VERSION 5.8 ;
BUSBITCHARS "[]" ;
DIVIDERCHAR "/" ;
UNITS
    DATABASE MICRONS 1000 ;
END UNITS

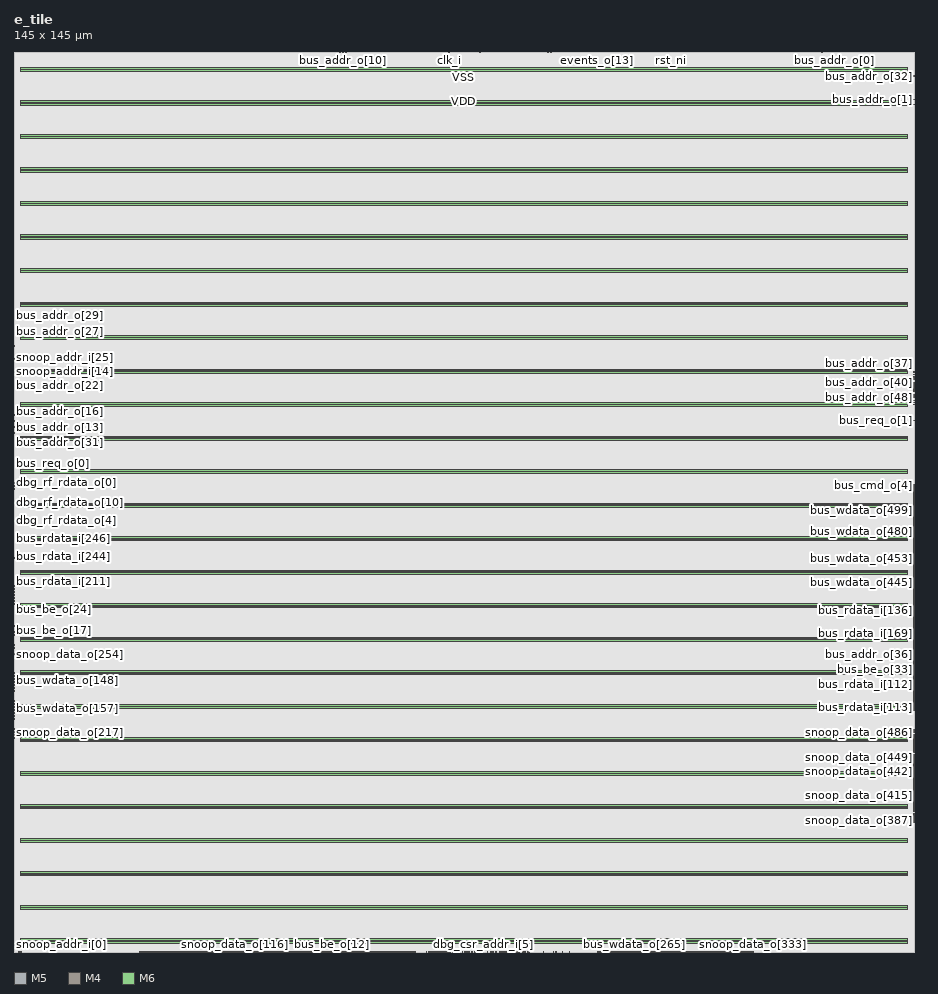
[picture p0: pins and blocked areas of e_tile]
MACRO e_tile
  FOREIGN e_tile 0 0 ;
  CLASS BLOCK ;
  SIZE 145 BY 145 ;
  PIN bus_addr_o[0]
    DIRECTION OUTPUT ;
    USE SIGNAL ;
    PORT
      LAYER M5 ;
        RECT  132.192 144.916 132.216 145 ;
    END
  END bus_addr_o[0]
  PIN bus_addr_o[10]
    DIRECTION OUTPUT ;
    USE SIGNAL ;
    PORT
      LAYER M5 ;
        RECT  52.992 144.916 53.016 145 ;
    END
  END bus_addr_o[10]
  PIN bus_addr_o[11]
    DIRECTION OUTPUT ;
    USE SIGNAL ;
    PORT
      LAYER M5 ;
        RECT  52.608 144.916 52.632 145 ;
    END
  END bus_addr_o[11]
  PIN bus_addr_o[12]
    DIRECTION OUTPUT ;
    USE SIGNAL ;
    PORT
      LAYER M5 ;
        RECT  52.416 144.916 52.44 145 ;
    END
  END bus_addr_o[12]
  PIN bus_addr_o[13]
    DIRECTION OUTPUT ;
    USE SIGNAL ;
    PORT
      LAYER M4 ;
        RECT  0 84.48 0.084 84.504 ;
    END
  END bus_addr_o[13]
  PIN bus_addr_o[14]
    DIRECTION OUTPUT ;
    USE SIGNAL ;
    PORT
      LAYER M4 ;
        RECT  0 84.576 0.084 84.6 ;
    END
  END bus_addr_o[14]
  PIN bus_addr_o[15]
    DIRECTION OUTPUT ;
    USE SIGNAL ;
    PORT
      LAYER M4 ;
        RECT  0 83.616 0.084 83.64 ;
    END
  END bus_addr_o[15]
  PIN bus_addr_o[16]
    DIRECTION OUTPUT ;
    USE SIGNAL ;
    PORT
      LAYER M4 ;
        RECT  0 85.728 0.084 85.752 ;
    END
  END bus_addr_o[16]
  PIN bus_addr_o[17]
    DIRECTION OUTPUT ;
    USE SIGNAL ;
    PORT
      LAYER M4 ;
        RECT  0 86.784 0.084 86.808 ;
    END
  END bus_addr_o[17]
  PIN bus_addr_o[18]
    DIRECTION OUTPUT ;
    USE SIGNAL ;
    PORT
      LAYER M4 ;
        RECT  0 86.976 0.084 87 ;
    END
  END bus_addr_o[18]
  PIN bus_addr_o[19]
    DIRECTION OUTPUT ;
    USE SIGNAL ;
    PORT
      LAYER M4 ;
        RECT  0 86.496 0.084 86.52 ;
    END
  END bus_addr_o[19]
  PIN bus_addr_o[1]
    DIRECTION OUTPUT ;
    USE SIGNAL ;
    PORT
      LAYER M4 ;
        RECT  144.916 137.28 145 137.304 ;
    END
  END bus_addr_o[1]
  PIN bus_addr_o[20]
    DIRECTION OUTPUT ;
    USE SIGNAL ;
    PORT
      LAYER M4 ;
        RECT  0 85.536 0.084 85.56 ;
    END
  END bus_addr_o[20]
  PIN bus_addr_o[21]
    DIRECTION OUTPUT ;
    USE SIGNAL ;
    PORT
      LAYER M4 ;
        RECT  0 86.88 0.084 86.904 ;
    END
  END bus_addr_o[21]
  PIN bus_addr_o[22]
    DIRECTION OUTPUT ;
    USE SIGNAL ;
    PORT
      LAYER M4 ;
        RECT  0 91.2 0.084 91.224 ;
    END
  END bus_addr_o[22]
  PIN bus_addr_o[23]
    DIRECTION OUTPUT ;
    USE SIGNAL ;
    PORT
      LAYER M4 ;
        RECT  0 88.32 0.084 88.344 ;
    END
  END bus_addr_o[23]
  PIN bus_addr_o[24]
    DIRECTION OUTPUT ;
    USE SIGNAL ;
    PORT
      LAYER M4 ;
        RECT  0 92.352 0.084 92.376 ;
    END
  END bus_addr_o[24]
  PIN bus_addr_o[25]
    DIRECTION OUTPUT ;
    USE SIGNAL ;
    PORT
      LAYER M4 ;
        RECT  0 88.896 0.084 88.92 ;
    END
  END bus_addr_o[25]
  PIN bus_addr_o[26]
    DIRECTION OUTPUT ;
    USE SIGNAL ;
    PORT
      LAYER M5 ;
        RECT  38.4 144.916 38.424 145 ;
    END
  END bus_addr_o[26]
  PIN bus_addr_o[27]
    DIRECTION OUTPUT ;
    USE SIGNAL ;
    PORT
      LAYER M4 ;
        RECT  0 99.936 0.084 99.96 ;
    END
  END bus_addr_o[27]
  PIN bus_addr_o[28]
    DIRECTION OUTPUT ;
    USE SIGNAL ;
    PORT
      LAYER M4 ;
        RECT  0 100.896 0.084 100.92 ;
    END
  END bus_addr_o[28]
  PIN bus_addr_o[29]
    DIRECTION OUTPUT ;
    USE SIGNAL ;
    PORT
      LAYER M4 ;
        RECT  0 101.184 0.084 101.208 ;
    END
  END bus_addr_o[29]
  PIN bus_addr_o[2]
    DIRECTION OUTPUT ;
    USE SIGNAL ;
    PORT
      LAYER M4 ;
        RECT  0 62.112 0.084 62.136 ;
    END
  END bus_addr_o[2]
  PIN bus_addr_o[30]
    DIRECTION OUTPUT ;
    USE SIGNAL ;
    PORT
      LAYER M5 ;
        RECT  39.552 144.916 39.576 145 ;
    END
  END bus_addr_o[30]
  PIN bus_addr_o[31]
    DIRECTION OUTPUT ;
    USE SIGNAL ;
    PORT
      LAYER M4 ;
        RECT  0 83.328 0.084 83.352 ;
    END
  END bus_addr_o[31]
  PIN bus_addr_o[32]
    DIRECTION OUTPUT ;
    USE SIGNAL ;
    PORT
      LAYER M4 ;
        RECT  144.916 141.12 145 141.144 ;
    END
  END bus_addr_o[32]
  PIN bus_addr_o[33]
    DIRECTION OUTPUT ;
    USE SIGNAL ;
    PORT
      LAYER M5 ;
        RECT  134.208 144.916 134.232 145 ;
    END
  END bus_addr_o[33]
  PIN bus_addr_o[34]
    DIRECTION OUTPUT ;
    USE SIGNAL ;
    PORT
      LAYER M4 ;
        RECT  144.916 56.64 145 56.664 ;
    END
  END bus_addr_o[34]
  PIN bus_addr_o[35]
    DIRECTION OUTPUT ;
    USE SIGNAL ;
    PORT
      LAYER M4 ;
        RECT  144.916 41.376 145 41.4 ;
    END
  END bus_addr_o[35]
  PIN bus_addr_o[36]
    DIRECTION OUTPUT ;
    USE SIGNAL ;
    PORT
      LAYER M4 ;
        RECT  144.916 47.904 145 47.928 ;
    END
  END bus_addr_o[36]
  PIN bus_addr_o[37]
    DIRECTION OUTPUT ;
    USE SIGNAL ;
    PORT
      LAYER M4 ;
        RECT  144.916 93.504 145 93.528 ;
    END
  END bus_addr_o[37]
  PIN bus_addr_o[38]
    DIRECTION OUTPUT ;
    USE SIGNAL ;
    PORT
      LAYER M4 ;
        RECT  144.916 93.408 145 93.432 ;
    END
  END bus_addr_o[38]
  PIN bus_addr_o[39]
    DIRECTION OUTPUT ;
    USE SIGNAL ;
    PORT
      LAYER M4 ;
        RECT  144.916 93.312 145 93.336 ;
    END
  END bus_addr_o[39]
  PIN bus_addr_o[3]
    DIRECTION OUTPUT ;
    USE SIGNAL ;
    PORT
      LAYER M4 ;
        RECT  0 54.048 0.084 54.072 ;
    END
  END bus_addr_o[3]
  PIN bus_addr_o[40]
    DIRECTION OUTPUT ;
    USE SIGNAL ;
    PORT
      LAYER M4 ;
        RECT  144.916 91.68 145 91.704 ;
    END
  END bus_addr_o[40]
  PIN bus_addr_o[41]
    DIRECTION OUTPUT ;
    USE SIGNAL ;
    PORT
      LAYER M4 ;
        RECT  144.916 92.64 145 92.664 ;
    END
  END bus_addr_o[41]
  PIN bus_addr_o[42]
    DIRECTION OUTPUT ;
    USE SIGNAL ;
    PORT
      LAYER M4 ;
        RECT  144.916 92.544 145 92.568 ;
    END
  END bus_addr_o[42]
  PIN bus_addr_o[43]
    DIRECTION OUTPUT ;
    USE SIGNAL ;
    PORT
      LAYER M4 ;
        RECT  144.916 93.024 145 93.048 ;
    END
  END bus_addr_o[43]
  PIN bus_addr_o[44]
    DIRECTION OUTPUT ;
    USE SIGNAL ;
    PORT
      LAYER M4 ;
        RECT  144.916 91.2 145 91.224 ;
    END
  END bus_addr_o[44]
  PIN bus_addr_o[45]
    DIRECTION OUTPUT ;
    USE SIGNAL ;
    PORT
      LAYER M4 ;
        RECT  144.916 90.72 145 90.744 ;
    END
  END bus_addr_o[45]
  PIN bus_addr_o[46]
    DIRECTION OUTPUT ;
    USE SIGNAL ;
    PORT
      LAYER M4 ;
        RECT  144.916 90.912 145 90.936 ;
    END
  END bus_addr_o[46]
  PIN bus_addr_o[47]
    DIRECTION OUTPUT ;
    USE SIGNAL ;
    PORT
      LAYER M4 ;
        RECT  144.916 90.816 145 90.84 ;
    END
  END bus_addr_o[47]
  PIN bus_addr_o[48]
    DIRECTION OUTPUT ;
    USE SIGNAL ;
    PORT
      LAYER M4 ;
        RECT  144.916 90.624 145 90.648 ;
    END
  END bus_addr_o[48]
  PIN bus_addr_o[49]
    DIRECTION OUTPUT ;
    USE SIGNAL ;
    PORT
      LAYER M4 ;
        RECT  144.916 91.488 145 91.512 ;
    END
  END bus_addr_o[49]
  PIN bus_addr_o[4]
    DIRECTION OUTPUT ;
    USE SIGNAL ;
    PORT
      LAYER M5 ;
        RECT  41.472 0 41.496 0.084 ;
    END
  END bus_addr_o[4]
  PIN bus_addr_o[50]
    DIRECTION OUTPUT ;
    USE SIGNAL ;
    PORT
      LAYER M4 ;
        RECT  144.916 92.736 145 92.76 ;
    END
  END bus_addr_o[50]
  PIN bus_addr_o[51]
    DIRECTION OUTPUT ;
    USE SIGNAL ;
    PORT
      LAYER M4 ;
        RECT  144.916 92.256 145 92.28 ;
    END
  END bus_addr_o[51]
  PIN bus_addr_o[52]
    DIRECTION OUTPUT ;
    USE SIGNAL ;
    PORT
      LAYER M4 ;
        RECT  144.916 92.352 145 92.376 ;
    END
  END bus_addr_o[52]
  PIN bus_addr_o[53]
    DIRECTION OUTPUT ;
    USE SIGNAL ;
    PORT
      LAYER M4 ;
        RECT  144.916 91.104 145 91.128 ;
    END
  END bus_addr_o[53]
  PIN bus_addr_o[54]
    DIRECTION OUTPUT ;
    USE SIGNAL ;
    PORT
      LAYER M4 ;
        RECT  144.916 90.24 145 90.264 ;
    END
  END bus_addr_o[54]
  PIN bus_addr_o[55]
    DIRECTION OUTPUT ;
    USE SIGNAL ;
    PORT
      LAYER M4 ;
        RECT  144.916 91.584 145 91.608 ;
    END
  END bus_addr_o[55]
  PIN bus_addr_o[56]
    DIRECTION OUTPUT ;
    USE SIGNAL ;
    PORT
      LAYER M4 ;
        RECT  144.916 90.528 145 90.552 ;
    END
  END bus_addr_o[56]
  PIN bus_addr_o[57]
    DIRECTION OUTPUT ;
    USE SIGNAL ;
    PORT
      LAYER M4 ;
        RECT  144.916 89.568 145 89.592 ;
    END
  END bus_addr_o[57]
  PIN bus_addr_o[58]
    DIRECTION OUTPUT ;
    USE SIGNAL ;
    PORT
      LAYER M4 ;
        RECT  144.916 91.296 145 91.32 ;
    END
  END bus_addr_o[58]
  PIN bus_addr_o[59]
    DIRECTION OUTPUT ;
    USE SIGNAL ;
    PORT
      LAYER M4 ;
        RECT  144.916 89.472 145 89.496 ;
    END
  END bus_addr_o[59]
  PIN bus_addr_o[5]
    DIRECTION OUTPUT ;
    USE SIGNAL ;
    PORT
      LAYER M5 ;
        RECT  52.224 144.916 52.248 145 ;
    END
  END bus_addr_o[5]
  PIN bus_addr_o[60]
    DIRECTION OUTPUT ;
    USE SIGNAL ;
    PORT
      LAYER M4 ;
        RECT  144.916 89.376 145 89.4 ;
    END
  END bus_addr_o[60]
  PIN bus_addr_o[61]
    DIRECTION OUTPUT ;
    USE SIGNAL ;
    PORT
      LAYER M4 ;
        RECT  144.916 89.28 145 89.304 ;
    END
  END bus_addr_o[61]
  PIN bus_addr_o[62]
    DIRECTION OUTPUT ;
    USE SIGNAL ;
    PORT
      LAYER M4 ;
        RECT  144.916 88.896 145 88.92 ;
    END
  END bus_addr_o[62]
  PIN bus_addr_o[63]
    DIRECTION OUTPUT ;
    USE SIGNAL ;
    PORT
      LAYER M4 ;
        RECT  144.916 89.76 145 89.784 ;
    END
  END bus_addr_o[63]
  PIN bus_addr_o[6]
    DIRECTION OUTPUT ;
    USE SIGNAL ;
    PORT
      LAYER M5 ;
        RECT  52.8 144.916 52.824 145 ;
    END
  END bus_addr_o[6]
  PIN bus_addr_o[7]
    DIRECTION OUTPUT ;
    USE SIGNAL ;
    PORT
      LAYER M5 ;
        RECT  52.32 144.916 52.344 145 ;
    END
  END bus_addr_o[7]
  PIN bus_addr_o[8]
    DIRECTION OUTPUT ;
    USE SIGNAL ;
    PORT
      LAYER M5 ;
        RECT  52.512 144.916 52.536 145 ;
    END
  END bus_addr_o[8]
  PIN bus_addr_o[9]
    DIRECTION OUTPUT ;
    USE SIGNAL ;
    PORT
      LAYER M5 ;
        RECT  52.896 144.916 52.92 145 ;
    END
  END bus_addr_o[9]
  PIN bus_be_o[0]
    DIRECTION OUTPUT ;
    USE SIGNAL ;
    PORT
      LAYER M5 ;
        RECT  51.936 0 51.96 0.084 ;
    END
  END bus_be_o[0]
  PIN bus_be_o[10]
    DIRECTION OUTPUT ;
    USE SIGNAL ;
    PORT
      LAYER M5 ;
        RECT  42.144 0 42.168 0.084 ;
    END
  END bus_be_o[10]
  PIN bus_be_o[11]
    DIRECTION OUTPUT ;
    USE SIGNAL ;
    PORT
      LAYER M5 ;
        RECT  41.568 0 41.592 0.084 ;
    END
  END bus_be_o[11]
  PIN bus_be_o[12]
    DIRECTION OUTPUT ;
    USE SIGNAL ;
    PORT
      LAYER M5 ;
        RECT  51.264 0 51.288 0.084 ;
    END
  END bus_be_o[12]
  PIN bus_be_o[13]
    DIRECTION OUTPUT ;
    USE SIGNAL ;
    PORT
      LAYER M5 ;
        RECT  41.856 0 41.88 0.084 ;
    END
  END bus_be_o[13]
  PIN bus_be_o[14]
    DIRECTION OUTPUT ;
    USE SIGNAL ;
    PORT
      LAYER M4 ;
        RECT  0 50.4 0.084 50.424 ;
    END
  END bus_be_o[14]
  PIN bus_be_o[15]
    DIRECTION OUTPUT ;
    USE SIGNAL ;
    PORT
      LAYER M5 ;
        RECT  45.888 0 45.912 0.084 ;
    END
  END bus_be_o[15]
  PIN bus_be_o[16]
    DIRECTION OUTPUT ;
    USE SIGNAL ;
    PORT
      LAYER M5 ;
        RECT  49.536 0 49.56 0.084 ;
    END
  END bus_be_o[16]
  PIN bus_be_o[17]
    DIRECTION OUTPUT ;
    USE SIGNAL ;
    PORT
      LAYER M4 ;
        RECT  0 51.84 0.084 51.864 ;
    END
  END bus_be_o[17]
  PIN bus_be_o[18]
    DIRECTION OUTPUT ;
    USE SIGNAL ;
    PORT
      LAYER M4 ;
        RECT  0 51.744 0.084 51.768 ;
    END
  END bus_be_o[18]
  PIN bus_be_o[19]
    DIRECTION OUTPUT ;
    USE SIGNAL ;
    PORT
      LAYER M4 ;
        RECT  0 51.648 0.084 51.672 ;
    END
  END bus_be_o[19]
  PIN bus_be_o[1]
    DIRECTION OUTPUT ;
    USE SIGNAL ;
    PORT
      LAYER M5 ;
        RECT  46.944 0 46.968 0.084 ;
    END
  END bus_be_o[1]
  PIN bus_be_o[20]
    DIRECTION OUTPUT ;
    USE SIGNAL ;
    PORT
      LAYER M5 ;
        RECT  49.824 0 49.848 0.084 ;
    END
  END bus_be_o[20]
  PIN bus_be_o[21]
    DIRECTION OUTPUT ;
    USE SIGNAL ;
    PORT
      LAYER M4 ;
        RECT  0 55.104 0.084 55.128 ;
    END
  END bus_be_o[21]
  PIN bus_be_o[22]
    DIRECTION OUTPUT ;
    USE SIGNAL ;
    PORT
      LAYER M4 ;
        RECT  0 55.296 0.084 55.32 ;
    END
  END bus_be_o[22]
  PIN bus_be_o[23]
    DIRECTION OUTPUT ;
    USE SIGNAL ;
    PORT
      LAYER M4 ;
        RECT  0 56.352 0.084 56.376 ;
    END
  END bus_be_o[23]
  PIN bus_be_o[24]
    DIRECTION OUTPUT ;
    USE SIGNAL ;
    PORT
      LAYER M4 ;
        RECT  0 55.2 0.084 55.224 ;
    END
  END bus_be_o[24]
  PIN bus_be_o[25]
    DIRECTION OUTPUT ;
    USE SIGNAL ;
    PORT
      LAYER M4 ;
        RECT  0 56.256 0.084 56.28 ;
    END
  END bus_be_o[25]
  PIN bus_be_o[26]
    DIRECTION OUTPUT ;
    USE SIGNAL ;
    PORT
      LAYER M4 ;
        RECT  0 58.272 0.084 58.296 ;
    END
  END bus_be_o[26]
  PIN bus_be_o[27]
    DIRECTION OUTPUT ;
    USE SIGNAL ;
    PORT
      LAYER M4 ;
        RECT  0 58.464 0.084 58.488 ;
    END
  END bus_be_o[27]
  PIN bus_be_o[28]
    DIRECTION OUTPUT ;
    USE SIGNAL ;
    PORT
      LAYER M4 ;
        RECT  0 57.696 0.084 57.72 ;
    END
  END bus_be_o[28]
  PIN bus_be_o[29]
    DIRECTION OUTPUT ;
    USE SIGNAL ;
    PORT
      LAYER M4 ;
        RECT  0 58.368 0.084 58.392 ;
    END
  END bus_be_o[29]
  PIN bus_be_o[2]
    DIRECTION OUTPUT ;
    USE SIGNAL ;
    PORT
      LAYER M5 ;
        RECT  49.92 0 49.944 0.084 ;
    END
  END bus_be_o[2]
  PIN bus_be_o[30]
    DIRECTION OUTPUT ;
    USE SIGNAL ;
    PORT
      LAYER M4 ;
        RECT  0 58.56 0.084 58.584 ;
    END
  END bus_be_o[30]
  PIN bus_be_o[31]
    DIRECTION OUTPUT ;
    USE SIGNAL ;
    PORT
      LAYER M4 ;
        RECT  0 57.6 0.084 57.624 ;
    END
  END bus_be_o[31]
  PIN bus_be_o[32]
    DIRECTION OUTPUT ;
    USE SIGNAL ;
    PORT
      LAYER M4 ;
        RECT  144.916 46.944 145 46.968 ;
    END
  END bus_be_o[32]
  PIN bus_be_o[33]
    DIRECTION OUTPUT ;
    USE SIGNAL ;
    PORT
      LAYER M4 ;
        RECT  144.916 46.848 145 46.872 ;
    END
  END bus_be_o[33]
  PIN bus_be_o[34]
    DIRECTION OUTPUT ;
    USE SIGNAL ;
    PORT
      LAYER M4 ;
        RECT  144.916 47.136 145 47.16 ;
    END
  END bus_be_o[34]
  PIN bus_be_o[35]
    DIRECTION OUTPUT ;
    USE SIGNAL ;
    PORT
      LAYER M4 ;
        RECT  144.916 42.24 145 42.264 ;
    END
  END bus_be_o[35]
  PIN bus_be_o[36]
    DIRECTION OUTPUT ;
    USE SIGNAL ;
    PORT
      LAYER M4 ;
        RECT  144.916 44.928 145 44.952 ;
    END
  END bus_be_o[36]
  PIN bus_be_o[37]
    DIRECTION OUTPUT ;
    USE SIGNAL ;
    PORT
      LAYER M4 ;
        RECT  144.916 45.888 145 45.912 ;
    END
  END bus_be_o[37]
  PIN bus_be_o[38]
    DIRECTION OUTPUT ;
    USE SIGNAL ;
    PORT
      LAYER M4 ;
        RECT  144.916 46.272 145 46.296 ;
    END
  END bus_be_o[38]
  PIN bus_be_o[39]
    DIRECTION OUTPUT ;
    USE SIGNAL ;
    PORT
      LAYER M4 ;
        RECT  144.916 46.464 145 46.488 ;
    END
  END bus_be_o[39]
  PIN bus_be_o[3]
    DIRECTION OUTPUT ;
    USE SIGNAL ;
    PORT
      LAYER M5 ;
        RECT  48.768 0 48.792 0.084 ;
    END
  END bus_be_o[3]
  PIN bus_be_o[40]
    DIRECTION OUTPUT ;
    USE SIGNAL ;
    PORT
      LAYER M4 ;
        RECT  144.916 47.04 145 47.064 ;
    END
  END bus_be_o[40]
  PIN bus_be_o[41]
    DIRECTION OUTPUT ;
    USE SIGNAL ;
    PORT
      LAYER M4 ;
        RECT  144.916 47.232 145 47.256 ;
    END
  END bus_be_o[41]
  PIN bus_be_o[42]
    DIRECTION OUTPUT ;
    USE SIGNAL ;
    PORT
      LAYER M4 ;
        RECT  144.916 46.752 145 46.776 ;
    END
  END bus_be_o[42]
  PIN bus_be_o[43]
    DIRECTION OUTPUT ;
    USE SIGNAL ;
    PORT
      LAYER M4 ;
        RECT  144.916 45.792 145 45.816 ;
    END
  END bus_be_o[43]
  PIN bus_be_o[44]
    DIRECTION OUTPUT ;
    USE SIGNAL ;
    PORT
      LAYER M4 ;
        RECT  144.916 46.368 145 46.392 ;
    END
  END bus_be_o[44]
  PIN bus_be_o[45]
    DIRECTION OUTPUT ;
    USE SIGNAL ;
    PORT
      LAYER M4 ;
        RECT  144.916 46.08 145 46.104 ;
    END
  END bus_be_o[45]
  PIN bus_be_o[46]
    DIRECTION OUTPUT ;
    USE SIGNAL ;
    PORT
      LAYER M4 ;
        RECT  144.916 45.984 145 46.008 ;
    END
  END bus_be_o[46]
  PIN bus_be_o[47]
    DIRECTION OUTPUT ;
    USE SIGNAL ;
    PORT
      LAYER M4 ;
        RECT  144.916 46.176 145 46.2 ;
    END
  END bus_be_o[47]
  PIN bus_be_o[48]
    DIRECTION OUTPUT ;
    USE SIGNAL ;
    PORT
      LAYER M4 ;
        RECT  144.916 48 145 48.024 ;
    END
  END bus_be_o[48]
  PIN bus_be_o[49]
    DIRECTION OUTPUT ;
    USE SIGNAL ;
    PORT
      LAYER M4 ;
        RECT  144.916 48.192 145 48.216 ;
    END
  END bus_be_o[49]
  PIN bus_be_o[4]
    DIRECTION OUTPUT ;
    USE SIGNAL ;
    PORT
      LAYER M5 ;
        RECT  51.072 0 51.096 0.084 ;
    END
  END bus_be_o[4]
  PIN bus_be_o[50]
    DIRECTION OUTPUT ;
    USE SIGNAL ;
    PORT
      LAYER M4 ;
        RECT  144.916 47.808 145 47.832 ;
    END
  END bus_be_o[50]
  PIN bus_be_o[51]
    DIRECTION OUTPUT ;
    USE SIGNAL ;
    PORT
      LAYER M4 ;
        RECT  144.916 48.288 145 48.312 ;
    END
  END bus_be_o[51]
  PIN bus_be_o[52]
    DIRECTION OUTPUT ;
    USE SIGNAL ;
    PORT
      LAYER M4 ;
        RECT  144.916 49.824 145 49.848 ;
    END
  END bus_be_o[52]
  PIN bus_be_o[53]
    DIRECTION OUTPUT ;
    USE SIGNAL ;
    PORT
      LAYER M4 ;
        RECT  144.916 50.016 145 50.04 ;
    END
  END bus_be_o[53]
  PIN bus_be_o[54]
    DIRECTION OUTPUT ;
    USE SIGNAL ;
    PORT
      LAYER M4 ;
        RECT  144.916 50.496 145 50.52 ;
    END
  END bus_be_o[54]
  PIN bus_be_o[55]
    DIRECTION OUTPUT ;
    USE SIGNAL ;
    PORT
      LAYER M4 ;
        RECT  144.916 50.112 145 50.136 ;
    END
  END bus_be_o[55]
  PIN bus_be_o[56]
    DIRECTION OUTPUT ;
    USE SIGNAL ;
    PORT
      LAYER M4 ;
        RECT  144.916 48.672 145 48.696 ;
    END
  END bus_be_o[56]
  PIN bus_be_o[57]
    DIRECTION OUTPUT ;
    USE SIGNAL ;
    PORT
      LAYER M4 ;
        RECT  144.916 49.152 145 49.176 ;
    END
  END bus_be_o[57]
  PIN bus_be_o[58]
    DIRECTION OUTPUT ;
    USE SIGNAL ;
    PORT
      LAYER M4 ;
        RECT  144.916 48.96 145 48.984 ;
    END
  END bus_be_o[58]
  PIN bus_be_o[59]
    DIRECTION OUTPUT ;
    USE SIGNAL ;
    PORT
      LAYER M4 ;
        RECT  144.916 40.224 145 40.248 ;
    END
  END bus_be_o[59]
  PIN bus_be_o[5]
    DIRECTION OUTPUT ;
    USE SIGNAL ;
    PORT
      LAYER M5 ;
        RECT  49.056 0 49.08 0.084 ;
    END
  END bus_be_o[5]
  PIN bus_be_o[60]
    DIRECTION OUTPUT ;
    USE SIGNAL ;
    PORT
      LAYER M4 ;
        RECT  144.916 50.88 145 50.904 ;
    END
  END bus_be_o[60]
  PIN bus_be_o[61]
    DIRECTION OUTPUT ;
    USE SIGNAL ;
    PORT
      LAYER M4 ;
        RECT  144.916 50.784 145 50.808 ;
    END
  END bus_be_o[61]
  PIN bus_be_o[62]
    DIRECTION OUTPUT ;
    USE SIGNAL ;
    PORT
      LAYER M4 ;
        RECT  144.916 50.592 145 50.616 ;
    END
  END bus_be_o[62]
  PIN bus_be_o[63]
    DIRECTION OUTPUT ;
    USE SIGNAL ;
    PORT
      LAYER M4 ;
        RECT  144.916 50.688 145 50.712 ;
    END
  END bus_be_o[63]
  PIN bus_be_o[6]
    DIRECTION OUTPUT ;
    USE SIGNAL ;
    PORT
      LAYER M5 ;
        RECT  45.792 0 45.816 0.084 ;
    END
  END bus_be_o[6]
  PIN bus_be_o[7]
    DIRECTION OUTPUT ;
    USE SIGNAL ;
    PORT
      LAYER M5 ;
        RECT  42.24 0 42.264 0.084 ;
    END
  END bus_be_o[7]
  PIN bus_be_o[8]
    DIRECTION OUTPUT ;
    USE SIGNAL ;
    PORT
      LAYER M5 ;
        RECT  49.728 0 49.752 0.084 ;
    END
  END bus_be_o[8]
  PIN bus_be_o[9]
    DIRECTION OUTPUT ;
    USE SIGNAL ;
    PORT
      LAYER M5 ;
        RECT  46.464 0 46.488 0.084 ;
    END
  END bus_be_o[9]
  PIN bus_cmd_o[0]
    DIRECTION OUTPUT ;
    USE SIGNAL ;
    PORT
      LAYER M4 ;
        RECT  0 57.312 0.084 57.336 ;
    END
  END bus_cmd_o[0]
  PIN bus_cmd_o[1]
    DIRECTION OUTPUT ;
    USE SIGNAL ;
    PORT
      LAYER M4 ;
        RECT  0 57.504 0.084 57.528 ;
    END
  END bus_cmd_o[1]
  PIN bus_cmd_o[2]
    DIRECTION OUTPUT ;
    USE SIGNAL ;
    PORT
      LAYER M4 ;
        RECT  0 57.408 0.084 57.432 ;
    END
  END bus_cmd_o[2]
  PIN bus_cmd_o[3]
    DIRECTION OUTPUT ;
    USE SIGNAL ;
    PORT
      LAYER M4 ;
        RECT  144.916 57.792 145 57.816 ;
    END
  END bus_cmd_o[3]
  PIN bus_cmd_o[4]
    DIRECTION OUTPUT ;
    USE SIGNAL ;
    PORT
      LAYER M4 ;
        RECT  144.916 75.168 145 75.192 ;
    END
  END bus_cmd_o[4]
  PIN bus_cmd_o[5]
    DIRECTION OUTPUT ;
    USE SIGNAL ;
    PORT
      LAYER M4 ;
        RECT  144.916 70.176 145 70.2 ;
    END
  END bus_cmd_o[5]
  PIN bus_done_i[0]
    DIRECTION INPUT ;
    USE SIGNAL ;
    PORT
      LAYER M5 ;
        RECT  55.68 144.916 55.704 145 ;
    END
  END bus_done_i[0]
  PIN bus_done_i[1]
    DIRECTION INPUT ;
    USE SIGNAL ;
    PORT
      LAYER M4 ;
        RECT  144.916 88.512 145 88.536 ;
    END
  END bus_done_i[1]
  PIN bus_err_i
    DIRECTION INPUT ;
    USE SIGNAL ;
    PORT
      LAYER M4 ;
        RECT  144.916 75.36 145 75.384 ;
    END
  END bus_err_i
  PIN bus_rdata_i[0]
    DIRECTION INPUT ;
    USE SIGNAL ;
    PORT
      LAYER M5 ;
        RECT  58.368 0 58.392 0.084 ;
    END
  END bus_rdata_i[0]
  PIN bus_rdata_i[100]
    DIRECTION INPUT ;
    USE SIGNAL ;
    PORT
      LAYER M5 ;
        RECT  58.464 0 58.488 0.084 ;
    END
  END bus_rdata_i[100]
  PIN bus_rdata_i[101]
    DIRECTION INPUT ;
    USE SIGNAL ;
    PORT
      LAYER M5 ;
        RECT  58.56 0 58.584 0.084 ;
    END
  END bus_rdata_i[101]
  PIN bus_rdata_i[102]
    DIRECTION INPUT ;
    USE SIGNAL ;
    PORT
      LAYER M5 ;
        RECT  58.656 0 58.68 0.084 ;
    END
  END bus_rdata_i[102]
  PIN bus_rdata_i[103]
    DIRECTION INPUT ;
    USE SIGNAL ;
    PORT
      LAYER M5 ;
        RECT  58.752 0 58.776 0.084 ;
    END
  END bus_rdata_i[103]
  PIN bus_rdata_i[104]
    DIRECTION INPUT ;
    USE SIGNAL ;
    PORT
      LAYER M5 ;
        RECT  58.848 0 58.872 0.084 ;
    END
  END bus_rdata_i[104]
  PIN bus_rdata_i[105]
    DIRECTION INPUT ;
    USE SIGNAL ;
    PORT
      LAYER M4 ;
        RECT  144.916 41.088 145 41.112 ;
    END
  END bus_rdata_i[105]
  PIN bus_rdata_i[106]
    DIRECTION INPUT ;
    USE SIGNAL ;
    PORT
      LAYER M4 ;
        RECT  144.916 41.856 145 41.88 ;
    END
  END bus_rdata_i[106]
  PIN bus_rdata_i[107]
    DIRECTION INPUT ;
    USE SIGNAL ;
    PORT
      LAYER M4 ;
        RECT  144.916 42.048 145 42.072 ;
    END
  END bus_rdata_i[107]
  PIN bus_rdata_i[108]
    DIRECTION INPUT ;
    USE SIGNAL ;
    PORT
      LAYER M4 ;
        RECT  144.916 43.872 145 43.896 ;
    END
  END bus_rdata_i[108]
  PIN bus_rdata_i[109]
    DIRECTION INPUT ;
    USE SIGNAL ;
    PORT
      LAYER M4 ;
        RECT  144.916 44.448 145 44.472 ;
    END
  END bus_rdata_i[109]
  PIN bus_rdata_i[10]
    DIRECTION INPUT ;
    USE SIGNAL ;
    PORT
      LAYER M5 ;
        RECT  56.256 0 56.28 0.084 ;
    END
  END bus_rdata_i[10]
  PIN bus_rdata_i[110]
    DIRECTION INPUT ;
    USE SIGNAL ;
    PORT
      LAYER M4 ;
        RECT  144.916 42.432 145 42.456 ;
    END
  END bus_rdata_i[110]
  PIN bus_rdata_i[111]
    DIRECTION INPUT ;
    USE SIGNAL ;
    PORT
      LAYER M4 ;
        RECT  144.916 42.144 145 42.168 ;
    END
  END bus_rdata_i[111]
  PIN bus_rdata_i[112]
    DIRECTION INPUT ;
    USE SIGNAL ;
    PORT
      LAYER M4 ;
        RECT  144.916 43.008 145 43.032 ;
    END
  END bus_rdata_i[112]
  PIN bus_rdata_i[113]
    DIRECTION INPUT ;
    USE SIGNAL ;
    PORT
      LAYER M4 ;
        RECT  144.916 39.456 145 39.48 ;
    END
  END bus_rdata_i[113]
  PIN bus_rdata_i[114]
    DIRECTION INPUT ;
    USE SIGNAL ;
    PORT
      LAYER M4 ;
        RECT  144.916 43.104 145 43.128 ;
    END
  END bus_rdata_i[114]
  PIN bus_rdata_i[115]
    DIRECTION INPUT ;
    USE SIGNAL ;
    PORT
      LAYER M4 ;
        RECT  144.916 41.952 145 41.976 ;
    END
  END bus_rdata_i[115]
  PIN bus_rdata_i[116]
    DIRECTION INPUT ;
    USE SIGNAL ;
    PORT
      LAYER M4 ;
        RECT  144.916 39.552 145 39.576 ;
    END
  END bus_rdata_i[116]
  PIN bus_rdata_i[117]
    DIRECTION INPUT ;
    USE SIGNAL ;
    PORT
      LAYER M4 ;
        RECT  144.916 40.128 145 40.152 ;
    END
  END bus_rdata_i[117]
  PIN bus_rdata_i[118]
    DIRECTION INPUT ;
    USE SIGNAL ;
    PORT
      LAYER M4 ;
        RECT  144.916 39.648 145 39.672 ;
    END
  END bus_rdata_i[118]
  PIN bus_rdata_i[119]
    DIRECTION INPUT ;
    USE SIGNAL ;
    PORT
      LAYER M4 ;
        RECT  144.916 39.264 145 39.288 ;
    END
  END bus_rdata_i[119]
  PIN bus_rdata_i[11]
    DIRECTION INPUT ;
    USE SIGNAL ;
    PORT
      LAYER M5 ;
        RECT  57.984 0 58.008 0.084 ;
    END
  END bus_rdata_i[11]
  PIN bus_rdata_i[120]
    DIRECTION INPUT ;
    USE SIGNAL ;
    PORT
      LAYER M4 ;
        RECT  144.916 42.816 145 42.84 ;
    END
  END bus_rdata_i[120]
  PIN bus_rdata_i[121]
    DIRECTION INPUT ;
    USE SIGNAL ;
    PORT
      LAYER M4 ;
        RECT  144.916 42.336 145 42.36 ;
    END
  END bus_rdata_i[121]
  PIN bus_rdata_i[122]
    DIRECTION INPUT ;
    USE SIGNAL ;
    PORT
      LAYER M4 ;
        RECT  144.916 43.584 145 43.608 ;
    END
  END bus_rdata_i[122]
  PIN bus_rdata_i[123]
    DIRECTION INPUT ;
    USE SIGNAL ;
    PORT
      LAYER M4 ;
        RECT  144.916 42.624 145 42.648 ;
    END
  END bus_rdata_i[123]
  PIN bus_rdata_i[124]
    DIRECTION INPUT ;
    USE SIGNAL ;
    PORT
      LAYER M4 ;
        RECT  144.916 47.712 145 47.736 ;
    END
  END bus_rdata_i[124]
  PIN bus_rdata_i[125]
    DIRECTION INPUT ;
    USE SIGNAL ;
    PORT
      LAYER M4 ;
        RECT  144.916 40.8 145 40.824 ;
    END
  END bus_rdata_i[125]
  PIN bus_rdata_i[126]
    DIRECTION INPUT ;
    USE SIGNAL ;
    PORT
      LAYER M4 ;
        RECT  144.916 44.064 145 44.088 ;
    END
  END bus_rdata_i[126]
  PIN bus_rdata_i[127]
    DIRECTION INPUT ;
    USE SIGNAL ;
    PORT
      LAYER M4 ;
        RECT  144.916 44.352 145 44.376 ;
    END
  END bus_rdata_i[127]
  PIN bus_rdata_i[128]
    DIRECTION INPUT ;
    USE SIGNAL ;
    PORT
      LAYER M4 ;
        RECT  144.916 48.096 145 48.12 ;
    END
  END bus_rdata_i[128]
  PIN bus_rdata_i[129]
    DIRECTION INPUT ;
    USE SIGNAL ;
    PORT
      LAYER M5 ;
        RECT  58.944 0 58.968 0.084 ;
    END
  END bus_rdata_i[129]
  PIN bus_rdata_i[12]
    DIRECTION INPUT ;
    USE SIGNAL ;
    PORT
      LAYER M5 ;
        RECT  57.888 0 57.912 0.084 ;
    END
  END bus_rdata_i[12]
  PIN bus_rdata_i[130]
    DIRECTION INPUT ;
    USE SIGNAL ;
    PORT
      LAYER M5 ;
        RECT  59.04 0 59.064 0.084 ;
    END
  END bus_rdata_i[130]
  PIN bus_rdata_i[131]
    DIRECTION INPUT ;
    USE SIGNAL ;
    PORT
      LAYER M5 ;
        RECT  59.136 0 59.16 0.084 ;
    END
  END bus_rdata_i[131]
  PIN bus_rdata_i[132]
    DIRECTION INPUT ;
    USE SIGNAL ;
    PORT
      LAYER M5 ;
        RECT  59.232 0 59.256 0.084 ;
    END
  END bus_rdata_i[132]
  PIN bus_rdata_i[133]
    DIRECTION INPUT ;
    USE SIGNAL ;
    PORT
      LAYER M4 ;
        RECT  144.916 41.568 145 41.592 ;
    END
  END bus_rdata_i[133]
  PIN bus_rdata_i[134]
    DIRECTION INPUT ;
    USE SIGNAL ;
    PORT
      LAYER M5 ;
        RECT  59.328 0 59.352 0.084 ;
    END
  END bus_rdata_i[134]
  PIN bus_rdata_i[135]
    DIRECTION INPUT ;
    USE SIGNAL ;
    PORT
      LAYER M4 ;
        RECT  144.916 39.36 145 39.384 ;
    END
  END bus_rdata_i[135]
  PIN bus_rdata_i[136]
    DIRECTION INPUT ;
    USE SIGNAL ;
    PORT
      LAYER M4 ;
        RECT  144.916 55.008 145 55.032 ;
    END
  END bus_rdata_i[136]
  PIN bus_rdata_i[137]
    DIRECTION INPUT ;
    USE SIGNAL ;
    PORT
      LAYER M4 ;
        RECT  144.916 54.24 145 54.264 ;
    END
  END bus_rdata_i[137]
  PIN bus_rdata_i[138]
    DIRECTION INPUT ;
    USE SIGNAL ;
    PORT
      LAYER M4 ;
        RECT  144.916 55.776 145 55.8 ;
    END
  END bus_rdata_i[138]
  PIN bus_rdata_i[139]
    DIRECTION INPUT ;
    USE SIGNAL ;
    PORT
      LAYER M4 ;
        RECT  144.916 53.088 145 53.112 ;
    END
  END bus_rdata_i[139]
  PIN bus_rdata_i[13]
    DIRECTION INPUT ;
    USE SIGNAL ;
    PORT
      LAYER M5 ;
        RECT  57.792 0 57.816 0.084 ;
    END
  END bus_rdata_i[13]
  PIN bus_rdata_i[140]
    DIRECTION INPUT ;
    USE SIGNAL ;
    PORT
      LAYER M4 ;
        RECT  144.916 54.144 145 54.168 ;
    END
  END bus_rdata_i[140]
  PIN bus_rdata_i[141]
    DIRECTION INPUT ;
    USE SIGNAL ;
    PORT
      LAYER M4 ;
        RECT  144.916 53.856 145 53.88 ;
    END
  END bus_rdata_i[141]
  PIN bus_rdata_i[142]
    DIRECTION INPUT ;
    USE SIGNAL ;
    PORT
      LAYER M4 ;
        RECT  144.916 54.048 145 54.072 ;
    END
  END bus_rdata_i[142]
  PIN bus_rdata_i[143]
    DIRECTION INPUT ;
    USE SIGNAL ;
    PORT
      LAYER M4 ;
        RECT  144.916 54.816 145 54.84 ;
    END
  END bus_rdata_i[143]
  PIN bus_rdata_i[144]
    DIRECTION INPUT ;
    USE SIGNAL ;
    PORT
      LAYER M4 ;
        RECT  144.916 55.104 145 55.128 ;
    END
  END bus_rdata_i[144]
  PIN bus_rdata_i[145]
    DIRECTION INPUT ;
    USE SIGNAL ;
    PORT
      LAYER M4 ;
        RECT  144.916 53.184 145 53.208 ;
    END
  END bus_rdata_i[145]
  PIN bus_rdata_i[146]
    DIRECTION INPUT ;
    USE SIGNAL ;
    PORT
      LAYER M4 ;
        RECT  144.916 53.472 145 53.496 ;
    END
  END bus_rdata_i[146]
  PIN bus_rdata_i[147]
    DIRECTION INPUT ;
    USE SIGNAL ;
    PORT
      LAYER M4 ;
        RECT  144.916 52.896 145 52.92 ;
    END
  END bus_rdata_i[147]
  PIN bus_rdata_i[148]
    DIRECTION INPUT ;
    USE SIGNAL ;
    PORT
      LAYER M4 ;
        RECT  144.916 53.568 145 53.592 ;
    END
  END bus_rdata_i[148]
  PIN bus_rdata_i[149]
    DIRECTION INPUT ;
    USE SIGNAL ;
    PORT
      LAYER M4 ;
        RECT  0 53.568 0.084 53.592 ;
    END
  END bus_rdata_i[149]
  PIN bus_rdata_i[14]
    DIRECTION INPUT ;
    USE SIGNAL ;
    PORT
      LAYER M5 ;
        RECT  57.696 0 57.72 0.084 ;
    END
  END bus_rdata_i[14]
  PIN bus_rdata_i[150]
    DIRECTION INPUT ;
    USE SIGNAL ;
    PORT
      LAYER M4 ;
        RECT  0 53.376 0.084 53.4 ;
    END
  END bus_rdata_i[150]
  PIN bus_rdata_i[151]
    DIRECTION INPUT ;
    USE SIGNAL ;
    PORT
      LAYER M4 ;
        RECT  0 53.28 0.084 53.304 ;
    END
  END bus_rdata_i[151]
  PIN bus_rdata_i[152]
    DIRECTION INPUT ;
    USE SIGNAL ;
    PORT
      LAYER M4 ;
        RECT  144.916 56.064 145 56.088 ;
    END
  END bus_rdata_i[152]
  PIN bus_rdata_i[153]
    DIRECTION INPUT ;
    USE SIGNAL ;
    PORT
      LAYER M4 ;
        RECT  144.916 53.76 145 53.784 ;
    END
  END bus_rdata_i[153]
  PIN bus_rdata_i[154]
    DIRECTION INPUT ;
    USE SIGNAL ;
    PORT
      LAYER M4 ;
        RECT  144.916 52.608 145 52.632 ;
    END
  END bus_rdata_i[154]
  PIN bus_rdata_i[155]
    DIRECTION INPUT ;
    USE SIGNAL ;
    PORT
      LAYER M4 ;
        RECT  144.916 52.128 145 52.152 ;
    END
  END bus_rdata_i[155]
  PIN bus_rdata_i[156]
    DIRECTION INPUT ;
    USE SIGNAL ;
    PORT
      LAYER M4 ;
        RECT  144.916 53.376 145 53.4 ;
    END
  END bus_rdata_i[156]
  PIN bus_rdata_i[157]
    DIRECTION INPUT ;
    USE SIGNAL ;
    PORT
      LAYER M4 ;
        RECT  144.916 52.224 145 52.248 ;
    END
  END bus_rdata_i[157]
  PIN bus_rdata_i[158]
    DIRECTION INPUT ;
    USE SIGNAL ;
    PORT
      LAYER M4 ;
        RECT  144.916 52.512 145 52.536 ;
    END
  END bus_rdata_i[158]
  PIN bus_rdata_i[159]
    DIRECTION INPUT ;
    USE SIGNAL ;
    PORT
      LAYER M4 ;
        RECT  144.916 52.416 145 52.44 ;
    END
  END bus_rdata_i[159]
  PIN bus_rdata_i[15]
    DIRECTION INPUT ;
    USE SIGNAL ;
    PORT
      LAYER M5 ;
        RECT  57.6 0 57.624 0.084 ;
    END
  END bus_rdata_i[15]
  PIN bus_rdata_i[160]
    DIRECTION INPUT ;
    USE SIGNAL ;
    PORT
      LAYER M4 ;
        RECT  144.916 51.552 145 51.576 ;
    END
  END bus_rdata_i[160]
  PIN bus_rdata_i[161]
    DIRECTION INPUT ;
    USE SIGNAL ;
    PORT
      LAYER M5 ;
        RECT  59.424 0 59.448 0.084 ;
    END
  END bus_rdata_i[161]
  PIN bus_rdata_i[162]
    DIRECTION INPUT ;
    USE SIGNAL ;
    PORT
      LAYER M5 ;
        RECT  59.52 0 59.544 0.084 ;
    END
  END bus_rdata_i[162]
  PIN bus_rdata_i[163]
    DIRECTION INPUT ;
    USE SIGNAL ;
    PORT
      LAYER M5 ;
        RECT  59.616 0 59.64 0.084 ;
    END
  END bus_rdata_i[163]
  PIN bus_rdata_i[164]
    DIRECTION INPUT ;
    USE SIGNAL ;
    PORT
      LAYER M5 ;
        RECT  59.712 0 59.736 0.084 ;
    END
  END bus_rdata_i[164]
  PIN bus_rdata_i[165]
    DIRECTION INPUT ;
    USE SIGNAL ;
    PORT
      LAYER M4 ;
        RECT  144.916 41.28 145 41.304 ;
    END
  END bus_rdata_i[165]
  PIN bus_rdata_i[166]
    DIRECTION INPUT ;
    USE SIGNAL ;
    PORT
      LAYER M5 ;
        RECT  59.808 0 59.832 0.084 ;
    END
  END bus_rdata_i[166]
  PIN bus_rdata_i[167]
    DIRECTION INPUT ;
    USE SIGNAL ;
    PORT
      LAYER M4 ;
        RECT  144.916 48.384 145 48.408 ;
    END
  END bus_rdata_i[167]
  PIN bus_rdata_i[168]
    DIRECTION INPUT ;
    USE SIGNAL ;
    PORT
      LAYER M4 ;
        RECT  144.916 51.744 145 51.768 ;
    END
  END bus_rdata_i[168]
  PIN bus_rdata_i[169]
    DIRECTION INPUT ;
    USE SIGNAL ;
    PORT
      LAYER M4 ;
        RECT  144.916 51.264 145 51.288 ;
    END
  END bus_rdata_i[169]
  PIN bus_rdata_i[16]
    DIRECTION INPUT ;
    USE SIGNAL ;
    PORT
      LAYER M5 ;
        RECT  57.024 0 57.048 0.084 ;
    END
  END bus_rdata_i[16]
  PIN bus_rdata_i[170]
    DIRECTION INPUT ;
    USE SIGNAL ;
    PORT
      LAYER M4 ;
        RECT  144.916 51.168 145 51.192 ;
    END
  END bus_rdata_i[170]
  PIN bus_rdata_i[171]
    DIRECTION INPUT ;
    USE SIGNAL ;
    PORT
      LAYER M4 ;
        RECT  144.916 51.072 145 51.096 ;
    END
  END bus_rdata_i[171]
  PIN bus_rdata_i[172]
    DIRECTION INPUT ;
    USE SIGNAL ;
    PORT
      LAYER M4 ;
        RECT  144.916 51.648 145 51.672 ;
    END
  END bus_rdata_i[172]
  PIN bus_rdata_i[173]
    DIRECTION INPUT ;
    USE SIGNAL ;
    PORT
      LAYER M4 ;
        RECT  144.916 52.8 145 52.824 ;
    END
  END bus_rdata_i[173]
  PIN bus_rdata_i[174]
    DIRECTION INPUT ;
    USE SIGNAL ;
    PORT
      LAYER M4 ;
        RECT  144.916 52.992 145 53.016 ;
    END
  END bus_rdata_i[174]
  PIN bus_rdata_i[175]
    DIRECTION INPUT ;
    USE SIGNAL ;
    PORT
      LAYER M4 ;
        RECT  144.916 54.72 145 54.744 ;
    END
  END bus_rdata_i[175]
  PIN bus_rdata_i[176]
    DIRECTION INPUT ;
    USE SIGNAL ;
    PORT
      LAYER M4 ;
        RECT  144.916 54.528 145 54.552 ;
    END
  END bus_rdata_i[176]
  PIN bus_rdata_i[177]
    DIRECTION INPUT ;
    USE SIGNAL ;
    PORT
      LAYER M4 ;
        RECT  144.916 54.624 145 54.648 ;
    END
  END bus_rdata_i[177]
  PIN bus_rdata_i[178]
    DIRECTION INPUT ;
    USE SIGNAL ;
    PORT
      LAYER M4 ;
        RECT  144.916 56.448 145 56.472 ;
    END
  END bus_rdata_i[178]
  PIN bus_rdata_i[179]
    DIRECTION INPUT ;
    USE SIGNAL ;
    PORT
      LAYER M4 ;
        RECT  144.916 39.168 145 39.192 ;
    END
  END bus_rdata_i[179]
  PIN bus_rdata_i[17]
    DIRECTION INPUT ;
    USE SIGNAL ;
    PORT
      LAYER M5 ;
        RECT  57.504 0 57.528 0.084 ;
    END
  END bus_rdata_i[17]
  PIN bus_rdata_i[180]
    DIRECTION INPUT ;
    USE SIGNAL ;
    PORT
      LAYER M4 ;
        RECT  144.916 54.432 145 54.456 ;
    END
  END bus_rdata_i[180]
  PIN bus_rdata_i[181]
    DIRECTION INPUT ;
    USE SIGNAL ;
    PORT
      LAYER M4 ;
        RECT  0 54.336 0.084 54.36 ;
    END
  END bus_rdata_i[181]
  PIN bus_rdata_i[182]
    DIRECTION INPUT ;
    USE SIGNAL ;
    PORT
      LAYER M4 ;
        RECT  144.916 55.488 145 55.512 ;
    END
  END bus_rdata_i[182]
  PIN bus_rdata_i[183]
    DIRECTION INPUT ;
    USE SIGNAL ;
    PORT
      LAYER M4 ;
        RECT  0 55.008 0.084 55.032 ;
    END
  END bus_rdata_i[183]
  PIN bus_rdata_i[184]
    DIRECTION INPUT ;
    USE SIGNAL ;
    PORT
      LAYER M4 ;
        RECT  144.916 55.584 145 55.608 ;
    END
  END bus_rdata_i[184]
  PIN bus_rdata_i[185]
    DIRECTION INPUT ;
    USE SIGNAL ;
    PORT
      LAYER M4 ;
        RECT  144.916 55.296 145 55.32 ;
    END
  END bus_rdata_i[185]
  PIN bus_rdata_i[186]
    DIRECTION INPUT ;
    USE SIGNAL ;
    PORT
      LAYER M4 ;
        RECT  144.916 55.68 145 55.704 ;
    END
  END bus_rdata_i[186]
  PIN bus_rdata_i[187]
    DIRECTION INPUT ;
    USE SIGNAL ;
    PORT
      LAYER M4 ;
        RECT  144.916 55.872 145 55.896 ;
    END
  END bus_rdata_i[187]
  PIN bus_rdata_i[188]
    DIRECTION INPUT ;
    USE SIGNAL ;
    PORT
      LAYER M4 ;
        RECT  144.916 55.2 145 55.224 ;
    END
  END bus_rdata_i[188]
  PIN bus_rdata_i[189]
    DIRECTION INPUT ;
    USE SIGNAL ;
    PORT
      LAYER M4 ;
        RECT  144.916 55.392 145 55.416 ;
    END
  END bus_rdata_i[189]
  PIN bus_rdata_i[18]
    DIRECTION INPUT ;
    USE SIGNAL ;
    PORT
      LAYER M5 ;
        RECT  57.12 0 57.144 0.084 ;
    END
  END bus_rdata_i[18]
  PIN bus_rdata_i[190]
    DIRECTION INPUT ;
    USE SIGNAL ;
    PORT
      LAYER M4 ;
        RECT  144.916 56.16 145 56.184 ;
    END
  END bus_rdata_i[190]
  PIN bus_rdata_i[191]
    DIRECTION INPUT ;
    USE SIGNAL ;
    PORT
      LAYER M4 ;
        RECT  144.916 57.984 145 58.008 ;
    END
  END bus_rdata_i[191]
  PIN bus_rdata_i[192]
    DIRECTION INPUT ;
    USE SIGNAL ;
    PORT
      LAYER M4 ;
        RECT  144.916 56.736 145 56.76 ;
    END
  END bus_rdata_i[192]
  PIN bus_rdata_i[193]
    DIRECTION INPUT ;
    USE SIGNAL ;
    PORT
      LAYER M4 ;
        RECT  144.916 57.696 145 57.72 ;
    END
  END bus_rdata_i[193]
  PIN bus_rdata_i[194]
    DIRECTION INPUT ;
    USE SIGNAL ;
    PORT
      LAYER M4 ;
        RECT  144.916 57.408 145 57.432 ;
    END
  END bus_rdata_i[194]
  PIN bus_rdata_i[195]
    DIRECTION INPUT ;
    USE SIGNAL ;
    PORT
      LAYER M4 ;
        RECT  144.916 57.312 145 57.336 ;
    END
  END bus_rdata_i[195]
  PIN bus_rdata_i[196]
    DIRECTION INPUT ;
    USE SIGNAL ;
    PORT
      LAYER M4 ;
        RECT  144.916 57.6 145 57.624 ;
    END
  END bus_rdata_i[196]
  PIN bus_rdata_i[197]
    DIRECTION INPUT ;
    USE SIGNAL ;
    PORT
      LAYER M4 ;
        RECT  144.916 56.832 145 56.856 ;
    END
  END bus_rdata_i[197]
  PIN bus_rdata_i[198]
    DIRECTION INPUT ;
    USE SIGNAL ;
    PORT
      LAYER M4 ;
        RECT  144.916 57.216 145 57.24 ;
    END
  END bus_rdata_i[198]
  PIN bus_rdata_i[199]
    DIRECTION INPUT ;
    USE SIGNAL ;
    PORT
      LAYER M4 ;
        RECT  144.916 57.888 145 57.912 ;
    END
  END bus_rdata_i[199]
  PIN bus_rdata_i[19]
    DIRECTION INPUT ;
    USE SIGNAL ;
    PORT
      LAYER M5 ;
        RECT  57.408 0 57.432 0.084 ;
    END
  END bus_rdata_i[19]
  PIN bus_rdata_i[1]
    DIRECTION INPUT ;
    USE SIGNAL ;
    PORT
      LAYER M5 ;
        RECT  59.904 0 59.928 0.084 ;
    END
  END bus_rdata_i[1]
  PIN bus_rdata_i[200]
    DIRECTION INPUT ;
    USE SIGNAL ;
    PORT
      LAYER M4 ;
        RECT  144.916 56.256 145 56.28 ;
    END
  END bus_rdata_i[200]
  PIN bus_rdata_i[201]
    DIRECTION INPUT ;
    USE SIGNAL ;
    PORT
      LAYER M4 ;
        RECT  144.916 57.024 145 57.048 ;
    END
  END bus_rdata_i[201]
  PIN bus_rdata_i[202]
    DIRECTION INPUT ;
    USE SIGNAL ;
    PORT
      LAYER M4 ;
        RECT  144.916 56.544 145 56.568 ;
    END
  END bus_rdata_i[202]
  PIN bus_rdata_i[203]
    DIRECTION INPUT ;
    USE SIGNAL ;
    PORT
      LAYER M4 ;
        RECT  144.916 56.352 145 56.376 ;
    END
  END bus_rdata_i[203]
  PIN bus_rdata_i[204]
    DIRECTION INPUT ;
    USE SIGNAL ;
    PORT
      LAYER M4 ;
        RECT  144.916 57.12 145 57.144 ;
    END
  END bus_rdata_i[204]
  PIN bus_rdata_i[205]
    DIRECTION INPUT ;
    USE SIGNAL ;
    PORT
      LAYER M4 ;
        RECT  144.916 57.504 145 57.528 ;
    END
  END bus_rdata_i[205]
  PIN bus_rdata_i[206]
    DIRECTION INPUT ;
    USE SIGNAL ;
    PORT
      LAYER M4 ;
        RECT  0 57.792 0.084 57.816 ;
    END
  END bus_rdata_i[206]
  PIN bus_rdata_i[207]
    DIRECTION INPUT ;
    USE SIGNAL ;
    PORT
      LAYER M4 ;
        RECT  0 59.232 0.084 59.256 ;
    END
  END bus_rdata_i[207]
  PIN bus_rdata_i[208]
    DIRECTION INPUT ;
    USE SIGNAL ;
    PORT
      LAYER M4 ;
        RECT  0 60.096 0.084 60.12 ;
    END
  END bus_rdata_i[208]
  PIN bus_rdata_i[209]
    DIRECTION INPUT ;
    USE SIGNAL ;
    PORT
      LAYER M4 ;
        RECT  0 60.192 0.084 60.216 ;
    END
  END bus_rdata_i[209]
  PIN bus_rdata_i[20]
    DIRECTION INPUT ;
    USE SIGNAL ;
    PORT
      LAYER M5 ;
        RECT  56.832 0 56.856 0.084 ;
    END
  END bus_rdata_i[20]
  PIN bus_rdata_i[210]
    DIRECTION INPUT ;
    USE SIGNAL ;
    PORT
      LAYER M4 ;
        RECT  0 58.08 0.084 58.104 ;
    END
  END bus_rdata_i[210]
  PIN bus_rdata_i[211]
    DIRECTION INPUT ;
    USE SIGNAL ;
    PORT
      LAYER M4 ;
        RECT  0 59.712 0.084 59.736 ;
    END
  END bus_rdata_i[211]
  PIN bus_rdata_i[212]
    DIRECTION INPUT ;
    USE SIGNAL ;
    PORT
      LAYER M4 ;
        RECT  0 58.176 0.084 58.2 ;
    END
  END bus_rdata_i[212]
  PIN bus_rdata_i[213]
    DIRECTION INPUT ;
    USE SIGNAL ;
    PORT
      LAYER M4 ;
        RECT  0 58.656 0.084 58.68 ;
    END
  END bus_rdata_i[213]
  PIN bus_rdata_i[214]
    DIRECTION INPUT ;
    USE SIGNAL ;
    PORT
      LAYER M4 ;
        RECT  0 59.808 0.084 59.832 ;
    END
  END bus_rdata_i[214]
  PIN bus_rdata_i[215]
    DIRECTION INPUT ;
    USE SIGNAL ;
    PORT
      LAYER M4 ;
        RECT  0 58.944 0.084 58.968 ;
    END
  END bus_rdata_i[215]
  PIN bus_rdata_i[216]
    DIRECTION INPUT ;
    USE SIGNAL ;
    PORT
      LAYER M4 ;
        RECT  144.916 58.176 145 58.2 ;
    END
  END bus_rdata_i[216]
  PIN bus_rdata_i[217]
    DIRECTION INPUT ;
    USE SIGNAL ;
    PORT
      LAYER M4 ;
        RECT  144.916 67.776 145 67.8 ;
    END
  END bus_rdata_i[217]
  PIN bus_rdata_i[218]
    DIRECTION INPUT ;
    USE SIGNAL ;
    PORT
      LAYER M4 ;
        RECT  0 58.848 0.084 58.872 ;
    END
  END bus_rdata_i[218]
  PIN bus_rdata_i[219]
    DIRECTION INPUT ;
    USE SIGNAL ;
    PORT
      LAYER M4 ;
        RECT  0 58.752 0.084 58.776 ;
    END
  END bus_rdata_i[219]
  PIN bus_rdata_i[21]
    DIRECTION INPUT ;
    USE SIGNAL ;
    PORT
      LAYER M5 ;
        RECT  57.216 0 57.24 0.084 ;
    END
  END bus_rdata_i[21]
  PIN bus_rdata_i[220]
    DIRECTION INPUT ;
    USE SIGNAL ;
    PORT
      LAYER M4 ;
        RECT  0 59.904 0.084 59.928 ;
    END
  END bus_rdata_i[220]
  PIN bus_rdata_i[221]
    DIRECTION INPUT ;
    USE SIGNAL ;
    PORT
      LAYER M4 ;
        RECT  0 60 0.084 60.024 ;
    END
  END bus_rdata_i[221]
  PIN bus_rdata_i[222]
    DIRECTION INPUT ;
    USE SIGNAL ;
    PORT
      LAYER M4 ;
        RECT  144.916 60.96 145 60.984 ;
    END
  END bus_rdata_i[222]
  PIN bus_rdata_i[223]
    DIRECTION INPUT ;
    USE SIGNAL ;
    PORT
      LAYER M4 ;
        RECT  0 59.04 0.084 59.064 ;
    END
  END bus_rdata_i[223]
  PIN bus_rdata_i[224]
    DIRECTION INPUT ;
    USE SIGNAL ;
    PORT
      LAYER M4 ;
        RECT  144.916 74.4 145 74.424 ;
    END
  END bus_rdata_i[224]
  PIN bus_rdata_i[225]
    DIRECTION INPUT ;
    USE SIGNAL ;
    PORT
      LAYER M4 ;
        RECT  144.916 64.224 145 64.248 ;
    END
  END bus_rdata_i[225]
  PIN bus_rdata_i[226]
    DIRECTION INPUT ;
    USE SIGNAL ;
    PORT
      LAYER M5 ;
        RECT  60 0 60.024 0.084 ;
    END
  END bus_rdata_i[226]
  PIN bus_rdata_i[227]
    DIRECTION INPUT ;
    USE SIGNAL ;
    PORT
      LAYER M4 ;
        RECT  144.916 61.824 145 61.848 ;
    END
  END bus_rdata_i[227]
  PIN bus_rdata_i[228]
    DIRECTION INPUT ;
    USE SIGNAL ;
    PORT
      LAYER M5 ;
        RECT  60.096 0 60.12 0.084 ;
    END
  END bus_rdata_i[228]
  PIN bus_rdata_i[229]
    DIRECTION INPUT ;
    USE SIGNAL ;
    PORT
      LAYER M4 ;
        RECT  144.916 58.08 145 58.104 ;
    END
  END bus_rdata_i[229]
  PIN bus_rdata_i[22]
    DIRECTION INPUT ;
    USE SIGNAL ;
    PORT
      LAYER M5 ;
        RECT  56.448 0 56.472 0.084 ;
    END
  END bus_rdata_i[22]
  PIN bus_rdata_i[230]
    DIRECTION INPUT ;
    USE SIGNAL ;
    PORT
      LAYER M4 ;
        RECT  144.916 71.616 145 71.64 ;
    END
  END bus_rdata_i[230]
  PIN bus_rdata_i[231]
    DIRECTION INPUT ;
    USE SIGNAL ;
    PORT
      LAYER M4 ;
        RECT  144.916 58.272 145 58.296 ;
    END
  END bus_rdata_i[231]
  PIN bus_rdata_i[232]
    DIRECTION INPUT ;
    USE SIGNAL ;
    PORT
      LAYER M4 ;
        RECT  144.916 63.936 145 63.96 ;
    END
  END bus_rdata_i[232]
  PIN bus_rdata_i[233]
    DIRECTION INPUT ;
    USE SIGNAL ;
    PORT
      LAYER M4 ;
        RECT  144.916 61.536 145 61.56 ;
    END
  END bus_rdata_i[233]
  PIN bus_rdata_i[234]
    DIRECTION INPUT ;
    USE SIGNAL ;
    PORT
      LAYER M4 ;
        RECT  144.916 65.952 145 65.976 ;
    END
  END bus_rdata_i[234]
  PIN bus_rdata_i[235]
    DIRECTION INPUT ;
    USE SIGNAL ;
    PORT
      LAYER M4 ;
        RECT  144.916 63.552 145 63.576 ;
    END
  END bus_rdata_i[235]
  PIN bus_rdata_i[236]
    DIRECTION INPUT ;
    USE SIGNAL ;
    PORT
      LAYER M4 ;
        RECT  144.916 69.696 145 69.72 ;
    END
  END bus_rdata_i[236]
  PIN bus_rdata_i[237]
    DIRECTION INPUT ;
    USE SIGNAL ;
    PORT
      LAYER M4 ;
        RECT  144.916 70.944 145 70.968 ;
    END
  END bus_rdata_i[237]
  PIN bus_rdata_i[238]
    DIRECTION INPUT ;
    USE SIGNAL ;
    PORT
      LAYER M4 ;
        RECT  144.916 68.928 145 68.952 ;
    END
  END bus_rdata_i[238]
  PIN bus_rdata_i[239]
    DIRECTION INPUT ;
    USE SIGNAL ;
    PORT
      LAYER M4 ;
        RECT  144.916 72.96 145 72.984 ;
    END
  END bus_rdata_i[239]
  PIN bus_rdata_i[23]
    DIRECTION INPUT ;
    USE SIGNAL ;
    PORT
      LAYER M5 ;
        RECT  56.544 0 56.568 0.084 ;
    END
  END bus_rdata_i[23]
  PIN bus_rdata_i[240]
    DIRECTION INPUT ;
    USE SIGNAL ;
    PORT
      LAYER M4 ;
        RECT  144.916 68.544 145 68.568 ;
    END
  END bus_rdata_i[240]
  PIN bus_rdata_i[241]
    DIRECTION INPUT ;
    USE SIGNAL ;
    PORT
      LAYER M4 ;
        RECT  0 63.744 0.084 63.768 ;
    END
  END bus_rdata_i[241]
  PIN bus_rdata_i[242]
    DIRECTION INPUT ;
    USE SIGNAL ;
    PORT
      LAYER M4 ;
        RECT  144.916 73.344 145 73.368 ;
    END
  END bus_rdata_i[242]
  PIN bus_rdata_i[243]
    DIRECTION INPUT ;
    USE SIGNAL ;
    PORT
      LAYER M4 ;
        RECT  144.916 68.736 145 68.76 ;
    END
  END bus_rdata_i[243]
  PIN bus_rdata_i[244]
    DIRECTION INPUT ;
    USE SIGNAL ;
    PORT
      LAYER M4 ;
        RECT  0 63.648 0.084 63.672 ;
    END
  END bus_rdata_i[244]
  PIN bus_rdata_i[245]
    DIRECTION INPUT ;
    USE SIGNAL ;
    PORT
      LAYER M4 ;
        RECT  0 63.456 0.084 63.48 ;
    END
  END bus_rdata_i[245]
  PIN bus_rdata_i[246]
    DIRECTION INPUT ;
    USE SIGNAL ;
    PORT
      LAYER M4 ;
        RECT  0 65.376 0.084 65.4 ;
    END
  END bus_rdata_i[246]
  PIN bus_rdata_i[247]
    DIRECTION INPUT ;
    USE SIGNAL ;
    PORT
      LAYER M4 ;
        RECT  0 64.512 0.084 64.536 ;
    END
  END bus_rdata_i[247]
  PIN bus_rdata_i[248]
    DIRECTION INPUT ;
    USE SIGNAL ;
    PORT
      LAYER M4 ;
        RECT  144.916 72.768 145 72.792 ;
    END
  END bus_rdata_i[248]
  PIN bus_rdata_i[249]
    DIRECTION INPUT ;
    USE SIGNAL ;
    PORT
      LAYER M4 ;
        RECT  144.916 74.496 145 74.52 ;
    END
  END bus_rdata_i[249]
  PIN bus_rdata_i[24]
    DIRECTION INPUT ;
    USE SIGNAL ;
    PORT
      LAYER M5 ;
        RECT  60.192 0 60.216 0.084 ;
    END
  END bus_rdata_i[24]
  PIN bus_rdata_i[250]
    DIRECTION INPUT ;
    USE SIGNAL ;
    PORT
      LAYER M4 ;
        RECT  144.916 66.528 145 66.552 ;
    END
  END bus_rdata_i[250]
  PIN bus_rdata_i[251]
    DIRECTION INPUT ;
    USE SIGNAL ;
    PORT
      LAYER M4 ;
        RECT  144.916 70.08 145 70.104 ;
    END
  END bus_rdata_i[251]
  PIN bus_rdata_i[252]
    DIRECTION INPUT ;
    USE SIGNAL ;
    PORT
      LAYER M4 ;
        RECT  144.916 65.76 145 65.784 ;
    END
  END bus_rdata_i[252]
  PIN bus_rdata_i[253]
    DIRECTION INPUT ;
    USE SIGNAL ;
    PORT
      LAYER M4 ;
        RECT  144.916 73.44 145 73.464 ;
    END
  END bus_rdata_i[253]
  PIN bus_rdata_i[254]
    DIRECTION INPUT ;
    USE SIGNAL ;
    PORT
      LAYER M4 ;
        RECT  144.916 68.448 145 68.472 ;
    END
  END bus_rdata_i[254]
  PIN bus_rdata_i[255]
    DIRECTION INPUT ;
    USE SIGNAL ;
    PORT
      LAYER M4 ;
        RECT  0 59.136 0.084 59.16 ;
    END
  END bus_rdata_i[255]
  PIN bus_rdata_i[25]
    DIRECTION INPUT ;
    USE SIGNAL ;
    PORT
      LAYER M5 ;
        RECT  60.288 0 60.312 0.084 ;
    END
  END bus_rdata_i[25]
  PIN bus_rdata_i[26]
    DIRECTION INPUT ;
    USE SIGNAL ;
    PORT
      LAYER M5 ;
        RECT  60.384 0 60.408 0.084 ;
    END
  END bus_rdata_i[26]
  PIN bus_rdata_i[27]
    DIRECTION INPUT ;
    USE SIGNAL ;
    PORT
      LAYER M5 ;
        RECT  60.48 0 60.504 0.084 ;
    END
  END bus_rdata_i[27]
  PIN bus_rdata_i[28]
    DIRECTION INPUT ;
    USE SIGNAL ;
    PORT
      LAYER M5 ;
        RECT  60.576 0 60.6 0.084 ;
    END
  END bus_rdata_i[28]
  PIN bus_rdata_i[29]
    DIRECTION INPUT ;
    USE SIGNAL ;
    PORT
      LAYER M5 ;
        RECT  60.672 0 60.696 0.084 ;
    END
  END bus_rdata_i[29]
  PIN bus_rdata_i[2]
    DIRECTION INPUT ;
    USE SIGNAL ;
    PORT
      LAYER M5 ;
        RECT  60.768 0 60.792 0.084 ;
    END
  END bus_rdata_i[2]
  PIN bus_rdata_i[30]
    DIRECTION INPUT ;
    USE SIGNAL ;
    PORT
      LAYER M5 ;
        RECT  60.864 0 60.888 0.084 ;
    END
  END bus_rdata_i[30]
  PIN bus_rdata_i[31]
    DIRECTION INPUT ;
    USE SIGNAL ;
    PORT
      LAYER M5 ;
        RECT  60.96 0 60.984 0.084 ;
    END
  END bus_rdata_i[31]
  PIN bus_rdata_i[32]
    DIRECTION INPUT ;
    USE SIGNAL ;
    PORT
      LAYER M5 ;
        RECT  61.056 0 61.08 0.084 ;
    END
  END bus_rdata_i[32]
  PIN bus_rdata_i[33]
    DIRECTION INPUT ;
    USE SIGNAL ;
    PORT
      LAYER M5 ;
        RECT  61.152 0 61.176 0.084 ;
    END
  END bus_rdata_i[33]
  PIN bus_rdata_i[34]
    DIRECTION INPUT ;
    USE SIGNAL ;
    PORT
      LAYER M5 ;
        RECT  61.248 0 61.272 0.084 ;
    END
  END bus_rdata_i[34]
  PIN bus_rdata_i[35]
    DIRECTION INPUT ;
    USE SIGNAL ;
    PORT
      LAYER M5 ;
        RECT  61.344 0 61.368 0.084 ;
    END
  END bus_rdata_i[35]
  PIN bus_rdata_i[36]
    DIRECTION INPUT ;
    USE SIGNAL ;
    PORT
      LAYER M5 ;
        RECT  61.44 0 61.464 0.084 ;
    END
  END bus_rdata_i[36]
  PIN bus_rdata_i[37]
    DIRECTION INPUT ;
    USE SIGNAL ;
    PORT
      LAYER M5 ;
        RECT  61.536 0 61.56 0.084 ;
    END
  END bus_rdata_i[37]
  PIN bus_rdata_i[38]
    DIRECTION INPUT ;
    USE SIGNAL ;
    PORT
      LAYER M5 ;
        RECT  61.632 0 61.656 0.084 ;
    END
  END bus_rdata_i[38]
  PIN bus_rdata_i[39]
    DIRECTION INPUT ;
    USE SIGNAL ;
    PORT
      LAYER M5 ;
        RECT  61.728 0 61.752 0.084 ;
    END
  END bus_rdata_i[39]
  PIN bus_rdata_i[3]
    DIRECTION INPUT ;
    USE SIGNAL ;
    PORT
      LAYER M5 ;
        RECT  61.824 0 61.848 0.084 ;
    END
  END bus_rdata_i[3]
  PIN bus_rdata_i[40]
    DIRECTION INPUT ;
    USE SIGNAL ;
    PORT
      LAYER M5 ;
        RECT  61.92 0 61.944 0.084 ;
    END
  END bus_rdata_i[40]
  PIN bus_rdata_i[41]
    DIRECTION INPUT ;
    USE SIGNAL ;
    PORT
      LAYER M5 ;
        RECT  62.016 0 62.04 0.084 ;
    END
  END bus_rdata_i[41]
  PIN bus_rdata_i[42]
    DIRECTION INPUT ;
    USE SIGNAL ;
    PORT
      LAYER M5 ;
        RECT  62.112 0 62.136 0.084 ;
    END
  END bus_rdata_i[42]
  PIN bus_rdata_i[43]
    DIRECTION INPUT ;
    USE SIGNAL ;
    PORT
      LAYER M5 ;
        RECT  62.208 0 62.232 0.084 ;
    END
  END bus_rdata_i[43]
  PIN bus_rdata_i[44]
    DIRECTION INPUT ;
    USE SIGNAL ;
    PORT
      LAYER M5 ;
        RECT  62.304 0 62.328 0.084 ;
    END
  END bus_rdata_i[44]
  PIN bus_rdata_i[45]
    DIRECTION INPUT ;
    USE SIGNAL ;
    PORT
      LAYER M5 ;
        RECT  62.4 0 62.424 0.084 ;
    END
  END bus_rdata_i[45]
  PIN bus_rdata_i[46]
    DIRECTION INPUT ;
    USE SIGNAL ;
    PORT
      LAYER M5 ;
        RECT  56.736 0 56.76 0.084 ;
    END
  END bus_rdata_i[46]
  PIN bus_rdata_i[47]
    DIRECTION INPUT ;
    USE SIGNAL ;
    PORT
      LAYER M5 ;
        RECT  56.64 0 56.664 0.084 ;
    END
  END bus_rdata_i[47]
  PIN bus_rdata_i[48]
    DIRECTION INPUT ;
    USE SIGNAL ;
    PORT
      LAYER M4 ;
        RECT  144.916 40.416 145 40.44 ;
    END
  END bus_rdata_i[48]
  PIN bus_rdata_i[49]
    DIRECTION INPUT ;
    USE SIGNAL ;
    PORT
      LAYER M4 ;
        RECT  144.916 43.68 145 43.704 ;
    END
  END bus_rdata_i[49]
  PIN bus_rdata_i[4]
    DIRECTION INPUT ;
    USE SIGNAL ;
    PORT
      LAYER M5 ;
        RECT  62.496 0 62.52 0.084 ;
    END
  END bus_rdata_i[4]
  PIN bus_rdata_i[50]
    DIRECTION INPUT ;
    USE SIGNAL ;
    PORT
      LAYER M4 ;
        RECT  144.916 42.72 145 42.744 ;
    END
  END bus_rdata_i[50]
  PIN bus_rdata_i[51]
    DIRECTION INPUT ;
    USE SIGNAL ;
    PORT
      LAYER M4 ;
        RECT  144.916 39.84 145 39.864 ;
    END
  END bus_rdata_i[51]
  PIN bus_rdata_i[52]
    DIRECTION INPUT ;
    USE SIGNAL ;
    PORT
      LAYER M4 ;
        RECT  144.916 41.472 145 41.496 ;
    END
  END bus_rdata_i[52]
  PIN bus_rdata_i[53]
    DIRECTION INPUT ;
    USE SIGNAL ;
    PORT
      LAYER M5 ;
        RECT  56.352 0 56.376 0.084 ;
    END
  END bus_rdata_i[53]
  PIN bus_rdata_i[54]
    DIRECTION INPUT ;
    USE SIGNAL ;
    PORT
      LAYER M4 ;
        RECT  144.916 41.664 145 41.688 ;
    END
  END bus_rdata_i[54]
  PIN bus_rdata_i[55]
    DIRECTION INPUT ;
    USE SIGNAL ;
    PORT
      LAYER M4 ;
        RECT  144.916 41.76 145 41.784 ;
    END
  END bus_rdata_i[55]
  PIN bus_rdata_i[56]
    DIRECTION INPUT ;
    USE SIGNAL ;
    PORT
      LAYER M4 ;
        RECT  144.916 45.024 145 45.048 ;
    END
  END bus_rdata_i[56]
  PIN bus_rdata_i[57]
    DIRECTION INPUT ;
    USE SIGNAL ;
    PORT
      LAYER M5 ;
        RECT  62.592 0 62.616 0.084 ;
    END
  END bus_rdata_i[57]
  PIN bus_rdata_i[58]
    DIRECTION INPUT ;
    USE SIGNAL ;
    PORT
      LAYER M5 ;
        RECT  62.688 0 62.712 0.084 ;
    END
  END bus_rdata_i[58]
  PIN bus_rdata_i[59]
    DIRECTION INPUT ;
    USE SIGNAL ;
    PORT
      LAYER M4 ;
        RECT  144.916 44.544 145 44.568 ;
    END
  END bus_rdata_i[59]
  PIN bus_rdata_i[5]
    DIRECTION INPUT ;
    USE SIGNAL ;
    PORT
      LAYER M5 ;
        RECT  62.784 0 62.808 0.084 ;
    END
  END bus_rdata_i[5]
  PIN bus_rdata_i[60]
    DIRECTION INPUT ;
    USE SIGNAL ;
    PORT
      LAYER M4 ;
        RECT  144.916 43.296 145 43.32 ;
    END
  END bus_rdata_i[60]
  PIN bus_rdata_i[61]
    DIRECTION INPUT ;
    USE SIGNAL ;
    PORT
      LAYER M5 ;
        RECT  62.88 0 62.904 0.084 ;
    END
  END bus_rdata_i[61]
  PIN bus_rdata_i[62]
    DIRECTION INPUT ;
    USE SIGNAL ;
    PORT
      LAYER M5 ;
        RECT  62.976 0 63 0.084 ;
    END
  END bus_rdata_i[62]
  PIN bus_rdata_i[63]
    DIRECTION INPUT ;
    USE SIGNAL ;
    PORT
      LAYER M5 ;
        RECT  63.072 0 63.096 0.084 ;
    END
  END bus_rdata_i[63]
  PIN bus_rdata_i[64]
    DIRECTION INPUT ;
    USE SIGNAL ;
    PORT
      LAYER M5 ;
        RECT  63.168 0 63.192 0.084 ;
    END
  END bus_rdata_i[64]
  PIN bus_rdata_i[65]
    DIRECTION INPUT ;
    USE SIGNAL ;
    PORT
      LAYER M5 ;
        RECT  63.264 0 63.288 0.084 ;
    END
  END bus_rdata_i[65]
  PIN bus_rdata_i[66]
    DIRECTION INPUT ;
    USE SIGNAL ;
    PORT
      LAYER M5 ;
        RECT  63.36 0 63.384 0.084 ;
    END
  END bus_rdata_i[66]
  PIN bus_rdata_i[67]
    DIRECTION INPUT ;
    USE SIGNAL ;
    PORT
      LAYER M5 ;
        RECT  63.456 0 63.48 0.084 ;
    END
  END bus_rdata_i[67]
  PIN bus_rdata_i[68]
    DIRECTION INPUT ;
    USE SIGNAL ;
    PORT
      LAYER M5 ;
        RECT  63.552 0 63.576 0.084 ;
    END
  END bus_rdata_i[68]
  PIN bus_rdata_i[69]
    DIRECTION INPUT ;
    USE SIGNAL ;
    PORT
      LAYER M5 ;
        RECT  63.648 0 63.672 0.084 ;
    END
  END bus_rdata_i[69]
  PIN bus_rdata_i[6]
    DIRECTION INPUT ;
    USE SIGNAL ;
    PORT
      LAYER M5 ;
        RECT  63.744 0 63.768 0.084 ;
    END
  END bus_rdata_i[6]
  PIN bus_rdata_i[70]
    DIRECTION INPUT ;
    USE SIGNAL ;
    PORT
      LAYER M5 ;
        RECT  63.84 0 63.864 0.084 ;
    END
  END bus_rdata_i[70]
  PIN bus_rdata_i[71]
    DIRECTION INPUT ;
    USE SIGNAL ;
    PORT
      LAYER M5 ;
        RECT  63.936 0 63.96 0.084 ;
    END
  END bus_rdata_i[71]
  PIN bus_rdata_i[72]
    DIRECTION INPUT ;
    USE SIGNAL ;
    PORT
      LAYER M5 ;
        RECT  57.312 0 57.336 0.084 ;
    END
  END bus_rdata_i[72]
  PIN bus_rdata_i[73]
    DIRECTION INPUT ;
    USE SIGNAL ;
    PORT
      LAYER M5 ;
        RECT  56.928 0 56.952 0.084 ;
    END
  END bus_rdata_i[73]
  PIN bus_rdata_i[74]
    DIRECTION INPUT ;
    USE SIGNAL ;
    PORT
      LAYER M5 ;
        RECT  64.032 0 64.056 0.084 ;
    END
  END bus_rdata_i[74]
  PIN bus_rdata_i[75]
    DIRECTION INPUT ;
    USE SIGNAL ;
    PORT
      LAYER M5 ;
        RECT  64.128 0 64.152 0.084 ;
    END
  END bus_rdata_i[75]
  PIN bus_rdata_i[76]
    DIRECTION INPUT ;
    USE SIGNAL ;
    PORT
      LAYER M4 ;
        RECT  144.916 39.744 145 39.768 ;
    END
  END bus_rdata_i[76]
  PIN bus_rdata_i[77]
    DIRECTION INPUT ;
    USE SIGNAL ;
    PORT
      LAYER M4 ;
        RECT  144.916 43.392 145 43.416 ;
    END
  END bus_rdata_i[77]
  PIN bus_rdata_i[78]
    DIRECTION INPUT ;
    USE SIGNAL ;
    PORT
      LAYER M4 ;
        RECT  144.916 40.992 145 41.016 ;
    END
  END bus_rdata_i[78]
  PIN bus_rdata_i[79]
    DIRECTION INPUT ;
    USE SIGNAL ;
    PORT
      LAYER M4 ;
        RECT  144.916 42.528 145 42.552 ;
    END
  END bus_rdata_i[79]
  PIN bus_rdata_i[7]
    DIRECTION INPUT ;
    USE SIGNAL ;
    PORT
      LAYER M5 ;
        RECT  64.224 0 64.248 0.084 ;
    END
  END bus_rdata_i[7]
  PIN bus_rdata_i[80]
    DIRECTION INPUT ;
    USE SIGNAL ;
    PORT
      LAYER M4 ;
        RECT  144.916 40.032 145 40.056 ;
    END
  END bus_rdata_i[80]
  PIN bus_rdata_i[81]
    DIRECTION INPUT ;
    USE SIGNAL ;
    PORT
      LAYER M4 ;
        RECT  144.916 40.704 145 40.728 ;
    END
  END bus_rdata_i[81]
  PIN bus_rdata_i[82]
    DIRECTION INPUT ;
    USE SIGNAL ;
    PORT
      LAYER M4 ;
        RECT  144.916 42.912 145 42.936 ;
    END
  END bus_rdata_i[82]
  PIN bus_rdata_i[83]
    DIRECTION INPUT ;
    USE SIGNAL ;
    PORT
      LAYER M4 ;
        RECT  144.916 39.936 145 39.96 ;
    END
  END bus_rdata_i[83]
  PIN bus_rdata_i[84]
    DIRECTION INPUT ;
    USE SIGNAL ;
    PORT
      LAYER M4 ;
        RECT  144.916 43.488 145 43.512 ;
    END
  END bus_rdata_i[84]
  PIN bus_rdata_i[85]
    DIRECTION INPUT ;
    USE SIGNAL ;
    PORT
      LAYER M4 ;
        RECT  144.916 40.512 145 40.536 ;
    END
  END bus_rdata_i[85]
  PIN bus_rdata_i[86]
    DIRECTION INPUT ;
    USE SIGNAL ;
    PORT
      LAYER M4 ;
        RECT  144.916 40.32 145 40.344 ;
    END
  END bus_rdata_i[86]
  PIN bus_rdata_i[87]
    DIRECTION INPUT ;
    USE SIGNAL ;
    PORT
      LAYER M4 ;
        RECT  144.916 43.2 145 43.224 ;
    END
  END bus_rdata_i[87]
  PIN bus_rdata_i[88]
    DIRECTION INPUT ;
    USE SIGNAL ;
    PORT
      LAYER M4 ;
        RECT  144.916 40.896 145 40.92 ;
    END
  END bus_rdata_i[88]
  PIN bus_rdata_i[89]
    DIRECTION INPUT ;
    USE SIGNAL ;
    PORT
      LAYER M4 ;
        RECT  144.916 45.408 145 45.432 ;
    END
  END bus_rdata_i[89]
  PIN bus_rdata_i[8]
    DIRECTION INPUT ;
    USE SIGNAL ;
    PORT
      LAYER M5 ;
        RECT  58.176 0 58.2 0.084 ;
    END
  END bus_rdata_i[8]
  PIN bus_rdata_i[90]
    DIRECTION INPUT ;
    USE SIGNAL ;
    PORT
      LAYER M4 ;
        RECT  144.916 45.216 145 45.24 ;
    END
  END bus_rdata_i[90]
  PIN bus_rdata_i[91]
    DIRECTION INPUT ;
    USE SIGNAL ;
    PORT
      LAYER M4 ;
        RECT  144.916 47.328 145 47.352 ;
    END
  END bus_rdata_i[91]
  PIN bus_rdata_i[92]
    DIRECTION INPUT ;
    USE SIGNAL ;
    PORT
      LAYER M4 ;
        RECT  144.916 47.616 145 47.64 ;
    END
  END bus_rdata_i[92]
  PIN bus_rdata_i[93]
    DIRECTION INPUT ;
    USE SIGNAL ;
    PORT
      LAYER M4 ;
        RECT  144.916 44.64 145 44.664 ;
    END
  END bus_rdata_i[93]
  PIN bus_rdata_i[94]
    DIRECTION INPUT ;
    USE SIGNAL ;
    PORT
      LAYER M4 ;
        RECT  144.916 45.6 145 45.624 ;
    END
  END bus_rdata_i[94]
  PIN bus_rdata_i[95]
    DIRECTION INPUT ;
    USE SIGNAL ;
    PORT
      LAYER M4 ;
        RECT  144.916 45.504 145 45.528 ;
    END
  END bus_rdata_i[95]
  PIN bus_rdata_i[96]
    DIRECTION INPUT ;
    USE SIGNAL ;
    PORT
      LAYER M5 ;
        RECT  64.32 0 64.344 0.084 ;
    END
  END bus_rdata_i[96]
  PIN bus_rdata_i[97]
    DIRECTION INPUT ;
    USE SIGNAL ;
    PORT
      LAYER M5 ;
        RECT  64.416 0 64.44 0.084 ;
    END
  END bus_rdata_i[97]
  PIN bus_rdata_i[98]
    DIRECTION INPUT ;
    USE SIGNAL ;
    PORT
      LAYER M5 ;
        RECT  64.512 0 64.536 0.084 ;
    END
  END bus_rdata_i[98]
  PIN bus_rdata_i[99]
    DIRECTION INPUT ;
    USE SIGNAL ;
    PORT
      LAYER M5 ;
        RECT  64.608 0 64.632 0.084 ;
    END
  END bus_rdata_i[99]
  PIN bus_rdata_i[9]
    DIRECTION INPUT ;
    USE SIGNAL ;
    PORT
      LAYER M5 ;
        RECT  58.08 0 58.104 0.084 ;
    END
  END bus_rdata_i[9]
  PIN bus_req_o[0]
    DIRECTION OUTPUT ;
    USE SIGNAL ;
    PORT
      LAYER M4 ;
        RECT  0 78.624 0.084 78.648 ;
    END
  END bus_req_o[0]
  PIN bus_req_o[1]
    DIRECTION OUTPUT ;
    USE SIGNAL ;
    PORT
      LAYER M4 ;
        RECT  144.916 85.632 145 85.656 ;
    END
  END bus_req_o[1]
  PIN bus_wdata_o[0]
    DIRECTION OUTPUT ;
    USE SIGNAL ;
    PORT
      LAYER M5 ;
        RECT  50.208 0 50.232 0.084 ;
    END
  END bus_wdata_o[0]
  PIN bus_wdata_o[100]
    DIRECTION OUTPUT ;
    USE SIGNAL ;
    PORT
      LAYER M5 ;
        RECT  53.184 0 53.208 0.084 ;
    END
  END bus_wdata_o[100]
  PIN bus_wdata_o[101]
    DIRECTION OUTPUT ;
    USE SIGNAL ;
    PORT
      LAYER M5 ;
        RECT  55.776 0 55.8 0.084 ;
    END
  END bus_wdata_o[101]
  PIN bus_wdata_o[102]
    DIRECTION OUTPUT ;
    USE SIGNAL ;
    PORT
      LAYER M5 ;
        RECT  51.36 0 51.384 0.084 ;
    END
  END bus_wdata_o[102]
  PIN bus_wdata_o[103]
    DIRECTION OUTPUT ;
    USE SIGNAL ;
    PORT
      LAYER M5 ;
        RECT  52.032 0 52.056 0.084 ;
    END
  END bus_wdata_o[103]
  PIN bus_wdata_o[104]
    DIRECTION OUTPUT ;
    USE SIGNAL ;
    PORT
      LAYER M5 ;
        RECT  55.68 0 55.704 0.084 ;
    END
  END bus_wdata_o[104]
  PIN bus_wdata_o[105]
    DIRECTION OUTPUT ;
    USE SIGNAL ;
    PORT
      LAYER M5 ;
        RECT  47.616 0 47.64 0.084 ;
    END
  END bus_wdata_o[105]
  PIN bus_wdata_o[106]
    DIRECTION OUTPUT ;
    USE SIGNAL ;
    PORT
      LAYER M5 ;
        RECT  41.76 0 41.784 0.084 ;
    END
  END bus_wdata_o[106]
  PIN bus_wdata_o[107]
    DIRECTION OUTPUT ;
    USE SIGNAL ;
    PORT
      LAYER M5 ;
        RECT  45.984 0 46.008 0.084 ;
    END
  END bus_wdata_o[107]
  PIN bus_wdata_o[108]
    DIRECTION OUTPUT ;
    USE SIGNAL ;
    PORT
      LAYER M5 ;
        RECT  45.6 0 45.624 0.084 ;
    END
  END bus_wdata_o[108]
  PIN bus_wdata_o[109]
    DIRECTION OUTPUT ;
    USE SIGNAL ;
    PORT
      LAYER M5 ;
        RECT  42.72 0 42.744 0.084 ;
    END
  END bus_wdata_o[109]
  PIN bus_wdata_o[10]
    DIRECTION OUTPUT ;
    USE SIGNAL ;
    PORT
      LAYER M5 ;
        RECT  47.424 0 47.448 0.084 ;
    END
  END bus_wdata_o[10]
  PIN bus_wdata_o[110]
    DIRECTION OUTPUT ;
    USE SIGNAL ;
    PORT
      LAYER M5 ;
        RECT  42.816 0 42.84 0.084 ;
    END
  END bus_wdata_o[110]
  PIN bus_wdata_o[111]
    DIRECTION OUTPUT ;
    USE SIGNAL ;
    PORT
      LAYER M5 ;
        RECT  43.104 0 43.128 0.084 ;
    END
  END bus_wdata_o[111]
  PIN bus_wdata_o[112]
    DIRECTION OUTPUT ;
    USE SIGNAL ;
    PORT
      LAYER M4 ;
        RECT  0 37.632 0.084 37.656 ;
    END
  END bus_wdata_o[112]
  PIN bus_wdata_o[113]
    DIRECTION OUTPUT ;
    USE SIGNAL ;
    PORT
      LAYER M4 ;
        RECT  0 38.688 0.084 38.712 ;
    END
  END bus_wdata_o[113]
  PIN bus_wdata_o[114]
    DIRECTION OUTPUT ;
    USE SIGNAL ;
    PORT
      LAYER M4 ;
        RECT  0 40.128 0.084 40.152 ;
    END
  END bus_wdata_o[114]
  PIN bus_wdata_o[115]
    DIRECTION OUTPUT ;
    USE SIGNAL ;
    PORT
      LAYER M4 ;
        RECT  0 40.032 0.084 40.056 ;
    END
  END bus_wdata_o[115]
  PIN bus_wdata_o[116]
    DIRECTION OUTPUT ;
    USE SIGNAL ;
    PORT
      LAYER M4 ;
        RECT  0 40.992 0.084 41.016 ;
    END
  END bus_wdata_o[116]
  PIN bus_wdata_o[117]
    DIRECTION OUTPUT ;
    USE SIGNAL ;
    PORT
      LAYER M4 ;
        RECT  0 46.272 0.084 46.296 ;
    END
  END bus_wdata_o[117]
  PIN bus_wdata_o[118]
    DIRECTION OUTPUT ;
    USE SIGNAL ;
    PORT
      LAYER M4 ;
        RECT  0 44.544 0.084 44.568 ;
    END
  END bus_wdata_o[118]
  PIN bus_wdata_o[119]
    DIRECTION OUTPUT ;
    USE SIGNAL ;
    PORT
      LAYER M4 ;
        RECT  0 48.768 0.084 48.792 ;
    END
  END bus_wdata_o[119]
  PIN bus_wdata_o[11]
    DIRECTION OUTPUT ;
    USE SIGNAL ;
    PORT
      LAYER M5 ;
        RECT  42.336 0 42.36 0.084 ;
    END
  END bus_wdata_o[11]
  PIN bus_wdata_o[120]
    DIRECTION OUTPUT ;
    USE SIGNAL ;
    PORT
      LAYER M4 ;
        RECT  0 49.056 0.084 49.08 ;
    END
  END bus_wdata_o[120]
  PIN bus_wdata_o[121]
    DIRECTION OUTPUT ;
    USE SIGNAL ;
    PORT
      LAYER M4 ;
        RECT  0 49.344 0.084 49.368 ;
    END
  END bus_wdata_o[121]
  PIN bus_wdata_o[122]
    DIRECTION OUTPUT ;
    USE SIGNAL ;
    PORT
      LAYER M4 ;
        RECT  0 48.864 0.084 48.888 ;
    END
  END bus_wdata_o[122]
  PIN bus_wdata_o[123]
    DIRECTION OUTPUT ;
    USE SIGNAL ;
    PORT
      LAYER M4 ;
        RECT  0 49.44 0.084 49.464 ;
    END
  END bus_wdata_o[123]
  PIN bus_wdata_o[124]
    DIRECTION OUTPUT ;
    USE SIGNAL ;
    PORT
      LAYER M4 ;
        RECT  0 49.248 0.084 49.272 ;
    END
  END bus_wdata_o[124]
  PIN bus_wdata_o[125]
    DIRECTION OUTPUT ;
    USE SIGNAL ;
    PORT
      LAYER M4 ;
        RECT  0 48.96 0.084 48.984 ;
    END
  END bus_wdata_o[125]
  PIN bus_wdata_o[126]
    DIRECTION OUTPUT ;
    USE SIGNAL ;
    PORT
      LAYER M4 ;
        RECT  0 49.152 0.084 49.176 ;
    END
  END bus_wdata_o[126]
  PIN bus_wdata_o[127]
    DIRECTION OUTPUT ;
    USE SIGNAL ;
    PORT
      LAYER M5 ;
        RECT  47.04 0 47.064 0.084 ;
    END
  END bus_wdata_o[127]
  PIN bus_wdata_o[128]
    DIRECTION OUTPUT ;
    USE SIGNAL ;
    PORT
      LAYER M5 ;
        RECT  49.632 0 49.656 0.084 ;
    END
  END bus_wdata_o[128]
  PIN bus_wdata_o[129]
    DIRECTION OUTPUT ;
    USE SIGNAL ;
    PORT
      LAYER M5 ;
        RECT  52.224 0 52.248 0.084 ;
    END
  END bus_wdata_o[129]
  PIN bus_wdata_o[12]
    DIRECTION OUTPUT ;
    USE SIGNAL ;
    PORT
      LAYER M5 ;
        RECT  46.272 0 46.296 0.084 ;
    END
  END bus_wdata_o[12]
  PIN bus_wdata_o[130]
    DIRECTION OUTPUT ;
    USE SIGNAL ;
    PORT
      LAYER M5 ;
        RECT  50.976 0 51 0.084 ;
    END
  END bus_wdata_o[130]
  PIN bus_wdata_o[131]
    DIRECTION OUTPUT ;
    USE SIGNAL ;
    PORT
      LAYER M5 ;
        RECT  54.432 0 54.456 0.084 ;
    END
  END bus_wdata_o[131]
  PIN bus_wdata_o[132]
    DIRECTION OUTPUT ;
    USE SIGNAL ;
    PORT
      LAYER M5 ;
        RECT  52.32 0 52.344 0.084 ;
    END
  END bus_wdata_o[132]
  PIN bus_wdata_o[133]
    DIRECTION OUTPUT ;
    USE SIGNAL ;
    PORT
      LAYER M5 ;
        RECT  52.128 0 52.152 0.084 ;
    END
  END bus_wdata_o[133]
  PIN bus_wdata_o[134]
    DIRECTION OUTPUT ;
    USE SIGNAL ;
    PORT
      LAYER M5 ;
        RECT  51.648 0 51.672 0.084 ;
    END
  END bus_wdata_o[134]
  PIN bus_wdata_o[135]
    DIRECTION OUTPUT ;
    USE SIGNAL ;
    PORT
      LAYER M5 ;
        RECT  49.248 0 49.272 0.084 ;
    END
  END bus_wdata_o[135]
  PIN bus_wdata_o[136]
    DIRECTION OUTPUT ;
    USE SIGNAL ;
    PORT
      LAYER M5 ;
        RECT  47.808 0 47.832 0.084 ;
    END
  END bus_wdata_o[136]
  PIN bus_wdata_o[137]
    DIRECTION OUTPUT ;
    USE SIGNAL ;
    PORT
      LAYER M5 ;
        RECT  47.52 0 47.544 0.084 ;
    END
  END bus_wdata_o[137]
  PIN bus_wdata_o[138]
    DIRECTION OUTPUT ;
    USE SIGNAL ;
    PORT
      LAYER M5 ;
        RECT  41.664 0 41.688 0.084 ;
    END
  END bus_wdata_o[138]
  PIN bus_wdata_o[139]
    DIRECTION OUTPUT ;
    USE SIGNAL ;
    PORT
      LAYER M5 ;
        RECT  41.952 0 41.976 0.084 ;
    END
  END bus_wdata_o[139]
  PIN bus_wdata_o[13]
    DIRECTION OUTPUT ;
    USE SIGNAL ;
    PORT
      LAYER M5 ;
        RECT  45.504 0 45.528 0.084 ;
    END
  END bus_wdata_o[13]
  PIN bus_wdata_o[140]
    DIRECTION OUTPUT ;
    USE SIGNAL ;
    PORT
      LAYER M5 ;
        RECT  46.368 0 46.392 0.084 ;
    END
  END bus_wdata_o[140]
  PIN bus_wdata_o[141]
    DIRECTION OUTPUT ;
    USE SIGNAL ;
    PORT
      LAYER M5 ;
        RECT  42.912 0 42.936 0.084 ;
    END
  END bus_wdata_o[141]
  PIN bus_wdata_o[142]
    DIRECTION OUTPUT ;
    USE SIGNAL ;
    PORT
      LAYER M5 ;
        RECT  45.12 0 45.144 0.084 ;
    END
  END bus_wdata_o[142]
  PIN bus_wdata_o[143]
    DIRECTION OUTPUT ;
    USE SIGNAL ;
    PORT
      LAYER M5 ;
        RECT  43.392 0 43.416 0.084 ;
    END
  END bus_wdata_o[143]
  PIN bus_wdata_o[144]
    DIRECTION OUTPUT ;
    USE SIGNAL ;
    PORT
      LAYER M5 ;
        RECT  43.584 0 43.608 0.084 ;
    END
  END bus_wdata_o[144]
  PIN bus_wdata_o[145]
    DIRECTION OUTPUT ;
    USE SIGNAL ;
    PORT
      LAYER M4 ;
        RECT  0 39.552 0.084 39.576 ;
    END
  END bus_wdata_o[145]
  PIN bus_wdata_o[146]
    DIRECTION OUTPUT ;
    USE SIGNAL ;
    PORT
      LAYER M4 ;
        RECT  0 40.512 0.084 40.536 ;
    END
  END bus_wdata_o[146]
  PIN bus_wdata_o[147]
    DIRECTION OUTPUT ;
    USE SIGNAL ;
    PORT
      LAYER M4 ;
        RECT  0 44.352 0.084 44.376 ;
    END
  END bus_wdata_o[147]
  PIN bus_wdata_o[148]
    DIRECTION OUTPUT ;
    USE SIGNAL ;
    PORT
      LAYER M4 ;
        RECT  0 43.776 0.084 43.8 ;
    END
  END bus_wdata_o[148]
  PIN bus_wdata_o[149]
    DIRECTION OUTPUT ;
    USE SIGNAL ;
    PORT
      LAYER M4 ;
        RECT  0 43.968 0.084 43.992 ;
    END
  END bus_wdata_o[149]
  PIN bus_wdata_o[14]
    DIRECTION OUTPUT ;
    USE SIGNAL ;
    PORT
      LAYER M5 ;
        RECT  45.312 0 45.336 0.084 ;
    END
  END bus_wdata_o[14]
  PIN bus_wdata_o[150]
    DIRECTION OUTPUT ;
    USE SIGNAL ;
    PORT
      LAYER M4 ;
        RECT  0 44.064 0.084 44.088 ;
    END
  END bus_wdata_o[150]
  PIN bus_wdata_o[151]
    DIRECTION OUTPUT ;
    USE SIGNAL ;
    PORT
      LAYER M4 ;
        RECT  0 51.168 0.084 51.192 ;
    END
  END bus_wdata_o[151]
  PIN bus_wdata_o[152]
    DIRECTION OUTPUT ;
    USE SIGNAL ;
    PORT
      LAYER M4 ;
        RECT  0 51.072 0.084 51.096 ;
    END
  END bus_wdata_o[152]
  PIN bus_wdata_o[153]
    DIRECTION OUTPUT ;
    USE SIGNAL ;
    PORT
      LAYER M4 ;
        RECT  0 51.264 0.084 51.288 ;
    END
  END bus_wdata_o[153]
  PIN bus_wdata_o[154]
    DIRECTION OUTPUT ;
    USE SIGNAL ;
    PORT
      LAYER M4 ;
        RECT  0 51.36 0.084 51.384 ;
    END
  END bus_wdata_o[154]
  PIN bus_wdata_o[155]
    DIRECTION OUTPUT ;
    USE SIGNAL ;
    PORT
      LAYER M4 ;
        RECT  0 50.88 0.084 50.904 ;
    END
  END bus_wdata_o[155]
  PIN bus_wdata_o[156]
    DIRECTION OUTPUT ;
    USE SIGNAL ;
    PORT
      LAYER M4 ;
        RECT  0 50.976 0.084 51 ;
    END
  END bus_wdata_o[156]
  PIN bus_wdata_o[157]
    DIRECTION OUTPUT ;
    USE SIGNAL ;
    PORT
      LAYER M4 ;
        RECT  0 39.264 0.084 39.288 ;
    END
  END bus_wdata_o[157]
  PIN bus_wdata_o[158]
    DIRECTION OUTPUT ;
    USE SIGNAL ;
    PORT
      LAYER M4 ;
        RECT  0 39.36 0.084 39.384 ;
    END
  END bus_wdata_o[158]
  PIN bus_wdata_o[159]
    DIRECTION OUTPUT ;
    USE SIGNAL ;
    PORT
      LAYER M5 ;
        RECT  43.776 0 43.8 0.084 ;
    END
  END bus_wdata_o[159]
  PIN bus_wdata_o[15]
    DIRECTION OUTPUT ;
    USE SIGNAL ;
    PORT
      LAYER M5 ;
        RECT  44.544 0 44.568 0.084 ;
    END
  END bus_wdata_o[15]
  PIN bus_wdata_o[160]
    DIRECTION OUTPUT ;
    USE SIGNAL ;
    PORT
      LAYER M5 ;
        RECT  53.952 0 53.976 0.084 ;
    END
  END bus_wdata_o[160]
  PIN bus_wdata_o[161]
    DIRECTION OUTPUT ;
    USE SIGNAL ;
    PORT
      LAYER M5 ;
        RECT  53.76 0 53.784 0.084 ;
    END
  END bus_wdata_o[161]
  PIN bus_wdata_o[162]
    DIRECTION OUTPUT ;
    USE SIGNAL ;
    PORT
      LAYER M5 ;
        RECT  53.472 0 53.496 0.084 ;
    END
  END bus_wdata_o[162]
  PIN bus_wdata_o[163]
    DIRECTION OUTPUT ;
    USE SIGNAL ;
    PORT
      LAYER M5 ;
        RECT  53.664 0 53.688 0.084 ;
    END
  END bus_wdata_o[163]
  PIN bus_wdata_o[164]
    DIRECTION OUTPUT ;
    USE SIGNAL ;
    PORT
      LAYER M5 ;
        RECT  54.528 0 54.552 0.084 ;
    END
  END bus_wdata_o[164]
  PIN bus_wdata_o[165]
    DIRECTION OUTPUT ;
    USE SIGNAL ;
    PORT
      LAYER M5 ;
        RECT  55.2 0 55.224 0.084 ;
    END
  END bus_wdata_o[165]
  PIN bus_wdata_o[166]
    DIRECTION OUTPUT ;
    USE SIGNAL ;
    PORT
      LAYER M5 ;
        RECT  56.064 0 56.088 0.084 ;
    END
  END bus_wdata_o[166]
  PIN bus_wdata_o[167]
    DIRECTION OUTPUT ;
    USE SIGNAL ;
    PORT
      LAYER M5 ;
        RECT  49.152 0 49.176 0.084 ;
    END
  END bus_wdata_o[167]
  PIN bus_wdata_o[168]
    DIRECTION OUTPUT ;
    USE SIGNAL ;
    PORT
      LAYER M5 ;
        RECT  48.672 0 48.696 0.084 ;
    END
  END bus_wdata_o[168]
  PIN bus_wdata_o[169]
    DIRECTION OUTPUT ;
    USE SIGNAL ;
    PORT
      LAYER M5 ;
        RECT  48.48 0 48.504 0.084 ;
    END
  END bus_wdata_o[169]
  PIN bus_wdata_o[16]
    DIRECTION OUTPUT ;
    USE SIGNAL ;
    PORT
      LAYER M5 ;
        RECT  43.872 0 43.896 0.084 ;
    END
  END bus_wdata_o[16]
  PIN bus_wdata_o[170]
    DIRECTION OUTPUT ;
    USE SIGNAL ;
    PORT
      LAYER M5 ;
        RECT  46.848 0 46.872 0.084 ;
    END
  END bus_wdata_o[170]
  PIN bus_wdata_o[171]
    DIRECTION OUTPUT ;
    USE SIGNAL ;
    PORT
      LAYER M5 ;
        RECT  46.08 0 46.104 0.084 ;
    END
  END bus_wdata_o[171]
  PIN bus_wdata_o[172]
    DIRECTION OUTPUT ;
    USE SIGNAL ;
    PORT
      LAYER M5 ;
        RECT  42.048 0 42.072 0.084 ;
    END
  END bus_wdata_o[172]
  PIN bus_wdata_o[173]
    DIRECTION OUTPUT ;
    USE SIGNAL ;
    PORT
      LAYER M5 ;
        RECT  43.008 0 43.032 0.084 ;
    END
  END bus_wdata_o[173]
  PIN bus_wdata_o[174]
    DIRECTION OUTPUT ;
    USE SIGNAL ;
    PORT
      LAYER M5 ;
        RECT  45.024 0 45.048 0.084 ;
    END
  END bus_wdata_o[174]
  PIN bus_wdata_o[175]
    DIRECTION OUTPUT ;
    USE SIGNAL ;
    PORT
      LAYER M5 ;
        RECT  44.16 0 44.184 0.084 ;
    END
  END bus_wdata_o[175]
  PIN bus_wdata_o[176]
    DIRECTION OUTPUT ;
    USE SIGNAL ;
    PORT
      LAYER M5 ;
        RECT  43.968 0 43.992 0.084 ;
    END
  END bus_wdata_o[176]
  PIN bus_wdata_o[177]
    DIRECTION OUTPUT ;
    USE SIGNAL ;
    PORT
      LAYER M4 ;
        RECT  0 40.224 0.084 40.248 ;
    END
  END bus_wdata_o[177]
  PIN bus_wdata_o[178]
    DIRECTION OUTPUT ;
    USE SIGNAL ;
    PORT
      LAYER M4 ;
        RECT  0 41.472 0.084 41.496 ;
    END
  END bus_wdata_o[178]
  PIN bus_wdata_o[179]
    DIRECTION OUTPUT ;
    USE SIGNAL ;
    PORT
      LAYER M4 ;
        RECT  0 39.168 0.084 39.192 ;
    END
  END bus_wdata_o[179]
  PIN bus_wdata_o[17]
    DIRECTION OUTPUT ;
    USE SIGNAL ;
    PORT
      LAYER M4 ;
        RECT  0 44.16 0.084 44.184 ;
    END
  END bus_wdata_o[17]
  PIN bus_wdata_o[180]
    DIRECTION OUTPUT ;
    USE SIGNAL ;
    PORT
      LAYER M4 ;
        RECT  0 41.088 0.084 41.112 ;
    END
  END bus_wdata_o[180]
  PIN bus_wdata_o[181]
    DIRECTION OUTPUT ;
    USE SIGNAL ;
    PORT
      LAYER M4 ;
        RECT  0 45.792 0.084 45.816 ;
    END
  END bus_wdata_o[181]
  PIN bus_wdata_o[182]
    DIRECTION OUTPUT ;
    USE SIGNAL ;
    PORT
      LAYER M4 ;
        RECT  0 45.312 0.084 45.336 ;
    END
  END bus_wdata_o[182]
  PIN bus_wdata_o[183]
    DIRECTION OUTPUT ;
    USE SIGNAL ;
    PORT
      LAYER M4 ;
        RECT  0 44.736 0.084 44.76 ;
    END
  END bus_wdata_o[183]
  PIN bus_wdata_o[184]
    DIRECTION OUTPUT ;
    USE SIGNAL ;
    PORT
      LAYER M4 ;
        RECT  0 42.624 0.084 42.648 ;
    END
  END bus_wdata_o[184]
  PIN bus_wdata_o[185]
    DIRECTION OUTPUT ;
    USE SIGNAL ;
    PORT
      LAYER M4 ;
        RECT  0 42.432 0.084 42.456 ;
    END
  END bus_wdata_o[185]
  PIN bus_wdata_o[186]
    DIRECTION OUTPUT ;
    USE SIGNAL ;
    PORT
      LAYER M4 ;
        RECT  0 42.528 0.084 42.552 ;
    END
  END bus_wdata_o[186]
  PIN bus_wdata_o[187]
    DIRECTION OUTPUT ;
    USE SIGNAL ;
    PORT
      LAYER M4 ;
        RECT  0 38.88 0.084 38.904 ;
    END
  END bus_wdata_o[187]
  PIN bus_wdata_o[188]
    DIRECTION OUTPUT ;
    USE SIGNAL ;
    PORT
      LAYER M4 ;
        RECT  0 38.016 0.084 38.04 ;
    END
  END bus_wdata_o[188]
  PIN bus_wdata_o[189]
    DIRECTION OUTPUT ;
    USE SIGNAL ;
    PORT
      LAYER M4 ;
        RECT  0 39.648 0.084 39.672 ;
    END
  END bus_wdata_o[189]
  PIN bus_wdata_o[18]
    DIRECTION OUTPUT ;
    USE SIGNAL ;
    PORT
      LAYER M4 ;
        RECT  0 41.952 0.084 41.976 ;
    END
  END bus_wdata_o[18]
  PIN bus_wdata_o[190]
    DIRECTION OUTPUT ;
    USE SIGNAL ;
    PORT
      LAYER M4 ;
        RECT  0 39.072 0.084 39.096 ;
    END
  END bus_wdata_o[190]
  PIN bus_wdata_o[191]
    DIRECTION OUTPUT ;
    USE SIGNAL ;
    PORT
      LAYER M5 ;
        RECT  44.064 0 44.088 0.084 ;
    END
  END bus_wdata_o[191]
  PIN bus_wdata_o[192]
    DIRECTION OUTPUT ;
    USE SIGNAL ;
    PORT
      LAYER M5 ;
        RECT  49.44 0 49.464 0.084 ;
    END
  END bus_wdata_o[192]
  PIN bus_wdata_o[193]
    DIRECTION OUTPUT ;
    USE SIGNAL ;
    PORT
      LAYER M5 ;
        RECT  50.304 0 50.328 0.084 ;
    END
  END bus_wdata_o[193]
  PIN bus_wdata_o[194]
    DIRECTION OUTPUT ;
    USE SIGNAL ;
    PORT
      LAYER M5 ;
        RECT  52.416 0 52.44 0.084 ;
    END
  END bus_wdata_o[194]
  PIN bus_wdata_o[195]
    DIRECTION OUTPUT ;
    USE SIGNAL ;
    PORT
      LAYER M5 ;
        RECT  51.552 0 51.576 0.084 ;
    END
  END bus_wdata_o[195]
  PIN bus_wdata_o[196]
    DIRECTION OUTPUT ;
    USE SIGNAL ;
    PORT
      LAYER M5 ;
        RECT  51.456 0 51.48 0.084 ;
    END
  END bus_wdata_o[196]
  PIN bus_wdata_o[197]
    DIRECTION OUTPUT ;
    USE SIGNAL ;
    PORT
      LAYER M5 ;
        RECT  50.784 0 50.808 0.084 ;
    END
  END bus_wdata_o[197]
  PIN bus_wdata_o[198]
    DIRECTION OUTPUT ;
    USE SIGNAL ;
    PORT
      LAYER M5 ;
        RECT  50.496 0 50.52 0.084 ;
    END
  END bus_wdata_o[198]
  PIN bus_wdata_o[199]
    DIRECTION OUTPUT ;
    USE SIGNAL ;
    PORT
      LAYER M5 ;
        RECT  50.016 0 50.04 0.084 ;
    END
  END bus_wdata_o[199]
  PIN bus_wdata_o[19]
    DIRECTION OUTPUT ;
    USE SIGNAL ;
    PORT
      LAYER M4 ;
        RECT  0 41.664 0.084 41.688 ;
    END
  END bus_wdata_o[19]
  PIN bus_wdata_o[1]
    DIRECTION OUTPUT ;
    USE SIGNAL ;
    PORT
      LAYER M5 ;
        RECT  55.584 0 55.608 0.084 ;
    END
  END bus_wdata_o[1]
  PIN bus_wdata_o[200]
    DIRECTION OUTPUT ;
    USE SIGNAL ;
    PORT
      LAYER M5 ;
        RECT  47.904 0 47.928 0.084 ;
    END
  END bus_wdata_o[200]
  PIN bus_wdata_o[201]
    DIRECTION OUTPUT ;
    USE SIGNAL ;
    PORT
      LAYER M5 ;
        RECT  47.712 0 47.736 0.084 ;
    END
  END bus_wdata_o[201]
  PIN bus_wdata_o[202]
    DIRECTION OUTPUT ;
    USE SIGNAL ;
    PORT
      LAYER M5 ;
        RECT  47.136 0 47.16 0.084 ;
    END
  END bus_wdata_o[202]
  PIN bus_wdata_o[203]
    DIRECTION OUTPUT ;
    USE SIGNAL ;
    PORT
      LAYER M5 ;
        RECT  45.408 0 45.432 0.084 ;
    END
  END bus_wdata_o[203]
  PIN bus_wdata_o[204]
    DIRECTION OUTPUT ;
    USE SIGNAL ;
    PORT
      LAYER M5 ;
        RECT  46.176 0 46.2 0.084 ;
    END
  END bus_wdata_o[204]
  PIN bus_wdata_o[205]
    DIRECTION OUTPUT ;
    USE SIGNAL ;
    PORT
      LAYER M5 ;
        RECT  43.2 0 43.224 0.084 ;
    END
  END bus_wdata_o[205]
  PIN bus_wdata_o[206]
    DIRECTION OUTPUT ;
    USE SIGNAL ;
    PORT
      LAYER M5 ;
        RECT  44.832 0 44.856 0.084 ;
    END
  END bus_wdata_o[206]
  PIN bus_wdata_o[207]
    DIRECTION OUTPUT ;
    USE SIGNAL ;
    PORT
      LAYER M5 ;
        RECT  43.68 0 43.704 0.084 ;
    END
  END bus_wdata_o[207]
  PIN bus_wdata_o[208]
    DIRECTION OUTPUT ;
    USE SIGNAL ;
    PORT
      LAYER M4 ;
        RECT  0 46.176 0.084 46.2 ;
    END
  END bus_wdata_o[208]
  PIN bus_wdata_o[209]
    DIRECTION OUTPUT ;
    USE SIGNAL ;
    PORT
      LAYER M4 ;
        RECT  0 43.68 0.084 43.704 ;
    END
  END bus_wdata_o[209]
  PIN bus_wdata_o[20]
    DIRECTION OUTPUT ;
    USE SIGNAL ;
    PORT
      LAYER M4 ;
        RECT  0 38.112 0.084 38.136 ;
    END
  END bus_wdata_o[20]
  PIN bus_wdata_o[210]
    DIRECTION OUTPUT ;
    USE SIGNAL ;
    PORT
      LAYER M4 ;
        RECT  0 43.392 0.084 43.416 ;
    END
  END bus_wdata_o[210]
  PIN bus_wdata_o[211]
    DIRECTION OUTPUT ;
    USE SIGNAL ;
    PORT
      LAYER M4 ;
        RECT  0 40.8 0.084 40.824 ;
    END
  END bus_wdata_o[211]
  PIN bus_wdata_o[212]
    DIRECTION OUTPUT ;
    USE SIGNAL ;
    PORT
      LAYER M4 ;
        RECT  0 41.568 0.084 41.592 ;
    END
  END bus_wdata_o[212]
  PIN bus_wdata_o[213]
    DIRECTION OUTPUT ;
    USE SIGNAL ;
    PORT
      LAYER M4 ;
        RECT  0 42.048 0.084 42.072 ;
    END
  END bus_wdata_o[213]
  PIN bus_wdata_o[214]
    DIRECTION OUTPUT ;
    USE SIGNAL ;
    PORT
      LAYER M4 ;
        RECT  0 45.984 0.084 46.008 ;
    END
  END bus_wdata_o[214]
  PIN bus_wdata_o[215]
    DIRECTION OUTPUT ;
    USE SIGNAL ;
    PORT
      LAYER M4 ;
        RECT  0 51.456 0.084 51.48 ;
    END
  END bus_wdata_o[215]
  PIN bus_wdata_o[216]
    DIRECTION OUTPUT ;
    USE SIGNAL ;
    PORT
      LAYER M4 ;
        RECT  0 51.552 0.084 51.576 ;
    END
  END bus_wdata_o[216]
  PIN bus_wdata_o[217]
    DIRECTION OUTPUT ;
    USE SIGNAL ;
    PORT
      LAYER M4 ;
        RECT  0 55.392 0.084 55.416 ;
    END
  END bus_wdata_o[217]
  PIN bus_wdata_o[218]
    DIRECTION OUTPUT ;
    USE SIGNAL ;
    PORT
      LAYER M4 ;
        RECT  0 55.872 0.084 55.896 ;
    END
  END bus_wdata_o[218]
  PIN bus_wdata_o[219]
    DIRECTION OUTPUT ;
    USE SIGNAL ;
    PORT
      LAYER M4 ;
        RECT  0 55.584 0.084 55.608 ;
    END
  END bus_wdata_o[219]
  PIN bus_wdata_o[21]
    DIRECTION OUTPUT ;
    USE SIGNAL ;
    PORT
      LAYER M4 ;
        RECT  0 42.336 0.084 42.36 ;
    END
  END bus_wdata_o[21]
  PIN bus_wdata_o[220]
    DIRECTION OUTPUT ;
    USE SIGNAL ;
    PORT
      LAYER M4 ;
        RECT  0 55.776 0.084 55.8 ;
    END
  END bus_wdata_o[220]
  PIN bus_wdata_o[221]
    DIRECTION OUTPUT ;
    USE SIGNAL ;
    PORT
      LAYER M4 ;
        RECT  0 55.68 0.084 55.704 ;
    END
  END bus_wdata_o[221]
  PIN bus_wdata_o[222]
    DIRECTION OUTPUT ;
    USE SIGNAL ;
    PORT
      LAYER M4 ;
        RECT  0 55.968 0.084 55.992 ;
    END
  END bus_wdata_o[222]
  PIN bus_wdata_o[223]
    DIRECTION OUTPUT ;
    USE SIGNAL ;
    PORT
      LAYER M4 ;
        RECT  0 52.512 0.084 52.536 ;
    END
  END bus_wdata_o[223]
  PIN bus_wdata_o[224]
    DIRECTION OUTPUT ;
    USE SIGNAL ;
    PORT
      LAYER M5 ;
        RECT  48.96 0 48.984 0.084 ;
    END
  END bus_wdata_o[224]
  PIN bus_wdata_o[225]
    DIRECTION OUTPUT ;
    USE SIGNAL ;
    PORT
      LAYER M5 ;
        RECT  53.088 0 53.112 0.084 ;
    END
  END bus_wdata_o[225]
  PIN bus_wdata_o[226]
    DIRECTION OUTPUT ;
    USE SIGNAL ;
    PORT
      LAYER M5 ;
        RECT  50.88 0 50.904 0.084 ;
    END
  END bus_wdata_o[226]
  PIN bus_wdata_o[227]
    DIRECTION OUTPUT ;
    USE SIGNAL ;
    PORT
      LAYER M5 ;
        RECT  55.488 0 55.512 0.084 ;
    END
  END bus_wdata_o[227]
  PIN bus_wdata_o[228]
    DIRECTION OUTPUT ;
    USE SIGNAL ;
    PORT
      LAYER M5 ;
        RECT  52.608 0 52.632 0.084 ;
    END
  END bus_wdata_o[228]
  PIN bus_wdata_o[229]
    DIRECTION OUTPUT ;
    USE SIGNAL ;
    PORT
      LAYER M5 ;
        RECT  53.28 0 53.304 0.084 ;
    END
  END bus_wdata_o[229]
  PIN bus_wdata_o[22]
    DIRECTION OUTPUT ;
    USE SIGNAL ;
    PORT
      LAYER M4 ;
        RECT  0 44.448 0.084 44.472 ;
    END
  END bus_wdata_o[22]
  PIN bus_wdata_o[230]
    DIRECTION OUTPUT ;
    USE SIGNAL ;
    PORT
      LAYER M5 ;
        RECT  50.688 0 50.712 0.084 ;
    END
  END bus_wdata_o[230]
  PIN bus_wdata_o[231]
    DIRECTION OUTPUT ;
    USE SIGNAL ;
    PORT
      LAYER M5 ;
        RECT  51.84 0 51.864 0.084 ;
    END
  END bus_wdata_o[231]
  PIN bus_wdata_o[232]
    DIRECTION OUTPUT ;
    USE SIGNAL ;
    PORT
      LAYER M5 ;
        RECT  48.288 0 48.312 0.084 ;
    END
  END bus_wdata_o[232]
  PIN bus_wdata_o[233]
    DIRECTION OUTPUT ;
    USE SIGNAL ;
    PORT
      LAYER M5 ;
        RECT  48 0 48.024 0.084 ;
    END
  END bus_wdata_o[233]
  PIN bus_wdata_o[234]
    DIRECTION OUTPUT ;
    USE SIGNAL ;
    PORT
      LAYER M5 ;
        RECT  47.328 0 47.352 0.084 ;
    END
  END bus_wdata_o[234]
  PIN bus_wdata_o[235]
    DIRECTION OUTPUT ;
    USE SIGNAL ;
    PORT
      LAYER M5 ;
        RECT  42.624 0 42.648 0.084 ;
    END
  END bus_wdata_o[235]
  PIN bus_wdata_o[236]
    DIRECTION OUTPUT ;
    USE SIGNAL ;
    PORT
      LAYER M5 ;
        RECT  42.432 0 42.456 0.084 ;
    END
  END bus_wdata_o[236]
  PIN bus_wdata_o[237]
    DIRECTION OUTPUT ;
    USE SIGNAL ;
    PORT
      LAYER M5 ;
        RECT  44.64 0 44.664 0.084 ;
    END
  END bus_wdata_o[237]
  PIN bus_wdata_o[238]
    DIRECTION OUTPUT ;
    USE SIGNAL ;
    PORT
      LAYER M5 ;
        RECT  43.296 0 43.32 0.084 ;
    END
  END bus_wdata_o[238]
  PIN bus_wdata_o[239]
    DIRECTION OUTPUT ;
    USE SIGNAL ;
    PORT
      LAYER M5 ;
        RECT  44.256 0 44.28 0.084 ;
    END
  END bus_wdata_o[239]
  PIN bus_wdata_o[23]
    DIRECTION OUTPUT ;
    USE SIGNAL ;
    PORT
      LAYER M4 ;
        RECT  0 42.72 0.084 42.744 ;
    END
  END bus_wdata_o[23]
  PIN bus_wdata_o[240]
    DIRECTION OUTPUT ;
    USE SIGNAL ;
    PORT
      LAYER M4 ;
        RECT  0 41.28 0.084 41.304 ;
    END
  END bus_wdata_o[240]
  PIN bus_wdata_o[241]
    DIRECTION OUTPUT ;
    USE SIGNAL ;
    PORT
      LAYER M4 ;
        RECT  0 38.208 0.084 38.232 ;
    END
  END bus_wdata_o[241]
  PIN bus_wdata_o[242]
    DIRECTION OUTPUT ;
    USE SIGNAL ;
    PORT
      LAYER M4 ;
        RECT  0 38.496 0.084 38.52 ;
    END
  END bus_wdata_o[242]
  PIN bus_wdata_o[243]
    DIRECTION OUTPUT ;
    USE SIGNAL ;
    PORT
      LAYER M4 ;
        RECT  0 38.592 0.084 38.616 ;
    END
  END bus_wdata_o[243]
  PIN bus_wdata_o[244]
    DIRECTION OUTPUT ;
    USE SIGNAL ;
    PORT
      LAYER M4 ;
        RECT  0 39.936 0.084 39.96 ;
    END
  END bus_wdata_o[244]
  PIN bus_wdata_o[245]
    DIRECTION OUTPUT ;
    USE SIGNAL ;
    PORT
      LAYER M4 ;
        RECT  0 43.488 0.084 43.512 ;
    END
  END bus_wdata_o[245]
  PIN bus_wdata_o[246]
    DIRECTION OUTPUT ;
    USE SIGNAL ;
    PORT
      LAYER M4 ;
        RECT  0 43.2 0.084 43.224 ;
    END
  END bus_wdata_o[246]
  PIN bus_wdata_o[247]
    DIRECTION OUTPUT ;
    USE SIGNAL ;
    PORT
      LAYER M4 ;
        RECT  0 52.416 0.084 52.44 ;
    END
  END bus_wdata_o[247]
  PIN bus_wdata_o[248]
    DIRECTION OUTPUT ;
    USE SIGNAL ;
    PORT
      LAYER M4 ;
        RECT  0 55.488 0.084 55.512 ;
    END
  END bus_wdata_o[248]
  PIN bus_wdata_o[249]
    DIRECTION OUTPUT ;
    USE SIGNAL ;
    PORT
      LAYER M4 ;
        RECT  0 56.064 0.084 56.088 ;
    END
  END bus_wdata_o[249]
  PIN bus_wdata_o[24]
    DIRECTION OUTPUT ;
    USE SIGNAL ;
    PORT
      LAYER M4 ;
        RECT  0 44.64 0.084 44.664 ;
    END
  END bus_wdata_o[24]
  PIN bus_wdata_o[250]
    DIRECTION OUTPUT ;
    USE SIGNAL ;
    PORT
      LAYER M4 ;
        RECT  0 56.16 0.084 56.184 ;
    END
  END bus_wdata_o[250]
  PIN bus_wdata_o[251]
    DIRECTION OUTPUT ;
    USE SIGNAL ;
    PORT
      LAYER M4 ;
        RECT  0 57.024 0.084 57.048 ;
    END
  END bus_wdata_o[251]
  PIN bus_wdata_o[252]
    DIRECTION OUTPUT ;
    USE SIGNAL ;
    PORT
      LAYER M4 ;
        RECT  0 57.12 0.084 57.144 ;
    END
  END bus_wdata_o[252]
  PIN bus_wdata_o[253]
    DIRECTION OUTPUT ;
    USE SIGNAL ;
    PORT
      LAYER M4 ;
        RECT  0 57.216 0.084 57.24 ;
    END
  END bus_wdata_o[253]
  PIN bus_wdata_o[254]
    DIRECTION OUTPUT ;
    USE SIGNAL ;
    PORT
      LAYER M4 ;
        RECT  0 56.544 0.084 56.568 ;
    END
  END bus_wdata_o[254]
  PIN bus_wdata_o[255]
    DIRECTION OUTPUT ;
    USE SIGNAL ;
    PORT
      LAYER M4 ;
        RECT  0 56.64 0.084 56.664 ;
    END
  END bus_wdata_o[255]
  PIN bus_wdata_o[256]
    DIRECTION OUTPUT ;
    USE SIGNAL ;
    PORT
      LAYER M5 ;
        RECT  103.872 0 103.896 0.084 ;
    END
  END bus_wdata_o[256]
  PIN bus_wdata_o[257]
    DIRECTION OUTPUT ;
    USE SIGNAL ;
    PORT
      LAYER M5 ;
        RECT  98.88 0 98.904 0.084 ;
    END
  END bus_wdata_o[257]
  PIN bus_wdata_o[258]
    DIRECTION OUTPUT ;
    USE SIGNAL ;
    PORT
      LAYER M5 ;
        RECT  99.072 0 99.096 0.084 ;
    END
  END bus_wdata_o[258]
  PIN bus_wdata_o[259]
    DIRECTION OUTPUT ;
    USE SIGNAL ;
    PORT
      LAYER M5 ;
        RECT  98.208 0 98.232 0.084 ;
    END
  END bus_wdata_o[259]
  PIN bus_wdata_o[25]
    DIRECTION OUTPUT ;
    USE SIGNAL ;
    PORT
      LAYER M4 ;
        RECT  0 46.08 0.084 46.104 ;
    END
  END bus_wdata_o[25]
  PIN bus_wdata_o[260]
    DIRECTION OUTPUT ;
    USE SIGNAL ;
    PORT
      LAYER M5 ;
        RECT  97.92 0 97.944 0.084 ;
    END
  END bus_wdata_o[260]
  PIN bus_wdata_o[261]
    DIRECTION OUTPUT ;
    USE SIGNAL ;
    PORT
      LAYER M5 ;
        RECT  98.112 0 98.136 0.084 ;
    END
  END bus_wdata_o[261]
  PIN bus_wdata_o[262]
    DIRECTION OUTPUT ;
    USE SIGNAL ;
    PORT
      LAYER M5 ;
        RECT  103.776 0 103.8 0.084 ;
    END
  END bus_wdata_o[262]
  PIN bus_wdata_o[263]
    DIRECTION OUTPUT ;
    USE SIGNAL ;
    PORT
      LAYER M5 ;
        RECT  100.128 0 100.152 0.084 ;
    END
  END bus_wdata_o[263]
  PIN bus_wdata_o[264]
    DIRECTION OUTPUT ;
    USE SIGNAL ;
    PORT
      LAYER M5 ;
        RECT  99.36 0 99.384 0.084 ;
    END
  END bus_wdata_o[264]
  PIN bus_wdata_o[265]
    DIRECTION OUTPUT ;
    USE SIGNAL ;
    PORT
      LAYER M5 ;
        RECT  99.936 0 99.96 0.084 ;
    END
  END bus_wdata_o[265]
  PIN bus_wdata_o[266]
    DIRECTION OUTPUT ;
    USE SIGNAL ;
    PORT
      LAYER M5 ;
        RECT  99.552 0 99.576 0.084 ;
    END
  END bus_wdata_o[266]
  PIN bus_wdata_o[267]
    DIRECTION OUTPUT ;
    USE SIGNAL ;
    PORT
      LAYER M5 ;
        RECT  99.648 0 99.672 0.084 ;
    END
  END bus_wdata_o[267]
  PIN bus_wdata_o[268]
    DIRECTION OUTPUT ;
    USE SIGNAL ;
    PORT
      LAYER M5 ;
        RECT  98.592 0 98.616 0.084 ;
    END
  END bus_wdata_o[268]
  PIN bus_wdata_o[269]
    DIRECTION OUTPUT ;
    USE SIGNAL ;
    PORT
      LAYER M5 ;
        RECT  98.016 0 98.04 0.084 ;
    END
  END bus_wdata_o[269]
  PIN bus_wdata_o[26]
    DIRECTION OUTPUT ;
    USE SIGNAL ;
    PORT
      LAYER M4 ;
        RECT  0 45.888 0.084 45.912 ;
    END
  END bus_wdata_o[26]
  PIN bus_wdata_o[270]
    DIRECTION OUTPUT ;
    USE SIGNAL ;
    PORT
      LAYER M5 ;
        RECT  97.536 0 97.56 0.084 ;
    END
  END bus_wdata_o[270]
  PIN bus_wdata_o[271]
    DIRECTION OUTPUT ;
    USE SIGNAL ;
    PORT
      LAYER M5 ;
        RECT  97.728 0 97.752 0.084 ;
    END
  END bus_wdata_o[271]
  PIN bus_wdata_o[272]
    DIRECTION OUTPUT ;
    USE SIGNAL ;
    PORT
      LAYER M5 ;
        RECT  98.976 0 99 0.084 ;
    END
  END bus_wdata_o[272]
  PIN bus_wdata_o[273]
    DIRECTION OUTPUT ;
    USE SIGNAL ;
    PORT
      LAYER M5 ;
        RECT  97.248 0 97.272 0.084 ;
    END
  END bus_wdata_o[273]
  PIN bus_wdata_o[274]
    DIRECTION OUTPUT ;
    USE SIGNAL ;
    PORT
      LAYER M5 ;
        RECT  98.688 0 98.712 0.084 ;
    END
  END bus_wdata_o[274]
  PIN bus_wdata_o[275]
    DIRECTION OUTPUT ;
    USE SIGNAL ;
    PORT
      LAYER M5 ;
        RECT  96.96 0 96.984 0.084 ;
    END
  END bus_wdata_o[275]
  PIN bus_wdata_o[276]
    DIRECTION OUTPUT ;
    USE SIGNAL ;
    PORT
      LAYER M5 ;
        RECT  96.768 0 96.792 0.084 ;
    END
  END bus_wdata_o[276]
  PIN bus_wdata_o[277]
    DIRECTION OUTPUT ;
    USE SIGNAL ;
    PORT
      LAYER M5 ;
        RECT  96.864 0 96.888 0.084 ;
    END
  END bus_wdata_o[277]
  PIN bus_wdata_o[278]
    DIRECTION OUTPUT ;
    USE SIGNAL ;
    PORT
      LAYER M5 ;
        RECT  97.152 0 97.176 0.084 ;
    END
  END bus_wdata_o[278]
  PIN bus_wdata_o[279]
    DIRECTION OUTPUT ;
    USE SIGNAL ;
    PORT
      LAYER M5 ;
        RECT  97.056 0 97.08 0.084 ;
    END
  END bus_wdata_o[279]
  PIN bus_wdata_o[27]
    DIRECTION OUTPUT ;
    USE SIGNAL ;
    PORT
      LAYER M4 ;
        RECT  0 39.84 0.084 39.864 ;
    END
  END bus_wdata_o[27]
  PIN bus_wdata_o[280]
    DIRECTION OUTPUT ;
    USE SIGNAL ;
    PORT
      LAYER M5 ;
        RECT  98.496 0 98.52 0.084 ;
    END
  END bus_wdata_o[280]
  PIN bus_wdata_o[281]
    DIRECTION OUTPUT ;
    USE SIGNAL ;
    PORT
      LAYER M5 ;
        RECT  98.4 0 98.424 0.084 ;
    END
  END bus_wdata_o[281]
  PIN bus_wdata_o[282]
    DIRECTION OUTPUT ;
    USE SIGNAL ;
    PORT
      LAYER M5 ;
        RECT  97.824 0 97.848 0.084 ;
    END
  END bus_wdata_o[282]
  PIN bus_wdata_o[283]
    DIRECTION OUTPUT ;
    USE SIGNAL ;
    PORT
      LAYER M5 ;
        RECT  97.44 0 97.464 0.084 ;
    END
  END bus_wdata_o[283]
  PIN bus_wdata_o[284]
    DIRECTION OUTPUT ;
    USE SIGNAL ;
    PORT
      LAYER M5 ;
        RECT  97.632 0 97.656 0.084 ;
    END
  END bus_wdata_o[284]
  PIN bus_wdata_o[285]
    DIRECTION OUTPUT ;
    USE SIGNAL ;
    PORT
      LAYER M5 ;
        RECT  101.184 0 101.208 0.084 ;
    END
  END bus_wdata_o[285]
  PIN bus_wdata_o[286]
    DIRECTION OUTPUT ;
    USE SIGNAL ;
    PORT
      LAYER M5 ;
        RECT  98.304 0 98.328 0.084 ;
    END
  END bus_wdata_o[286]
  PIN bus_wdata_o[287]
    DIRECTION OUTPUT ;
    USE SIGNAL ;
    PORT
      LAYER M5 ;
        RECT  97.344 0 97.368 0.084 ;
    END
  END bus_wdata_o[287]
  PIN bus_wdata_o[288]
    DIRECTION OUTPUT ;
    USE SIGNAL ;
    PORT
      LAYER M5 ;
        RECT  98.784 0 98.808 0.084 ;
    END
  END bus_wdata_o[288]
  PIN bus_wdata_o[289]
    DIRECTION OUTPUT ;
    USE SIGNAL ;
    PORT
      LAYER M5 ;
        RECT  99.168 0 99.192 0.084 ;
    END
  END bus_wdata_o[289]
  PIN bus_wdata_o[28]
    DIRECTION OUTPUT ;
    USE SIGNAL ;
    PORT
      LAYER M4 ;
        RECT  0 40.32 0.084 40.344 ;
    END
  END bus_wdata_o[28]
  PIN bus_wdata_o[290]
    DIRECTION OUTPUT ;
    USE SIGNAL ;
    PORT
      LAYER M5 ;
        RECT  99.264 0 99.288 0.084 ;
    END
  END bus_wdata_o[290]
  PIN bus_wdata_o[291]
    DIRECTION OUTPUT ;
    USE SIGNAL ;
    PORT
      LAYER M5 ;
        RECT  104.064 0 104.088 0.084 ;
    END
  END bus_wdata_o[291]
  PIN bus_wdata_o[292]
    DIRECTION OUTPUT ;
    USE SIGNAL ;
    PORT
      LAYER M5 ;
        RECT  100.608 0 100.632 0.084 ;
    END
  END bus_wdata_o[292]
  PIN bus_wdata_o[293]
    DIRECTION OUTPUT ;
    USE SIGNAL ;
    PORT
      LAYER M5 ;
        RECT  102.72 0 102.744 0.084 ;
    END
  END bus_wdata_o[293]
  PIN bus_wdata_o[294]
    DIRECTION OUTPUT ;
    USE SIGNAL ;
    PORT
      LAYER M5 ;
        RECT  100.896 0 100.92 0.084 ;
    END
  END bus_wdata_o[294]
  PIN bus_wdata_o[295]
    DIRECTION OUTPUT ;
    USE SIGNAL ;
    PORT
      LAYER M5 ;
        RECT  102.624 0 102.648 0.084 ;
    END
  END bus_wdata_o[295]
  PIN bus_wdata_o[296]
    DIRECTION OUTPUT ;
    USE SIGNAL ;
    PORT
      LAYER M5 ;
        RECT  103.008 0 103.032 0.084 ;
    END
  END bus_wdata_o[296]
  PIN bus_wdata_o[297]
    DIRECTION OUTPUT ;
    USE SIGNAL ;
    PORT
      LAYER M5 ;
        RECT  100.8 0 100.824 0.084 ;
    END
  END bus_wdata_o[297]
  PIN bus_wdata_o[298]
    DIRECTION OUTPUT ;
    USE SIGNAL ;
    PORT
      LAYER M5 ;
        RECT  102.336 0 102.36 0.084 ;
    END
  END bus_wdata_o[298]
  PIN bus_wdata_o[299]
    DIRECTION OUTPUT ;
    USE SIGNAL ;
    PORT
      LAYER M5 ;
        RECT  101.76 0 101.784 0.084 ;
    END
  END bus_wdata_o[299]
  PIN bus_wdata_o[29]
    DIRECTION OUTPUT ;
    USE SIGNAL ;
    PORT
      LAYER M4 ;
        RECT  0 39.744 0.084 39.768 ;
    END
  END bus_wdata_o[29]
  PIN bus_wdata_o[2]
    DIRECTION OUTPUT ;
    USE SIGNAL ;
    PORT
      LAYER M5 ;
        RECT  54.336 0 54.36 0.084 ;
    END
  END bus_wdata_o[2]
  PIN bus_wdata_o[300]
    DIRECTION OUTPUT ;
    USE SIGNAL ;
    PORT
      LAYER M5 ;
        RECT  103.104 0 103.128 0.084 ;
    END
  END bus_wdata_o[300]
  PIN bus_wdata_o[301]
    DIRECTION OUTPUT ;
    USE SIGNAL ;
    PORT
      LAYER M5 ;
        RECT  102.912 0 102.936 0.084 ;
    END
  END bus_wdata_o[301]
  PIN bus_wdata_o[302]
    DIRECTION OUTPUT ;
    USE SIGNAL ;
    PORT
      LAYER M5 ;
        RECT  104.544 0 104.568 0.084 ;
    END
  END bus_wdata_o[302]
  PIN bus_wdata_o[303]
    DIRECTION OUTPUT ;
    USE SIGNAL ;
    PORT
      LAYER M5 ;
        RECT  104.16 0 104.184 0.084 ;
    END
  END bus_wdata_o[303]
  PIN bus_wdata_o[304]
    DIRECTION OUTPUT ;
    USE SIGNAL ;
    PORT
      LAYER M5 ;
        RECT  104.832 0 104.856 0.084 ;
    END
  END bus_wdata_o[304]
  PIN bus_wdata_o[305]
    DIRECTION OUTPUT ;
    USE SIGNAL ;
    PORT
      LAYER M5 ;
        RECT  108.864 0 108.888 0.084 ;
    END
  END bus_wdata_o[305]
  PIN bus_wdata_o[306]
    DIRECTION OUTPUT ;
    USE SIGNAL ;
    PORT
      LAYER M5 ;
        RECT  104.448 0 104.472 0.084 ;
    END
  END bus_wdata_o[306]
  PIN bus_wdata_o[307]
    DIRECTION OUTPUT ;
    USE SIGNAL ;
    PORT
      LAYER M5 ;
        RECT  104.64 0 104.664 0.084 ;
    END
  END bus_wdata_o[307]
  PIN bus_wdata_o[308]
    DIRECTION OUTPUT ;
    USE SIGNAL ;
    PORT
      LAYER M5 ;
        RECT  102.528 0 102.552 0.084 ;
    END
  END bus_wdata_o[308]
  PIN bus_wdata_o[309]
    DIRECTION OUTPUT ;
    USE SIGNAL ;
    PORT
      LAYER M5 ;
        RECT  101.952 0 101.976 0.084 ;
    END
  END bus_wdata_o[309]
  PIN bus_wdata_o[30]
    DIRECTION OUTPUT ;
    USE SIGNAL ;
    PORT
      LAYER M4 ;
        RECT  0 38.784 0.084 38.808 ;
    END
  END bus_wdata_o[30]
  PIN bus_wdata_o[310]
    DIRECTION OUTPUT ;
    USE SIGNAL ;
    PORT
      LAYER M5 ;
        RECT  101.088 0 101.112 0.084 ;
    END
  END bus_wdata_o[310]
  PIN bus_wdata_o[311]
    DIRECTION OUTPUT ;
    USE SIGNAL ;
    PORT
      LAYER M5 ;
        RECT  101.568 0 101.592 0.084 ;
    END
  END bus_wdata_o[311]
  PIN bus_wdata_o[312]
    DIRECTION OUTPUT ;
    USE SIGNAL ;
    PORT
      LAYER M5 ;
        RECT  102.144 0 102.168 0.084 ;
    END
  END bus_wdata_o[312]
  PIN bus_wdata_o[313]
    DIRECTION OUTPUT ;
    USE SIGNAL ;
    PORT
      LAYER M5 ;
        RECT  100.704 0 100.728 0.084 ;
    END
  END bus_wdata_o[313]
  PIN bus_wdata_o[314]
    DIRECTION OUTPUT ;
    USE SIGNAL ;
    PORT
      LAYER M5 ;
        RECT  101.28 0 101.304 0.084 ;
    END
  END bus_wdata_o[314]
  PIN bus_wdata_o[315]
    DIRECTION OUTPUT ;
    USE SIGNAL ;
    PORT
      LAYER M5 ;
        RECT  102.432 0 102.456 0.084 ;
    END
  END bus_wdata_o[315]
  PIN bus_wdata_o[316]
    DIRECTION OUTPUT ;
    USE SIGNAL ;
    PORT
      LAYER M5 ;
        RECT  100.512 0 100.536 0.084 ;
    END
  END bus_wdata_o[316]
  PIN bus_wdata_o[317]
    DIRECTION OUTPUT ;
    USE SIGNAL ;
    PORT
      LAYER M5 ;
        RECT  103.968 0 103.992 0.084 ;
    END
  END bus_wdata_o[317]
  PIN bus_wdata_o[318]
    DIRECTION OUTPUT ;
    USE SIGNAL ;
    PORT
      LAYER M5 ;
        RECT  103.2 0 103.224 0.084 ;
    END
  END bus_wdata_o[318]
  PIN bus_wdata_o[319]
    DIRECTION OUTPUT ;
    USE SIGNAL ;
    PORT
      LAYER M5 ;
        RECT  100.416 0 100.44 0.084 ;
    END
  END bus_wdata_o[319]
  PIN bus_wdata_o[31]
    DIRECTION OUTPUT ;
    USE SIGNAL ;
    PORT
      LAYER M5 ;
        RECT  54.72 0 54.744 0.084 ;
    END
  END bus_wdata_o[31]
  PIN bus_wdata_o[320]
    DIRECTION OUTPUT ;
    USE SIGNAL ;
    PORT
      LAYER M5 ;
        RECT  100.224 0 100.248 0.084 ;
    END
  END bus_wdata_o[320]
  PIN bus_wdata_o[321]
    DIRECTION OUTPUT ;
    USE SIGNAL ;
    PORT
      LAYER M5 ;
        RECT  100.32 0 100.344 0.084 ;
    END
  END bus_wdata_o[321]
  PIN bus_wdata_o[322]
    DIRECTION OUTPUT ;
    USE SIGNAL ;
    PORT
      LAYER M5 ;
        RECT  103.68 0 103.704 0.084 ;
    END
  END bus_wdata_o[322]
  PIN bus_wdata_o[323]
    DIRECTION OUTPUT ;
    USE SIGNAL ;
    PORT
      LAYER M5 ;
        RECT  101.664 0 101.688 0.084 ;
    END
  END bus_wdata_o[323]
  PIN bus_wdata_o[324]
    DIRECTION OUTPUT ;
    USE SIGNAL ;
    PORT
      LAYER M5 ;
        RECT  102.048 0 102.072 0.084 ;
    END
  END bus_wdata_o[324]
  PIN bus_wdata_o[325]
    DIRECTION OUTPUT ;
    USE SIGNAL ;
    PORT
      LAYER M5 ;
        RECT  103.392 0 103.416 0.084 ;
    END
  END bus_wdata_o[325]
  PIN bus_wdata_o[326]
    DIRECTION OUTPUT ;
    USE SIGNAL ;
    PORT
      LAYER M5 ;
        RECT  108.096 0 108.12 0.084 ;
    END
  END bus_wdata_o[326]
  PIN bus_wdata_o[327]
    DIRECTION OUTPUT ;
    USE SIGNAL ;
    PORT
      LAYER M5 ;
        RECT  99.456 0 99.48 0.084 ;
    END
  END bus_wdata_o[327]
  PIN bus_wdata_o[328]
    DIRECTION OUTPUT ;
    USE SIGNAL ;
    PORT
      LAYER M5 ;
        RECT  99.744 0 99.768 0.084 ;
    END
  END bus_wdata_o[328]
  PIN bus_wdata_o[329]
    DIRECTION OUTPUT ;
    USE SIGNAL ;
    PORT
      LAYER M5 ;
        RECT  103.296 0 103.32 0.084 ;
    END
  END bus_wdata_o[329]
  PIN bus_wdata_o[32]
    DIRECTION OUTPUT ;
    USE SIGNAL ;
    PORT
      LAYER M5 ;
        RECT  50.112 0 50.136 0.084 ;
    END
  END bus_wdata_o[32]
  PIN bus_wdata_o[330]
    DIRECTION OUTPUT ;
    USE SIGNAL ;
    PORT
      LAYER M5 ;
        RECT  103.584 0 103.608 0.084 ;
    END
  END bus_wdata_o[330]
  PIN bus_wdata_o[331]
    DIRECTION OUTPUT ;
    USE SIGNAL ;
    PORT
      LAYER M5 ;
        RECT  101.856 0 101.88 0.084 ;
    END
  END bus_wdata_o[331]
  PIN bus_wdata_o[332]
    DIRECTION OUTPUT ;
    USE SIGNAL ;
    PORT
      LAYER M5 ;
        RECT  108.576 0 108.6 0.084 ;
    END
  END bus_wdata_o[332]
  PIN bus_wdata_o[333]
    DIRECTION OUTPUT ;
    USE SIGNAL ;
    PORT
      LAYER M5 ;
        RECT  107.904 0 107.928 0.084 ;
    END
  END bus_wdata_o[333]
  PIN bus_wdata_o[334]
    DIRECTION OUTPUT ;
    USE SIGNAL ;
    PORT
      LAYER M5 ;
        RECT  108.672 0 108.696 0.084 ;
    END
  END bus_wdata_o[334]
  PIN bus_wdata_o[335]
    DIRECTION OUTPUT ;
    USE SIGNAL ;
    PORT
      LAYER M5 ;
        RECT  109.248 0 109.272 0.084 ;
    END
  END bus_wdata_o[335]
  PIN bus_wdata_o[336]
    DIRECTION OUTPUT ;
    USE SIGNAL ;
    PORT
      LAYER M5 ;
        RECT  109.056 0 109.08 0.084 ;
    END
  END bus_wdata_o[336]
  PIN bus_wdata_o[337]
    DIRECTION OUTPUT ;
    USE SIGNAL ;
    PORT
      LAYER M5 ;
        RECT  107.136 0 107.16 0.084 ;
    END
  END bus_wdata_o[337]
  PIN bus_wdata_o[338]
    DIRECTION OUTPUT ;
    USE SIGNAL ;
    PORT
      LAYER M5 ;
        RECT  107.808 0 107.832 0.084 ;
    END
  END bus_wdata_o[338]
  PIN bus_wdata_o[339]
    DIRECTION OUTPUT ;
    USE SIGNAL ;
    PORT
      LAYER M5 ;
        RECT  107.232 0 107.256 0.084 ;
    END
  END bus_wdata_o[339]
  PIN bus_wdata_o[33]
    DIRECTION OUTPUT ;
    USE SIGNAL ;
    PORT
      LAYER M5 ;
        RECT  56.16 0 56.184 0.084 ;
    END
  END bus_wdata_o[33]
  PIN bus_wdata_o[340]
    DIRECTION OUTPUT ;
    USE SIGNAL ;
    PORT
      LAYER M5 ;
        RECT  106.56 0 106.584 0.084 ;
    END
  END bus_wdata_o[340]
  PIN bus_wdata_o[341]
    DIRECTION OUTPUT ;
    USE SIGNAL ;
    PORT
      LAYER M5 ;
        RECT  108.48 0 108.504 0.084 ;
    END
  END bus_wdata_o[341]
  PIN bus_wdata_o[342]
    DIRECTION OUTPUT ;
    USE SIGNAL ;
    PORT
      LAYER M5 ;
        RECT  106.368 0 106.392 0.084 ;
    END
  END bus_wdata_o[342]
  PIN bus_wdata_o[343]
    DIRECTION OUTPUT ;
    USE SIGNAL ;
    PORT
      LAYER M5 ;
        RECT  108.288 0 108.312 0.084 ;
    END
  END bus_wdata_o[343]
  PIN bus_wdata_o[344]
    DIRECTION OUTPUT ;
    USE SIGNAL ;
    PORT
      LAYER M5 ;
        RECT  106.848 0 106.872 0.084 ;
    END
  END bus_wdata_o[344]
  PIN bus_wdata_o[345]
    DIRECTION OUTPUT ;
    USE SIGNAL ;
    PORT
      LAYER M5 ;
        RECT  106.944 0 106.968 0.084 ;
    END
  END bus_wdata_o[345]
  PIN bus_wdata_o[346]
    DIRECTION OUTPUT ;
    USE SIGNAL ;
    PORT
      LAYER M5 ;
        RECT  107.04 0 107.064 0.084 ;
    END
  END bus_wdata_o[346]
  PIN bus_wdata_o[347]
    DIRECTION OUTPUT ;
    USE SIGNAL ;
    PORT
      LAYER M5 ;
        RECT  108.192 0 108.216 0.084 ;
    END
  END bus_wdata_o[347]
  PIN bus_wdata_o[348]
    DIRECTION OUTPUT ;
    USE SIGNAL ;
    PORT
      LAYER M5 ;
        RECT  107.712 0 107.736 0.084 ;
    END
  END bus_wdata_o[348]
  PIN bus_wdata_o[349]
    DIRECTION OUTPUT ;
    USE SIGNAL ;
    PORT
      LAYER M5 ;
        RECT  106.176 0 106.2 0.084 ;
    END
  END bus_wdata_o[349]
  PIN bus_wdata_o[34]
    DIRECTION OUTPUT ;
    USE SIGNAL ;
    PORT
      LAYER M5 ;
        RECT  51.744 0 51.768 0.084 ;
    END
  END bus_wdata_o[34]
  PIN bus_wdata_o[350]
    DIRECTION OUTPUT ;
    USE SIGNAL ;
    PORT
      LAYER M5 ;
        RECT  106.464 0 106.488 0.084 ;
    END
  END bus_wdata_o[350]
  PIN bus_wdata_o[351]
    DIRECTION OUTPUT ;
    USE SIGNAL ;
    PORT
      LAYER M5 ;
        RECT  108 0 108.024 0.084 ;
    END
  END bus_wdata_o[351]
  PIN bus_wdata_o[352]
    DIRECTION OUTPUT ;
    USE SIGNAL ;
    PORT
      LAYER M5 ;
        RECT  105.504 0 105.528 0.084 ;
    END
  END bus_wdata_o[352]
  PIN bus_wdata_o[353]
    DIRECTION OUTPUT ;
    USE SIGNAL ;
    PORT
      LAYER M5 ;
        RECT  105.792 0 105.816 0.084 ;
    END
  END bus_wdata_o[353]
  PIN bus_wdata_o[354]
    DIRECTION OUTPUT ;
    USE SIGNAL ;
    PORT
      LAYER M5 ;
        RECT  108.768 0 108.792 0.084 ;
    END
  END bus_wdata_o[354]
  PIN bus_wdata_o[355]
    DIRECTION OUTPUT ;
    USE SIGNAL ;
    PORT
      LAYER M5 ;
        RECT  109.344 0 109.368 0.084 ;
    END
  END bus_wdata_o[355]
  PIN bus_wdata_o[356]
    DIRECTION OUTPUT ;
    USE SIGNAL ;
    PORT
      LAYER M5 ;
        RECT  106.08 0 106.104 0.084 ;
    END
  END bus_wdata_o[356]
  PIN bus_wdata_o[357]
    DIRECTION OUTPUT ;
    USE SIGNAL ;
    PORT
      LAYER M5 ;
        RECT  109.44 0 109.464 0.084 ;
    END
  END bus_wdata_o[357]
  PIN bus_wdata_o[358]
    DIRECTION OUTPUT ;
    USE SIGNAL ;
    PORT
      LAYER M5 ;
        RECT  105.984 0 106.008 0.084 ;
    END
  END bus_wdata_o[358]
  PIN bus_wdata_o[359]
    DIRECTION OUTPUT ;
    USE SIGNAL ;
    PORT
      LAYER M5 ;
        RECT  107.616 0 107.64 0.084 ;
    END
  END bus_wdata_o[359]
  PIN bus_wdata_o[35]
    DIRECTION OUTPUT ;
    USE SIGNAL ;
    PORT
      LAYER M5 ;
        RECT  55.104 0 55.128 0.084 ;
    END
  END bus_wdata_o[35]
  PIN bus_wdata_o[360]
    DIRECTION OUTPUT ;
    USE SIGNAL ;
    PORT
      LAYER M5 ;
        RECT  106.272 0 106.296 0.084 ;
    END
  END bus_wdata_o[360]
  PIN bus_wdata_o[361]
    DIRECTION OUTPUT ;
    USE SIGNAL ;
    PORT
      LAYER M5 ;
        RECT  105.6 0 105.624 0.084 ;
    END
  END bus_wdata_o[361]
  PIN bus_wdata_o[362]
    DIRECTION OUTPUT ;
    USE SIGNAL ;
    PORT
      LAYER M5 ;
        RECT  108.384 0 108.408 0.084 ;
    END
  END bus_wdata_o[362]
  PIN bus_wdata_o[363]
    DIRECTION OUTPUT ;
    USE SIGNAL ;
    PORT
      LAYER M5 ;
        RECT  108.96 0 108.984 0.084 ;
    END
  END bus_wdata_o[363]
  PIN bus_wdata_o[364]
    DIRECTION OUTPUT ;
    USE SIGNAL ;
    PORT
      LAYER M5 ;
        RECT  107.424 0 107.448 0.084 ;
    END
  END bus_wdata_o[364]
  PIN bus_wdata_o[365]
    DIRECTION OUTPUT ;
    USE SIGNAL ;
    PORT
      LAYER M5 ;
        RECT  106.752 0 106.776 0.084 ;
    END
  END bus_wdata_o[365]
  PIN bus_wdata_o[366]
    DIRECTION OUTPUT ;
    USE SIGNAL ;
    PORT
      LAYER M5 ;
        RECT  107.328 0 107.352 0.084 ;
    END
  END bus_wdata_o[366]
  PIN bus_wdata_o[367]
    DIRECTION OUTPUT ;
    USE SIGNAL ;
    PORT
      LAYER M5 ;
        RECT  107.52 0 107.544 0.084 ;
    END
  END bus_wdata_o[367]
  PIN bus_wdata_o[368]
    DIRECTION OUTPUT ;
    USE SIGNAL ;
    PORT
      LAYER M5 ;
        RECT  106.656 0 106.68 0.084 ;
    END
  END bus_wdata_o[368]
  PIN bus_wdata_o[369]
    DIRECTION OUTPUT ;
    USE SIGNAL ;
    PORT
      LAYER M5 ;
        RECT  105.216 0 105.24 0.084 ;
    END
  END bus_wdata_o[369]
  PIN bus_wdata_o[36]
    DIRECTION OUTPUT ;
    USE SIGNAL ;
    PORT
      LAYER M5 ;
        RECT  55.872 0 55.896 0.084 ;
    END
  END bus_wdata_o[36]
  PIN bus_wdata_o[370]
    DIRECTION OUTPUT ;
    USE SIGNAL ;
    PORT
      LAYER M5 ;
        RECT  105.024 0 105.048 0.084 ;
    END
  END bus_wdata_o[370]
  PIN bus_wdata_o[371]
    DIRECTION OUTPUT ;
    USE SIGNAL ;
    PORT
      LAYER M5 ;
        RECT  105.408 0 105.432 0.084 ;
    END
  END bus_wdata_o[371]
  PIN bus_wdata_o[372]
    DIRECTION OUTPUT ;
    USE SIGNAL ;
    PORT
      LAYER M5 ;
        RECT  104.736 0 104.76 0.084 ;
    END
  END bus_wdata_o[372]
  PIN bus_wdata_o[373]
    DIRECTION OUTPUT ;
    USE SIGNAL ;
    PORT
      LAYER M5 ;
        RECT  102.24 0 102.264 0.084 ;
    END
  END bus_wdata_o[373]
  PIN bus_wdata_o[374]
    DIRECTION OUTPUT ;
    USE SIGNAL ;
    PORT
      LAYER M4 ;
        RECT  144.916 40.608 145 40.632 ;
    END
  END bus_wdata_o[374]
  PIN bus_wdata_o[375]
    DIRECTION OUTPUT ;
    USE SIGNAL ;
    PORT
      LAYER M4 ;
        RECT  144.916 44.16 145 44.184 ;
    END
  END bus_wdata_o[375]
  PIN bus_wdata_o[376]
    DIRECTION OUTPUT ;
    USE SIGNAL ;
    PORT
      LAYER M5 ;
        RECT  101.472 0 101.496 0.084 ;
    END
  END bus_wdata_o[376]
  PIN bus_wdata_o[377]
    DIRECTION OUTPUT ;
    USE SIGNAL ;
    PORT
      LAYER M5 ;
        RECT  99.84 0 99.864 0.084 ;
    END
  END bus_wdata_o[377]
  PIN bus_wdata_o[378]
    DIRECTION OUTPUT ;
    USE SIGNAL ;
    PORT
      LAYER M5 ;
        RECT  100.032 0 100.056 0.084 ;
    END
  END bus_wdata_o[378]
  PIN bus_wdata_o[379]
    DIRECTION OUTPUT ;
    USE SIGNAL ;
    PORT
      LAYER M5 ;
        RECT  104.256 0 104.28 0.084 ;
    END
  END bus_wdata_o[379]
  PIN bus_wdata_o[37]
    DIRECTION OUTPUT ;
    USE SIGNAL ;
    PORT
      LAYER M5 ;
        RECT  55.968 0 55.992 0.084 ;
    END
  END bus_wdata_o[37]
  PIN bus_wdata_o[380]
    DIRECTION OUTPUT ;
    USE SIGNAL ;
    PORT
      LAYER M5 ;
        RECT  101.376 0 101.4 0.084 ;
    END
  END bus_wdata_o[380]
  PIN bus_wdata_o[381]
    DIRECTION OUTPUT ;
    USE SIGNAL ;
    PORT
      LAYER M5 ;
        RECT  100.992 0 101.016 0.084 ;
    END
  END bus_wdata_o[381]
  PIN bus_wdata_o[382]
    DIRECTION OUTPUT ;
    USE SIGNAL ;
    PORT
      LAYER M5 ;
        RECT  102.816 0 102.84 0.084 ;
    END
  END bus_wdata_o[382]
  PIN bus_wdata_o[383]
    DIRECTION OUTPUT ;
    USE SIGNAL ;
    PORT
      LAYER M4 ;
        RECT  144.916 44.736 145 44.76 ;
    END
  END bus_wdata_o[383]
  PIN bus_wdata_o[384]
    DIRECTION OUTPUT ;
    USE SIGNAL ;
    PORT
      LAYER M4 ;
        RECT  144.916 43.968 145 43.992 ;
    END
  END bus_wdata_o[384]
  PIN bus_wdata_o[385]
    DIRECTION OUTPUT ;
    USE SIGNAL ;
    PORT
      LAYER M4 ;
        RECT  144.916 45.312 145 45.336 ;
    END
  END bus_wdata_o[385]
  PIN bus_wdata_o[386]
    DIRECTION OUTPUT ;
    USE SIGNAL ;
    PORT
      LAYER M5 ;
        RECT  103.488 0 103.512 0.084 ;
    END
  END bus_wdata_o[386]
  PIN bus_wdata_o[387]
    DIRECTION OUTPUT ;
    USE SIGNAL ;
    PORT
      LAYER M4 ;
        RECT  144.916 45.12 145 45.144 ;
    END
  END bus_wdata_o[387]
  PIN bus_wdata_o[388]
    DIRECTION OUTPUT ;
    USE SIGNAL ;
    PORT
      LAYER M4 ;
        RECT  144.916 44.256 145 44.28 ;
    END
  END bus_wdata_o[388]
  PIN bus_wdata_o[389]
    DIRECTION OUTPUT ;
    USE SIGNAL ;
    PORT
      LAYER M4 ;
        RECT  144.916 41.184 145 41.208 ;
    END
  END bus_wdata_o[389]
  PIN bus_wdata_o[38]
    DIRECTION OUTPUT ;
    USE SIGNAL ;
    PORT
      LAYER M5 ;
        RECT  55.008 0 55.032 0.084 ;
    END
  END bus_wdata_o[38]
  PIN bus_wdata_o[390]
    DIRECTION OUTPUT ;
    USE SIGNAL ;
    PORT
      LAYER M5 ;
        RECT  104.928 0 104.952 0.084 ;
    END
  END bus_wdata_o[390]
  PIN bus_wdata_o[391]
    DIRECTION OUTPUT ;
    USE SIGNAL ;
    PORT
      LAYER M4 ;
        RECT  144.916 44.832 145 44.856 ;
    END
  END bus_wdata_o[391]
  PIN bus_wdata_o[392]
    DIRECTION OUTPUT ;
    USE SIGNAL ;
    PORT
      LAYER M4 ;
        RECT  144.916 50.976 145 51 ;
    END
  END bus_wdata_o[392]
  PIN bus_wdata_o[393]
    DIRECTION OUTPUT ;
    USE SIGNAL ;
    PORT
      LAYER M4 ;
        RECT  144.916 50.4 145 50.424 ;
    END
  END bus_wdata_o[393]
  PIN bus_wdata_o[394]
    DIRECTION OUTPUT ;
    USE SIGNAL ;
    PORT
      LAYER M4 ;
        RECT  144.916 49.44 145 49.464 ;
    END
  END bus_wdata_o[394]
  PIN bus_wdata_o[395]
    DIRECTION OUTPUT ;
    USE SIGNAL ;
    PORT
      LAYER M4 ;
        RECT  144.916 49.056 145 49.08 ;
    END
  END bus_wdata_o[395]
  PIN bus_wdata_o[396]
    DIRECTION OUTPUT ;
    USE SIGNAL ;
    PORT
      LAYER M4 ;
        RECT  144.916 52.32 145 52.344 ;
    END
  END bus_wdata_o[396]
  PIN bus_wdata_o[397]
    DIRECTION OUTPUT ;
    USE SIGNAL ;
    PORT
      LAYER M4 ;
        RECT  144.916 51.456 145 51.48 ;
    END
  END bus_wdata_o[397]
  PIN bus_wdata_o[398]
    DIRECTION OUTPUT ;
    USE SIGNAL ;
    PORT
      LAYER M4 ;
        RECT  144.916 49.632 145 49.656 ;
    END
  END bus_wdata_o[398]
  PIN bus_wdata_o[399]
    DIRECTION OUTPUT ;
    USE SIGNAL ;
    PORT
      LAYER M4 ;
        RECT  144.916 52.032 145 52.056 ;
    END
  END bus_wdata_o[399]
  PIN bus_wdata_o[39]
    DIRECTION OUTPUT ;
    USE SIGNAL ;
    PORT
      LAYER M5 ;
        RECT  54.048 0 54.072 0.084 ;
    END
  END bus_wdata_o[39]
  PIN bus_wdata_o[3]
    DIRECTION OUTPUT ;
    USE SIGNAL ;
    PORT
      LAYER M5 ;
        RECT  54.624 0 54.648 0.084 ;
    END
  END bus_wdata_o[3]
  PIN bus_wdata_o[400]
    DIRECTION OUTPUT ;
    USE SIGNAL ;
    PORT
      LAYER M4 ;
        RECT  144.916 49.536 145 49.56 ;
    END
  END bus_wdata_o[400]
  PIN bus_wdata_o[401]
    DIRECTION OUTPUT ;
    USE SIGNAL ;
    PORT
      LAYER M4 ;
        RECT  144.916 51.936 145 51.96 ;
    END
  END bus_wdata_o[401]
  PIN bus_wdata_o[402]
    DIRECTION OUTPUT ;
    USE SIGNAL ;
    PORT
      LAYER M4 ;
        RECT  144.916 54.912 145 54.936 ;
    END
  END bus_wdata_o[402]
  PIN bus_wdata_o[403]
    DIRECTION OUTPUT ;
    USE SIGNAL ;
    PORT
      LAYER M4 ;
        RECT  144.916 56.928 145 56.952 ;
    END
  END bus_wdata_o[403]
  PIN bus_wdata_o[404]
    DIRECTION OUTPUT ;
    USE SIGNAL ;
    PORT
      LAYER M4 ;
        RECT  144.916 55.968 145 55.992 ;
    END
  END bus_wdata_o[404]
  PIN bus_wdata_o[405]
    DIRECTION OUTPUT ;
    USE SIGNAL ;
    PORT
      LAYER M4 ;
        RECT  144.916 52.704 145 52.728 ;
    END
  END bus_wdata_o[405]
  PIN bus_wdata_o[406]
    DIRECTION OUTPUT ;
    USE SIGNAL ;
    PORT
      LAYER M4 ;
        RECT  144.916 53.664 145 53.688 ;
    END
  END bus_wdata_o[406]
  PIN bus_wdata_o[407]
    DIRECTION OUTPUT ;
    USE SIGNAL ;
    PORT
      LAYER M4 ;
        RECT  144.916 53.28 145 53.304 ;
    END
  END bus_wdata_o[407]
  PIN bus_wdata_o[408]
    DIRECTION OUTPUT ;
    USE SIGNAL ;
    PORT
      LAYER M4 ;
        RECT  144.916 53.952 145 53.976 ;
    END
  END bus_wdata_o[408]
  PIN bus_wdata_o[409]
    DIRECTION OUTPUT ;
    USE SIGNAL ;
    PORT
      LAYER M4 ;
        RECT  144.916 54.336 145 54.36 ;
    END
  END bus_wdata_o[409]
  PIN bus_wdata_o[40]
    DIRECTION OUTPUT ;
    USE SIGNAL ;
    PORT
      LAYER M5 ;
        RECT  50.4 0 50.424 0.084 ;
    END
  END bus_wdata_o[40]
  PIN bus_wdata_o[410]
    DIRECTION OUTPUT ;
    USE SIGNAL ;
    PORT
      LAYER M4 ;
        RECT  144.916 51.84 145 51.864 ;
    END
  END bus_wdata_o[410]
  PIN bus_wdata_o[411]
    DIRECTION OUTPUT ;
    USE SIGNAL ;
    PORT
      LAYER M4 ;
        RECT  144.916 51.36 145 51.384 ;
    END
  END bus_wdata_o[411]
  PIN bus_wdata_o[412]
    DIRECTION OUTPUT ;
    USE SIGNAL ;
    PORT
      LAYER M4 ;
        RECT  144.916 49.344 145 49.368 ;
    END
  END bus_wdata_o[412]
  PIN bus_wdata_o[413]
    DIRECTION OUTPUT ;
    USE SIGNAL ;
    PORT
      LAYER M4 ;
        RECT  144.916 48.768 145 48.792 ;
    END
  END bus_wdata_o[413]
  PIN bus_wdata_o[414]
    DIRECTION OUTPUT ;
    USE SIGNAL ;
    PORT
      LAYER M4 ;
        RECT  144.916 50.208 145 50.232 ;
    END
  END bus_wdata_o[414]
  PIN bus_wdata_o[415]
    DIRECTION OUTPUT ;
    USE SIGNAL ;
    PORT
      LAYER M4 ;
        RECT  144.916 48.48 145 48.504 ;
    END
  END bus_wdata_o[415]
  PIN bus_wdata_o[416]
    DIRECTION OUTPUT ;
    USE SIGNAL ;
    PORT
      LAYER M4 ;
        RECT  144.916 49.92 145 49.944 ;
    END
  END bus_wdata_o[416]
  PIN bus_wdata_o[417]
    DIRECTION OUTPUT ;
    USE SIGNAL ;
    PORT
      LAYER M4 ;
        RECT  144.916 48.864 145 48.888 ;
    END
  END bus_wdata_o[417]
  PIN bus_wdata_o[418]
    DIRECTION OUTPUT ;
    USE SIGNAL ;
    PORT
      LAYER M4 ;
        RECT  144.916 50.304 145 50.328 ;
    END
  END bus_wdata_o[418]
  PIN bus_wdata_o[419]
    DIRECTION OUTPUT ;
    USE SIGNAL ;
    PORT
      LAYER M4 ;
        RECT  144.916 49.248 145 49.272 ;
    END
  END bus_wdata_o[419]
  PIN bus_wdata_o[41]
    DIRECTION OUTPUT ;
    USE SIGNAL ;
    PORT
      LAYER M5 ;
        RECT  48.864 0 48.888 0.084 ;
    END
  END bus_wdata_o[41]
  PIN bus_wdata_o[420]
    DIRECTION OUTPUT ;
    USE SIGNAL ;
    PORT
      LAYER M4 ;
        RECT  144.916 49.728 145 49.752 ;
    END
  END bus_wdata_o[420]
  PIN bus_wdata_o[421]
    DIRECTION OUTPUT ;
    USE SIGNAL ;
    PORT
      LAYER M4 ;
        RECT  144.916 48.576 145 48.6 ;
    END
  END bus_wdata_o[421]
  PIN bus_wdata_o[422]
    DIRECTION OUTPUT ;
    USE SIGNAL ;
    PORT
      LAYER M4 ;
        RECT  144.916 46.56 145 46.584 ;
    END
  END bus_wdata_o[422]
  PIN bus_wdata_o[423]
    DIRECTION OUTPUT ;
    USE SIGNAL ;
    PORT
      LAYER M4 ;
        RECT  144.916 45.696 145 45.72 ;
    END
  END bus_wdata_o[423]
  PIN bus_wdata_o[424]
    DIRECTION OUTPUT ;
    USE SIGNAL ;
    PORT
      LAYER M4 ;
        RECT  144.916 47.424 145 47.448 ;
    END
  END bus_wdata_o[424]
  PIN bus_wdata_o[425]
    DIRECTION OUTPUT ;
    USE SIGNAL ;
    PORT
      LAYER M4 ;
        RECT  144.916 43.776 145 43.8 ;
    END
  END bus_wdata_o[425]
  PIN bus_wdata_o[426]
    DIRECTION OUTPUT ;
    USE SIGNAL ;
    PORT
      LAYER M4 ;
        RECT  144.916 47.52 145 47.544 ;
    END
  END bus_wdata_o[426]
  PIN bus_wdata_o[427]
    DIRECTION OUTPUT ;
    USE SIGNAL ;
    PORT
      LAYER M4 ;
        RECT  144.916 46.656 145 46.68 ;
    END
  END bus_wdata_o[427]
  PIN bus_wdata_o[428]
    DIRECTION OUTPUT ;
    USE SIGNAL ;
    PORT
      LAYER M5 ;
        RECT  105.12 0 105.144 0.084 ;
    END
  END bus_wdata_o[428]
  PIN bus_wdata_o[429]
    DIRECTION OUTPUT ;
    USE SIGNAL ;
    PORT
      LAYER M5 ;
        RECT  109.152 0 109.176 0.084 ;
    END
  END bus_wdata_o[429]
  PIN bus_wdata_o[42]
    DIRECTION OUTPUT ;
    USE SIGNAL ;
    PORT
      LAYER M5 ;
        RECT  46.752 0 46.776 0.084 ;
    END
  END bus_wdata_o[42]
  PIN bus_wdata_o[430]
    DIRECTION OUTPUT ;
    USE SIGNAL ;
    PORT
      LAYER M5 ;
        RECT  105.696 0 105.72 0.084 ;
    END
  END bus_wdata_o[430]
  PIN bus_wdata_o[431]
    DIRECTION OUTPUT ;
    USE SIGNAL ;
    PORT
      LAYER M5 ;
        RECT  105.888 0 105.912 0.084 ;
    END
  END bus_wdata_o[431]
  PIN bus_wdata_o[432]
    DIRECTION OUTPUT ;
    USE SIGNAL ;
    PORT
      LAYER M4 ;
        RECT  144.916 59.808 145 59.832 ;
    END
  END bus_wdata_o[432]
  PIN bus_wdata_o[433]
    DIRECTION OUTPUT ;
    USE SIGNAL ;
    PORT
      LAYER M4 ;
        RECT  144.916 60.48 145 60.504 ;
    END
  END bus_wdata_o[433]
  PIN bus_wdata_o[434]
    DIRECTION OUTPUT ;
    USE SIGNAL ;
    PORT
      LAYER M4 ;
        RECT  144.916 58.656 145 58.68 ;
    END
  END bus_wdata_o[434]
  PIN bus_wdata_o[435]
    DIRECTION OUTPUT ;
    USE SIGNAL ;
    PORT
      LAYER M4 ;
        RECT  144.916 60.672 145 60.696 ;
    END
  END bus_wdata_o[435]
  PIN bus_wdata_o[436]
    DIRECTION OUTPUT ;
    USE SIGNAL ;
    PORT
      LAYER M5 ;
        RECT  105.312 0 105.336 0.084 ;
    END
  END bus_wdata_o[436]
  PIN bus_wdata_o[437]
    DIRECTION OUTPUT ;
    USE SIGNAL ;
    PORT
      LAYER M5 ;
        RECT  104.352 0 104.376 0.084 ;
    END
  END bus_wdata_o[437]
  PIN bus_wdata_o[438]
    DIRECTION OUTPUT ;
    USE SIGNAL ;
    PORT
      LAYER M4 ;
        RECT  144.916 59.04 145 59.064 ;
    END
  END bus_wdata_o[438]
  PIN bus_wdata_o[439]
    DIRECTION OUTPUT ;
    USE SIGNAL ;
    PORT
      LAYER M4 ;
        RECT  144.916 58.56 145 58.584 ;
    END
  END bus_wdata_o[439]
  PIN bus_wdata_o[43]
    DIRECTION OUTPUT ;
    USE SIGNAL ;
    PORT
      LAYER M5 ;
        RECT  46.656 0 46.68 0.084 ;
    END
  END bus_wdata_o[43]
  PIN bus_wdata_o[440]
    DIRECTION OUTPUT ;
    USE SIGNAL ;
    PORT
      LAYER M4 ;
        RECT  144.916 73.536 145 73.56 ;
    END
  END bus_wdata_o[440]
  PIN bus_wdata_o[441]
    DIRECTION OUTPUT ;
    USE SIGNAL ;
    PORT
      LAYER M4 ;
        RECT  144.916 58.848 145 58.872 ;
    END
  END bus_wdata_o[441]
  PIN bus_wdata_o[442]
    DIRECTION OUTPUT ;
    USE SIGNAL ;
    PORT
      LAYER M4 ;
        RECT  144.916 61.632 145 61.656 ;
    END
  END bus_wdata_o[442]
  PIN bus_wdata_o[443]
    DIRECTION OUTPUT ;
    USE SIGNAL ;
    PORT
      LAYER M4 ;
        RECT  144.916 61.248 145 61.272 ;
    END
  END bus_wdata_o[443]
  PIN bus_wdata_o[444]
    DIRECTION OUTPUT ;
    USE SIGNAL ;
    PORT
      LAYER M4 ;
        RECT  144.916 60.288 145 60.312 ;
    END
  END bus_wdata_o[444]
  PIN bus_wdata_o[445]
    DIRECTION OUTPUT ;
    USE SIGNAL ;
    PORT
      LAYER M4 ;
        RECT  144.916 59.52 145 59.544 ;
    END
  END bus_wdata_o[445]
  PIN bus_wdata_o[446]
    DIRECTION OUTPUT ;
    USE SIGNAL ;
    PORT
      LAYER M4 ;
        RECT  144.916 60 145 60.024 ;
    END
  END bus_wdata_o[446]
  PIN bus_wdata_o[447]
    DIRECTION OUTPUT ;
    USE SIGNAL ;
    PORT
      LAYER M4 ;
        RECT  144.916 59.232 145 59.256 ;
    END
  END bus_wdata_o[447]
  PIN bus_wdata_o[448]
    DIRECTION OUTPUT ;
    USE SIGNAL ;
    PORT
      LAYER M4 ;
        RECT  144.916 73.632 145 73.656 ;
    END
  END bus_wdata_o[448]
  PIN bus_wdata_o[449]
    DIRECTION OUTPUT ;
    USE SIGNAL ;
    PORT
      LAYER M4 ;
        RECT  144.916 65.184 145 65.208 ;
    END
  END bus_wdata_o[449]
  PIN bus_wdata_o[44]
    DIRECTION OUTPUT ;
    USE SIGNAL ;
    PORT
      LAYER M5 ;
        RECT  46.56 0 46.584 0.084 ;
    END
  END bus_wdata_o[44]
  PIN bus_wdata_o[450]
    DIRECTION OUTPUT ;
    USE SIGNAL ;
    PORT
      LAYER M4 ;
        RECT  144.916 61.44 145 61.464 ;
    END
  END bus_wdata_o[450]
  PIN bus_wdata_o[451]
    DIRECTION OUTPUT ;
    USE SIGNAL ;
    PORT
      LAYER M4 ;
        RECT  144.916 58.944 145 58.968 ;
    END
  END bus_wdata_o[451]
  PIN bus_wdata_o[452]
    DIRECTION OUTPUT ;
    USE SIGNAL ;
    PORT
      LAYER M4 ;
        RECT  144.916 59.904 145 59.928 ;
    END
  END bus_wdata_o[452]
  PIN bus_wdata_o[453]
    DIRECTION OUTPUT ;
    USE SIGNAL ;
    PORT
      LAYER M4 ;
        RECT  144.916 63.456 145 63.48 ;
    END
  END bus_wdata_o[453]
  PIN bus_wdata_o[454]
    DIRECTION OUTPUT ;
    USE SIGNAL ;
    PORT
      LAYER M4 ;
        RECT  144.916 61.728 145 61.752 ;
    END
  END bus_wdata_o[454]
  PIN bus_wdata_o[455]
    DIRECTION OUTPUT ;
    USE SIGNAL ;
    PORT
      LAYER M4 ;
        RECT  144.916 59.424 145 59.448 ;
    END
  END bus_wdata_o[455]
  PIN bus_wdata_o[456]
    DIRECTION OUTPUT ;
    USE SIGNAL ;
    PORT
      LAYER M4 ;
        RECT  144.916 58.464 145 58.488 ;
    END
  END bus_wdata_o[456]
  PIN bus_wdata_o[457]
    DIRECTION OUTPUT ;
    USE SIGNAL ;
    PORT
      LAYER M4 ;
        RECT  144.916 74.592 145 74.616 ;
    END
  END bus_wdata_o[457]
  PIN bus_wdata_o[458]
    DIRECTION OUTPUT ;
    USE SIGNAL ;
    PORT
      LAYER M4 ;
        RECT  144.916 59.136 145 59.16 ;
    END
  END bus_wdata_o[458]
  PIN bus_wdata_o[459]
    DIRECTION OUTPUT ;
    USE SIGNAL ;
    PORT
      LAYER M4 ;
        RECT  144.916 58.368 145 58.392 ;
    END
  END bus_wdata_o[459]
  PIN bus_wdata_o[45]
    DIRECTION OUTPUT ;
    USE SIGNAL ;
    PORT
      LAYER M5 ;
        RECT  45.216 0 45.24 0.084 ;
    END
  END bus_wdata_o[45]
  PIN bus_wdata_o[460]
    DIRECTION OUTPUT ;
    USE SIGNAL ;
    PORT
      LAYER M4 ;
        RECT  144.916 61.056 145 61.08 ;
    END
  END bus_wdata_o[460]
  PIN bus_wdata_o[461]
    DIRECTION OUTPUT ;
    USE SIGNAL ;
    PORT
      LAYER M4 ;
        RECT  144.916 60.864 145 60.888 ;
    END
  END bus_wdata_o[461]
  PIN bus_wdata_o[462]
    DIRECTION OUTPUT ;
    USE SIGNAL ;
    PORT
      LAYER M4 ;
        RECT  144.916 60.768 145 60.792 ;
    END
  END bus_wdata_o[462]
  PIN bus_wdata_o[463]
    DIRECTION OUTPUT ;
    USE SIGNAL ;
    PORT
      LAYER M4 ;
        RECT  144.916 59.328 145 59.352 ;
    END
  END bus_wdata_o[463]
  PIN bus_wdata_o[464]
    DIRECTION OUTPUT ;
    USE SIGNAL ;
    PORT
      LAYER M4 ;
        RECT  144.916 60.384 145 60.408 ;
    END
  END bus_wdata_o[464]
  PIN bus_wdata_o[465]
    DIRECTION OUTPUT ;
    USE SIGNAL ;
    PORT
      LAYER M4 ;
        RECT  144.916 62.976 145 63 ;
    END
  END bus_wdata_o[465]
  PIN bus_wdata_o[466]
    DIRECTION OUTPUT ;
    USE SIGNAL ;
    PORT
      LAYER M4 ;
        RECT  144.916 65.376 145 65.4 ;
    END
  END bus_wdata_o[466]
  PIN bus_wdata_o[467]
    DIRECTION OUTPUT ;
    USE SIGNAL ;
    PORT
      LAYER M4 ;
        RECT  144.916 62.016 145 62.04 ;
    END
  END bus_wdata_o[467]
  PIN bus_wdata_o[468]
    DIRECTION OUTPUT ;
    USE SIGNAL ;
    PORT
      LAYER M4 ;
        RECT  144.916 73.728 145 73.752 ;
    END
  END bus_wdata_o[468]
  PIN bus_wdata_o[469]
    DIRECTION OUTPUT ;
    USE SIGNAL ;
    PORT
      LAYER M4 ;
        RECT  144.916 63.648 145 63.672 ;
    END
  END bus_wdata_o[469]
  PIN bus_wdata_o[46]
    DIRECTION OUTPUT ;
    USE SIGNAL ;
    PORT
      LAYER M5 ;
        RECT  44.928 0 44.952 0.084 ;
    END
  END bus_wdata_o[46]
  PIN bus_wdata_o[470]
    DIRECTION OUTPUT ;
    USE SIGNAL ;
    PORT
      LAYER M4 ;
        RECT  144.916 65.568 145 65.592 ;
    END
  END bus_wdata_o[470]
  PIN bus_wdata_o[471]
    DIRECTION OUTPUT ;
    USE SIGNAL ;
    PORT
      LAYER M4 ;
        RECT  144.916 59.712 145 59.736 ;
    END
  END bus_wdata_o[471]
  PIN bus_wdata_o[472]
    DIRECTION OUTPUT ;
    USE SIGNAL ;
    PORT
      LAYER M4 ;
        RECT  144.916 59.616 145 59.64 ;
    END
  END bus_wdata_o[472]
  PIN bus_wdata_o[473]
    DIRECTION OUTPUT ;
    USE SIGNAL ;
    PORT
      LAYER M4 ;
        RECT  144.916 60.192 145 60.216 ;
    END
  END bus_wdata_o[473]
  PIN bus_wdata_o[474]
    DIRECTION OUTPUT ;
    USE SIGNAL ;
    PORT
      LAYER M4 ;
        RECT  144.916 64.608 145 64.632 ;
    END
  END bus_wdata_o[474]
  PIN bus_wdata_o[475]
    DIRECTION OUTPUT ;
    USE SIGNAL ;
    PORT
      LAYER M4 ;
        RECT  144.916 65.28 145 65.304 ;
    END
  END bus_wdata_o[475]
  PIN bus_wdata_o[476]
    DIRECTION OUTPUT ;
    USE SIGNAL ;
    PORT
      LAYER M4 ;
        RECT  144.916 60.576 145 60.6 ;
    END
  END bus_wdata_o[476]
  PIN bus_wdata_o[477]
    DIRECTION OUTPUT ;
    USE SIGNAL ;
    PORT
      LAYER M4 ;
        RECT  144.916 74.688 145 74.712 ;
    END
  END bus_wdata_o[477]
  PIN bus_wdata_o[478]
    DIRECTION OUTPUT ;
    USE SIGNAL ;
    PORT
      LAYER M4 ;
        RECT  144.916 73.824 145 73.848 ;
    END
  END bus_wdata_o[478]
  PIN bus_wdata_o[479]
    DIRECTION OUTPUT ;
    USE SIGNAL ;
    PORT
      LAYER M4 ;
        RECT  144.916 58.752 145 58.776 ;
    END
  END bus_wdata_o[479]
  PIN bus_wdata_o[47]
    DIRECTION OUTPUT ;
    USE SIGNAL ;
    PORT
      LAYER M5 ;
        RECT  43.488 0 43.512 0.084 ;
    END
  END bus_wdata_o[47]
  PIN bus_wdata_o[480]
    DIRECTION OUTPUT ;
    USE SIGNAL ;
    PORT
      LAYER M4 ;
        RECT  144.916 67.68 145 67.704 ;
    END
  END bus_wdata_o[480]
  PIN bus_wdata_o[481]
    DIRECTION OUTPUT ;
    USE SIGNAL ;
    PORT
      LAYER M4 ;
        RECT  144.916 72 145 72.024 ;
    END
  END bus_wdata_o[481]
  PIN bus_wdata_o[482]
    DIRECTION OUTPUT ;
    USE SIGNAL ;
    PORT
      LAYER M4 ;
        RECT  144.916 62.592 145 62.616 ;
    END
  END bus_wdata_o[482]
  PIN bus_wdata_o[483]
    DIRECTION OUTPUT ;
    USE SIGNAL ;
    PORT
      LAYER M4 ;
        RECT  144.916 61.344 145 61.368 ;
    END
  END bus_wdata_o[483]
  PIN bus_wdata_o[484]
    DIRECTION OUTPUT ;
    USE SIGNAL ;
    PORT
      LAYER M4 ;
        RECT  144.916 62.304 145 62.328 ;
    END
  END bus_wdata_o[484]
  PIN bus_wdata_o[485]
    DIRECTION OUTPUT ;
    USE SIGNAL ;
    PORT
      LAYER M4 ;
        RECT  144.916 73.92 145 73.944 ;
    END
  END bus_wdata_o[485]
  PIN bus_wdata_o[486]
    DIRECTION OUTPUT ;
    USE SIGNAL ;
    PORT
      LAYER M4 ;
        RECT  144.916 61.152 145 61.176 ;
    END
  END bus_wdata_o[486]
  PIN bus_wdata_o[487]
    DIRECTION OUTPUT ;
    USE SIGNAL ;
    PORT
      LAYER M4 ;
        RECT  144.916 62.4 145 62.424 ;
    END
  END bus_wdata_o[487]
  PIN bus_wdata_o[488]
    DIRECTION OUTPUT ;
    USE SIGNAL ;
    PORT
      LAYER M4 ;
        RECT  144.916 61.92 145 61.944 ;
    END
  END bus_wdata_o[488]
  PIN bus_wdata_o[489]
    DIRECTION OUTPUT ;
    USE SIGNAL ;
    PORT
      LAYER M4 ;
        RECT  144.916 63.84 145 63.864 ;
    END
  END bus_wdata_o[489]
  PIN bus_wdata_o[48]
    DIRECTION OUTPUT ;
    USE SIGNAL ;
    PORT
      LAYER M4 ;
        RECT  0 45.504 0.084 45.528 ;
    END
  END bus_wdata_o[48]
  PIN bus_wdata_o[490]
    DIRECTION OUTPUT ;
    USE SIGNAL ;
    PORT
      LAYER M4 ;
        RECT  144.916 62.688 145 62.712 ;
    END
  END bus_wdata_o[490]
  PIN bus_wdata_o[491]
    DIRECTION OUTPUT ;
    USE SIGNAL ;
    PORT
      LAYER M4 ;
        RECT  144.916 64.032 145 64.056 ;
    END
  END bus_wdata_o[491]
  PIN bus_wdata_o[492]
    DIRECTION OUTPUT ;
    USE SIGNAL ;
    PORT
      LAYER M4 ;
        RECT  144.916 69.312 145 69.336 ;
    END
  END bus_wdata_o[492]
  PIN bus_wdata_o[493]
    DIRECTION OUTPUT ;
    USE SIGNAL ;
    PORT
      LAYER M4 ;
        RECT  144.916 70.368 145 70.392 ;
    END
  END bus_wdata_o[493]
  PIN bus_wdata_o[494]
    DIRECTION OUTPUT ;
    USE SIGNAL ;
    PORT
      LAYER M4 ;
        RECT  144.916 68.16 145 68.184 ;
    END
  END bus_wdata_o[494]
  PIN bus_wdata_o[495]
    DIRECTION OUTPUT ;
    USE SIGNAL ;
    PORT
      LAYER M4 ;
        RECT  144.916 72.384 145 72.408 ;
    END
  END bus_wdata_o[495]
  PIN bus_wdata_o[496]
    DIRECTION OUTPUT ;
    USE SIGNAL ;
    PORT
      LAYER M4 ;
        RECT  144.916 64.512 145 64.536 ;
    END
  END bus_wdata_o[496]
  PIN bus_wdata_o[497]
    DIRECTION OUTPUT ;
    USE SIGNAL ;
    PORT
      LAYER M4 ;
        RECT  144.916 65.664 145 65.688 ;
    END
  END bus_wdata_o[497]
  PIN bus_wdata_o[498]
    DIRECTION OUTPUT ;
    USE SIGNAL ;
    PORT
      LAYER M4 ;
        RECT  144.916 71.328 145 71.352 ;
    END
  END bus_wdata_o[498]
  PIN bus_wdata_o[499]
    DIRECTION OUTPUT ;
    USE SIGNAL ;
    PORT
      LAYER M4 ;
        RECT  144.916 71.04 145 71.064 ;
    END
  END bus_wdata_o[499]
  PIN bus_wdata_o[49]
    DIRECTION OUTPUT ;
    USE SIGNAL ;
    PORT
      LAYER M4 ;
        RECT  0 43.872 0.084 43.896 ;
    END
  END bus_wdata_o[49]
  PIN bus_wdata_o[4]
    DIRECTION OUTPUT ;
    USE SIGNAL ;
    PORT
      LAYER M5 ;
        RECT  53.856 0 53.88 0.084 ;
    END
  END bus_wdata_o[4]
  PIN bus_wdata_o[500]
    DIRECTION OUTPUT ;
    USE SIGNAL ;
    PORT
      LAYER M4 ;
        RECT  144.916 72.192 145 72.216 ;
    END
  END bus_wdata_o[500]
  PIN bus_wdata_o[501]
    DIRECTION OUTPUT ;
    USE SIGNAL ;
    PORT
      LAYER M4 ;
        RECT  144.916 64.416 145 64.44 ;
    END
  END bus_wdata_o[501]
  PIN bus_wdata_o[502]
    DIRECTION OUTPUT ;
    USE SIGNAL ;
    PORT
      LAYER M4 ;
        RECT  144.916 71.232 145 71.256 ;
    END
  END bus_wdata_o[502]
  PIN bus_wdata_o[503]
    DIRECTION OUTPUT ;
    USE SIGNAL ;
    PORT
      LAYER M4 ;
        RECT  144.916 74.016 145 74.04 ;
    END
  END bus_wdata_o[503]
  PIN bus_wdata_o[504]
    DIRECTION OUTPUT ;
    USE SIGNAL ;
    PORT
      LAYER M4 ;
        RECT  144.916 69.216 145 69.24 ;
    END
  END bus_wdata_o[504]
  PIN bus_wdata_o[505]
    DIRECTION OUTPUT ;
    USE SIGNAL ;
    PORT
      LAYER M4 ;
        RECT  144.916 74.976 145 75 ;
    END
  END bus_wdata_o[505]
  PIN bus_wdata_o[506]
    DIRECTION OUTPUT ;
    USE SIGNAL ;
    PORT
      LAYER M4 ;
        RECT  144.916 67.2 145 67.224 ;
    END
  END bus_wdata_o[506]
  PIN bus_wdata_o[507]
    DIRECTION OUTPUT ;
    USE SIGNAL ;
    PORT
      LAYER M4 ;
        RECT  144.916 70.56 145 70.584 ;
    END
  END bus_wdata_o[507]
  PIN bus_wdata_o[508]
    DIRECTION OUTPUT ;
    USE SIGNAL ;
    PORT
      LAYER M4 ;
        RECT  144.916 75.072 145 75.096 ;
    END
  END bus_wdata_o[508]
  PIN bus_wdata_o[509]
    DIRECTION OUTPUT ;
    USE SIGNAL ;
    PORT
      LAYER M4 ;
        RECT  144.916 68.256 145 68.28 ;
    END
  END bus_wdata_o[509]
  PIN bus_wdata_o[50]
    DIRECTION OUTPUT ;
    USE SIGNAL ;
    PORT
      LAYER M4 ;
        RECT  0 43.584 0.084 43.608 ;
    END
  END bus_wdata_o[50]
  PIN bus_wdata_o[510]
    DIRECTION OUTPUT ;
    USE SIGNAL ;
    PORT
      LAYER M4 ;
        RECT  144.916 67.584 145 67.608 ;
    END
  END bus_wdata_o[510]
  PIN bus_wdata_o[511]
    DIRECTION OUTPUT ;
    USE SIGNAL ;
    PORT
      LAYER M4 ;
        RECT  144.916 68.64 145 68.664 ;
    END
  END bus_wdata_o[511]
  PIN bus_wdata_o[51]
    DIRECTION OUTPUT ;
    USE SIGNAL ;
    PORT
      LAYER M4 ;
        RECT  0 43.296 0.084 43.32 ;
    END
  END bus_wdata_o[51]
  PIN bus_wdata_o[52]
    DIRECTION OUTPUT ;
    USE SIGNAL ;
    PORT
      LAYER M4 ;
        RECT  0 43.104 0.084 43.128 ;
    END
  END bus_wdata_o[52]
  PIN bus_wdata_o[53]
    DIRECTION OUTPUT ;
    USE SIGNAL ;
    PORT
      LAYER M4 ;
        RECT  0 42.816 0.084 42.84 ;
    END
  END bus_wdata_o[53]
  PIN bus_wdata_o[54]
    DIRECTION OUTPUT ;
    USE SIGNAL ;
    PORT
      LAYER M4 ;
        RECT  0 44.256 0.084 44.28 ;
    END
  END bus_wdata_o[54]
  PIN bus_wdata_o[55]
    DIRECTION OUTPUT ;
    USE SIGNAL ;
    PORT
      LAYER M4 ;
        RECT  0 42.912 0.084 42.936 ;
    END
  END bus_wdata_o[55]
  PIN bus_wdata_o[56]
    DIRECTION OUTPUT ;
    USE SIGNAL ;
    PORT
      LAYER M4 ;
        RECT  0 43.008 0.084 43.032 ;
    END
  END bus_wdata_o[56]
  PIN bus_wdata_o[57]
    DIRECTION OUTPUT ;
    USE SIGNAL ;
    PORT
      LAYER M4 ;
        RECT  0 41.856 0.084 41.88 ;
    END
  END bus_wdata_o[57]
  PIN bus_wdata_o[58]
    DIRECTION OUTPUT ;
    USE SIGNAL ;
    PORT
      LAYER M4 ;
        RECT  0 41.76 0.084 41.784 ;
    END
  END bus_wdata_o[58]
  PIN bus_wdata_o[59]
    DIRECTION OUTPUT ;
    USE SIGNAL ;
    PORT
      LAYER M4 ;
        RECT  0 40.704 0.084 40.728 ;
    END
  END bus_wdata_o[59]
  PIN bus_wdata_o[5]
    DIRECTION OUTPUT ;
    USE SIGNAL ;
    PORT
      LAYER M5 ;
        RECT  52.992 0 53.016 0.084 ;
    END
  END bus_wdata_o[5]
  PIN bus_wdata_o[60]
    DIRECTION OUTPUT ;
    USE SIGNAL ;
    PORT
      LAYER M4 ;
        RECT  0 38.304 0.084 38.328 ;
    END
  END bus_wdata_o[60]
  PIN bus_wdata_o[61]
    DIRECTION OUTPUT ;
    USE SIGNAL ;
    PORT
      LAYER M4 ;
        RECT  0 38.4 0.084 38.424 ;
    END
  END bus_wdata_o[61]
  PIN bus_wdata_o[62]
    DIRECTION OUTPUT ;
    USE SIGNAL ;
    PORT
      LAYER M4 ;
        RECT  0 38.976 0.084 39 ;
    END
  END bus_wdata_o[62]
  PIN bus_wdata_o[63]
    DIRECTION OUTPUT ;
    USE SIGNAL ;
    PORT
      LAYER M4 ;
        RECT  0 39.456 0.084 39.48 ;
    END
  END bus_wdata_o[63]
  PIN bus_wdata_o[64]
    DIRECTION OUTPUT ;
    USE SIGNAL ;
    PORT
      LAYER M5 ;
        RECT  54.144 0 54.168 0.084 ;
    END
  END bus_wdata_o[64]
  PIN bus_wdata_o[65]
    DIRECTION OUTPUT ;
    USE SIGNAL ;
    PORT
      LAYER M5 ;
        RECT  52.896 0 52.92 0.084 ;
    END
  END bus_wdata_o[65]
  PIN bus_wdata_o[66]
    DIRECTION OUTPUT ;
    USE SIGNAL ;
    PORT
      LAYER M5 ;
        RECT  53.568 0 53.592 0.084 ;
    END
  END bus_wdata_o[66]
  PIN bus_wdata_o[67]
    DIRECTION OUTPUT ;
    USE SIGNAL ;
    PORT
      LAYER M5 ;
        RECT  53.376 0 53.4 0.084 ;
    END
  END bus_wdata_o[67]
  PIN bus_wdata_o[68]
    DIRECTION OUTPUT ;
    USE SIGNAL ;
    PORT
      LAYER M5 ;
        RECT  54.816 0 54.84 0.084 ;
    END
  END bus_wdata_o[68]
  PIN bus_wdata_o[69]
    DIRECTION OUTPUT ;
    USE SIGNAL ;
    PORT
      LAYER M5 ;
        RECT  55.392 0 55.416 0.084 ;
    END
  END bus_wdata_o[69]
  PIN bus_wdata_o[6]
    DIRECTION OUTPUT ;
    USE SIGNAL ;
    PORT
      LAYER M5 ;
        RECT  52.8 0 52.824 0.084 ;
    END
  END bus_wdata_o[6]
  PIN bus_wdata_o[70]
    DIRECTION OUTPUT ;
    USE SIGNAL ;
    PORT
      LAYER M5 ;
        RECT  52.512 0 52.536 0.084 ;
    END
  END bus_wdata_o[70]
  PIN bus_wdata_o[71]
    DIRECTION OUTPUT ;
    USE SIGNAL ;
    PORT
      LAYER M5 ;
        RECT  54.912 0 54.936 0.084 ;
    END
  END bus_wdata_o[71]
  PIN bus_wdata_o[72]
    DIRECTION OUTPUT ;
    USE SIGNAL ;
    PORT
      LAYER M5 ;
        RECT  48.192 0 48.216 0.084 ;
    END
  END bus_wdata_o[72]
  PIN bus_wdata_o[73]
    DIRECTION OUTPUT ;
    USE SIGNAL ;
    PORT
      LAYER M5 ;
        RECT  48.576 0 48.6 0.084 ;
    END
  END bus_wdata_o[73]
  PIN bus_wdata_o[74]
    DIRECTION OUTPUT ;
    USE SIGNAL ;
    PORT
      LAYER M5 ;
        RECT  47.232 0 47.256 0.084 ;
    END
  END bus_wdata_o[74]
  PIN bus_wdata_o[75]
    DIRECTION OUTPUT ;
    USE SIGNAL ;
    PORT
      LAYER M5 ;
        RECT  45.696 0 45.72 0.084 ;
    END
  END bus_wdata_o[75]
  PIN bus_wdata_o[76]
    DIRECTION OUTPUT ;
    USE SIGNAL ;
    PORT
      LAYER M5 ;
        RECT  42.528 0 42.552 0.084 ;
    END
  END bus_wdata_o[76]
  PIN bus_wdata_o[77]
    DIRECTION OUTPUT ;
    USE SIGNAL ;
    PORT
      LAYER M5 ;
        RECT  44.448 0 44.472 0.084 ;
    END
  END bus_wdata_o[77]
  PIN bus_wdata_o[78]
    DIRECTION OUTPUT ;
    USE SIGNAL ;
    PORT
      LAYER M5 ;
        RECT  44.736 0 44.76 0.084 ;
    END
  END bus_wdata_o[78]
  PIN bus_wdata_o[79]
    DIRECTION OUTPUT ;
    USE SIGNAL ;
    PORT
      LAYER M5 ;
        RECT  44.352 0 44.376 0.084 ;
    END
  END bus_wdata_o[79]
  PIN bus_wdata_o[7]
    DIRECTION OUTPUT ;
    USE SIGNAL ;
    PORT
      LAYER M5 ;
        RECT  49.344 0 49.368 0.084 ;
    END
  END bus_wdata_o[7]
  PIN bus_wdata_o[80]
    DIRECTION OUTPUT ;
    USE SIGNAL ;
    PORT
      LAYER M4 ;
        RECT  0 40.608 0.084 40.632 ;
    END
  END bus_wdata_o[80]
  PIN bus_wdata_o[81]
    DIRECTION OUTPUT ;
    USE SIGNAL ;
    PORT
      LAYER M4 ;
        RECT  0 41.376 0.084 41.4 ;
    END
  END bus_wdata_o[81]
  PIN bus_wdata_o[82]
    DIRECTION OUTPUT ;
    USE SIGNAL ;
    PORT
      LAYER M4 ;
        RECT  0 40.896 0.084 40.92 ;
    END
  END bus_wdata_o[82]
  PIN bus_wdata_o[83]
    DIRECTION OUTPUT ;
    USE SIGNAL ;
    PORT
      LAYER M4 ;
        RECT  0 40.416 0.084 40.44 ;
    END
  END bus_wdata_o[83]
  PIN bus_wdata_o[84]
    DIRECTION OUTPUT ;
    USE SIGNAL ;
    PORT
      LAYER M4 ;
        RECT  0 41.184 0.084 41.208 ;
    END
  END bus_wdata_o[84]
  PIN bus_wdata_o[85]
    DIRECTION OUTPUT ;
    USE SIGNAL ;
    PORT
      LAYER M4 ;
        RECT  0 42.144 0.084 42.168 ;
    END
  END bus_wdata_o[85]
  PIN bus_wdata_o[86]
    DIRECTION OUTPUT ;
    USE SIGNAL ;
    PORT
      LAYER M4 ;
        RECT  0 42.24 0.084 42.264 ;
    END
  END bus_wdata_o[86]
  PIN bus_wdata_o[87]
    DIRECTION OUTPUT ;
    USE SIGNAL ;
    PORT
      LAYER M4 ;
        RECT  0 45.696 0.084 45.72 ;
    END
  END bus_wdata_o[87]
  PIN bus_wdata_o[88]
    DIRECTION OUTPUT ;
    USE SIGNAL ;
    PORT
      LAYER M4 ;
        RECT  0 45.216 0.084 45.24 ;
    END
  END bus_wdata_o[88]
  PIN bus_wdata_o[89]
    DIRECTION OUTPUT ;
    USE SIGNAL ;
    PORT
      LAYER M4 ;
        RECT  0 45.408 0.084 45.432 ;
    END
  END bus_wdata_o[89]
  PIN bus_wdata_o[8]
    DIRECTION OUTPUT ;
    USE SIGNAL ;
    PORT
      LAYER M5 ;
        RECT  48.096 0 48.12 0.084 ;
    END
  END bus_wdata_o[8]
  PIN bus_wdata_o[90]
    DIRECTION OUTPUT ;
    USE SIGNAL ;
    PORT
      LAYER M4 ;
        RECT  0 44.928 0.084 44.952 ;
    END
  END bus_wdata_o[90]
  PIN bus_wdata_o[91]
    DIRECTION OUTPUT ;
    USE SIGNAL ;
    PORT
      LAYER M4 ;
        RECT  0 44.832 0.084 44.856 ;
    END
  END bus_wdata_o[91]
  PIN bus_wdata_o[92]
    DIRECTION OUTPUT ;
    USE SIGNAL ;
    PORT
      LAYER M4 ;
        RECT  0 45.12 0.084 45.144 ;
    END
  END bus_wdata_o[92]
  PIN bus_wdata_o[93]
    DIRECTION OUTPUT ;
    USE SIGNAL ;
    PORT
      LAYER M4 ;
        RECT  0 45.6 0.084 45.624 ;
    END
  END bus_wdata_o[93]
  PIN bus_wdata_o[94]
    DIRECTION OUTPUT ;
    USE SIGNAL ;
    PORT
      LAYER M4 ;
        RECT  0 45.024 0.084 45.048 ;
    END
  END bus_wdata_o[94]
  PIN bus_wdata_o[95]
    DIRECTION OUTPUT ;
    USE SIGNAL ;
    PORT
      LAYER M5 ;
        RECT  50.592 0 50.616 0.084 ;
    END
  END bus_wdata_o[95]
  PIN bus_wdata_o[96]
    DIRECTION OUTPUT ;
    USE SIGNAL ;
    PORT
      LAYER M5 ;
        RECT  51.168 0 51.192 0.084 ;
    END
  END bus_wdata_o[96]
  PIN bus_wdata_o[97]
    DIRECTION OUTPUT ;
    USE SIGNAL ;
    PORT
      LAYER M5 ;
        RECT  55.296 0 55.32 0.084 ;
    END
  END bus_wdata_o[97]
  PIN bus_wdata_o[98]
    DIRECTION OUTPUT ;
    USE SIGNAL ;
    PORT
      LAYER M5 ;
        RECT  54.24 0 54.264 0.084 ;
    END
  END bus_wdata_o[98]
  PIN bus_wdata_o[99]
    DIRECTION OUTPUT ;
    USE SIGNAL ;
    PORT
      LAYER M5 ;
        RECT  52.704 0 52.728 0.084 ;
    END
  END bus_wdata_o[99]
  PIN bus_wdata_o[9]
    DIRECTION OUTPUT ;
    USE SIGNAL ;
    PORT
      LAYER M5 ;
        RECT  48.384 0 48.408 0.084 ;
    END
  END bus_wdata_o[9]
  PIN clk_i
    DIRECTION INPUT ;
    USE SIGNAL ;
    PORT
      LAYER M5 ;
        RECT  70.08 144.916 70.104 145 ;
    END
  END clk_i
  PIN core_clk_en_i
    DIRECTION INPUT ;
    USE SIGNAL ;
    PORT
      LAYER M4 ;
        RECT  0 60.384 0.084 60.408 ;
    END
  END core_clk_en_i
  PIN dbg_csr_addr_i[0]
    DIRECTION INPUT ;
    USE SIGNAL ;
    PORT
      LAYER M5 ;
        RECT  72.288 0 72.312 0.084 ;
    END
  END dbg_csr_addr_i[0]
  PIN dbg_csr_addr_i[10]
    DIRECTION INPUT ;
    USE SIGNAL ;
    PORT
      LAYER M5 ;
        RECT  74.304 0 74.328 0.084 ;
    END
  END dbg_csr_addr_i[10]
  PIN dbg_csr_addr_i[11]
    DIRECTION INPUT ;
    USE SIGNAL ;
    PORT
      LAYER M5 ;
        RECT  73.92 0 73.944 0.084 ;
    END
  END dbg_csr_addr_i[11]
  PIN dbg_csr_addr_i[1]
    DIRECTION INPUT ;
    USE SIGNAL ;
    PORT
      LAYER M5 ;
        RECT  71.904 0 71.928 0.084 ;
    END
  END dbg_csr_addr_i[1]
  PIN dbg_csr_addr_i[2]
    DIRECTION INPUT ;
    USE SIGNAL ;
    PORT
      LAYER M5 ;
        RECT  72.768 0 72.792 0.084 ;
    END
  END dbg_csr_addr_i[2]
  PIN dbg_csr_addr_i[3]
    DIRECTION INPUT ;
    USE SIGNAL ;
    PORT
      LAYER M5 ;
        RECT  72.576 0 72.6 0.084 ;
    END
  END dbg_csr_addr_i[3]
  PIN dbg_csr_addr_i[4]
    DIRECTION INPUT ;
    USE SIGNAL ;
    PORT
      LAYER M5 ;
        RECT  73.632 0 73.656 0.084 ;
    END
  END dbg_csr_addr_i[4]
  PIN dbg_csr_addr_i[5]
    DIRECTION INPUT ;
    USE SIGNAL ;
    PORT
      LAYER M5 ;
        RECT  75.552 0 75.576 0.084 ;
    END
  END dbg_csr_addr_i[5]
  PIN dbg_csr_addr_i[6]
    DIRECTION INPUT ;
    USE SIGNAL ;
    PORT
      LAYER M5 ;
        RECT  75.648 0 75.672 0.084 ;
    END
  END dbg_csr_addr_i[6]
  PIN dbg_csr_addr_i[7]
    DIRECTION INPUT ;
    USE SIGNAL ;
    PORT
      LAYER M5 ;
        RECT  73.824 0 73.848 0.084 ;
    END
  END dbg_csr_addr_i[7]
  PIN dbg_csr_addr_i[8]
    DIRECTION INPUT ;
    USE SIGNAL ;
    PORT
      LAYER M5 ;
        RECT  72.96 0 72.984 0.084 ;
    END
  END dbg_csr_addr_i[8]
  PIN dbg_csr_addr_i[9]
    DIRECTION INPUT ;
    USE SIGNAL ;
    PORT
      LAYER M5 ;
        RECT  73.152 0 73.176 0.084 ;
    END
  END dbg_csr_addr_i[9]
  PIN dbg_csr_rdata_o[0]
    DIRECTION OUTPUT ;
    USE SIGNAL ;
    PORT
      LAYER M5 ;
        RECT  71.808 0 71.832 0.084 ;
    END
  END dbg_csr_rdata_o[0]
  PIN dbg_csr_rdata_o[10]
    DIRECTION OUTPUT ;
    USE SIGNAL ;
    PORT
      LAYER M5 ;
        RECT  69.216 0 69.24 0.084 ;
    END
  END dbg_csr_rdata_o[10]
  PIN dbg_csr_rdata_o[11]
    DIRECTION OUTPUT ;
    USE SIGNAL ;
    PORT
      LAYER M5 ;
        RECT  69.312 0 69.336 0.084 ;
    END
  END dbg_csr_rdata_o[11]
  PIN dbg_csr_rdata_o[12]
    DIRECTION OUTPUT ;
    USE SIGNAL ;
    PORT
      LAYER M5 ;
        RECT  69.024 0 69.048 0.084 ;
    END
  END dbg_csr_rdata_o[12]
  PIN dbg_csr_rdata_o[13]
    DIRECTION OUTPUT ;
    USE SIGNAL ;
    PORT
      LAYER M5 ;
        RECT  69.12 0 69.144 0.084 ;
    END
  END dbg_csr_rdata_o[13]
  PIN dbg_csr_rdata_o[14]
    DIRECTION OUTPUT ;
    USE SIGNAL ;
    PORT
      LAYER M5 ;
        RECT  66.912 0 66.936 0.084 ;
    END
  END dbg_csr_rdata_o[14]
  PIN dbg_csr_rdata_o[15]
    DIRECTION OUTPUT ;
    USE SIGNAL ;
    PORT
      LAYER M5 ;
        RECT  66.72 0 66.744 0.084 ;
    END
  END dbg_csr_rdata_o[15]
  PIN dbg_csr_rdata_o[16]
    DIRECTION OUTPUT ;
    USE SIGNAL ;
    PORT
      LAYER M5 ;
        RECT  67.392 0 67.416 0.084 ;
    END
  END dbg_csr_rdata_o[16]
  PIN dbg_csr_rdata_o[17]
    DIRECTION OUTPUT ;
    USE SIGNAL ;
    PORT
      LAYER M5 ;
        RECT  67.776 0 67.8 0.084 ;
    END
  END dbg_csr_rdata_o[17]
  PIN dbg_csr_rdata_o[18]
    DIRECTION OUTPUT ;
    USE SIGNAL ;
    PORT
      LAYER M5 ;
        RECT  67.008 0 67.032 0.084 ;
    END
  END dbg_csr_rdata_o[18]
  PIN dbg_csr_rdata_o[19]
    DIRECTION OUTPUT ;
    USE SIGNAL ;
    PORT
      LAYER M5 ;
        RECT  69.408 0 69.432 0.084 ;
    END
  END dbg_csr_rdata_o[19]
  PIN dbg_csr_rdata_o[1]
    DIRECTION OUTPUT ;
    USE SIGNAL ;
    PORT
      LAYER M5 ;
        RECT  70.272 0 70.296 0.084 ;
    END
  END dbg_csr_rdata_o[1]
  PIN dbg_csr_rdata_o[20]
    DIRECTION OUTPUT ;
    USE SIGNAL ;
    PORT
      LAYER M5 ;
        RECT  68.064 0 68.088 0.084 ;
    END
  END dbg_csr_rdata_o[20]
  PIN dbg_csr_rdata_o[21]
    DIRECTION OUTPUT ;
    USE SIGNAL ;
    PORT
      LAYER M5 ;
        RECT  67.104 0 67.128 0.084 ;
    END
  END dbg_csr_rdata_o[21]
  PIN dbg_csr_rdata_o[22]
    DIRECTION OUTPUT ;
    USE SIGNAL ;
    PORT
      LAYER M5 ;
        RECT  70.368 0 70.392 0.084 ;
    END
  END dbg_csr_rdata_o[22]
  PIN dbg_csr_rdata_o[23]
    DIRECTION OUTPUT ;
    USE SIGNAL ;
    PORT
      LAYER M5 ;
        RECT  68.736 0 68.76 0.084 ;
    END
  END dbg_csr_rdata_o[23]
  PIN dbg_csr_rdata_o[24]
    DIRECTION OUTPUT ;
    USE SIGNAL ;
    PORT
      LAYER M5 ;
        RECT  71.424 0 71.448 0.084 ;
    END
  END dbg_csr_rdata_o[24]
  PIN dbg_csr_rdata_o[25]
    DIRECTION OUTPUT ;
    USE SIGNAL ;
    PORT
      LAYER M5 ;
        RECT  68.64 0 68.664 0.084 ;
    END
  END dbg_csr_rdata_o[25]
  PIN dbg_csr_rdata_o[26]
    DIRECTION OUTPUT ;
    USE SIGNAL ;
    PORT
      LAYER M5 ;
        RECT  69.504 0 69.528 0.084 ;
    END
  END dbg_csr_rdata_o[26]
  PIN dbg_csr_rdata_o[27]
    DIRECTION OUTPUT ;
    USE SIGNAL ;
    PORT
      LAYER M5 ;
        RECT  67.968 0 67.992 0.084 ;
    END
  END dbg_csr_rdata_o[27]
  PIN dbg_csr_rdata_o[28]
    DIRECTION OUTPUT ;
    USE SIGNAL ;
    PORT
      LAYER M5 ;
        RECT  68.352 0 68.376 0.084 ;
    END
  END dbg_csr_rdata_o[28]
  PIN dbg_csr_rdata_o[29]
    DIRECTION OUTPUT ;
    USE SIGNAL ;
    PORT
      LAYER M5 ;
        RECT  68.16 0 68.184 0.084 ;
    END
  END dbg_csr_rdata_o[29]
  PIN dbg_csr_rdata_o[2]
    DIRECTION OUTPUT ;
    USE SIGNAL ;
    PORT
      LAYER M5 ;
        RECT  70.656 0 70.68 0.084 ;
    END
  END dbg_csr_rdata_o[2]
  PIN dbg_csr_rdata_o[30]
    DIRECTION OUTPUT ;
    USE SIGNAL ;
    PORT
      LAYER M5 ;
        RECT  66.432 0 66.456 0.084 ;
    END
  END dbg_csr_rdata_o[30]
  PIN dbg_csr_rdata_o[31]
    DIRECTION OUTPUT ;
    USE SIGNAL ;
    PORT
      LAYER M5 ;
        RECT  68.928 0 68.952 0.084 ;
    END
  END dbg_csr_rdata_o[31]
  PIN dbg_csr_rdata_o[3]
    DIRECTION OUTPUT ;
    USE SIGNAL ;
    PORT
      LAYER M5 ;
        RECT  68.544 0 68.568 0.084 ;
    END
  END dbg_csr_rdata_o[3]
  PIN dbg_csr_rdata_o[4]
    DIRECTION OUTPUT ;
    USE SIGNAL ;
    PORT
      LAYER M5 ;
        RECT  68.448 0 68.472 0.084 ;
    END
  END dbg_csr_rdata_o[4]
  PIN dbg_csr_rdata_o[5]
    DIRECTION OUTPUT ;
    USE SIGNAL ;
    PORT
      LAYER M5 ;
        RECT  67.872 0 67.896 0.084 ;
    END
  END dbg_csr_rdata_o[5]
  PIN dbg_csr_rdata_o[6]
    DIRECTION OUTPUT ;
    USE SIGNAL ;
    PORT
      LAYER M5 ;
        RECT  67.2 0 67.224 0.084 ;
    END
  END dbg_csr_rdata_o[6]
  PIN dbg_csr_rdata_o[7]
    DIRECTION OUTPUT ;
    USE SIGNAL ;
    PORT
      LAYER M5 ;
        RECT  67.584 0 67.608 0.084 ;
    END
  END dbg_csr_rdata_o[7]
  PIN dbg_csr_rdata_o[8]
    DIRECTION OUTPUT ;
    USE SIGNAL ;
    PORT
      LAYER M5 ;
        RECT  69.6 0 69.624 0.084 ;
    END
  END dbg_csr_rdata_o[8]
  PIN dbg_csr_rdata_o[9]
    DIRECTION OUTPUT ;
    USE SIGNAL ;
    PORT
      LAYER M5 ;
        RECT  68.832 0 68.856 0.084 ;
    END
  END dbg_csr_rdata_o[9]
  PIN dbg_csr_we_i
    DIRECTION INPUT ;
    USE SIGNAL ;
    PORT
      LAYER M5 ;
        RECT  76.224 0 76.248 0.084 ;
    END
  END dbg_csr_we_i
  PIN dbg_pc_o[0]
    DIRECTION OUTPUT ;
    USE SIGNAL ;
    PORT
      LAYER M5 ;
        RECT  86.88 0 86.904 0.084 ;
    END
  END dbg_pc_o[0]
  PIN dbg_pc_o[10]
    DIRECTION OUTPUT ;
    USE SIGNAL ;
    PORT
      LAYER M4 ;
        RECT  144.916 67.872 145 67.896 ;
    END
  END dbg_pc_o[10]
  PIN dbg_pc_o[11]
    DIRECTION OUTPUT ;
    USE SIGNAL ;
    PORT
      LAYER M4 ;
        RECT  144.916 67.968 145 67.992 ;
    END
  END dbg_pc_o[11]
  PIN dbg_pc_o[12]
    DIRECTION OUTPUT ;
    USE SIGNAL ;
    PORT
      LAYER M4 ;
        RECT  144.916 64.992 145 65.016 ;
    END
  END dbg_pc_o[12]
  PIN dbg_pc_o[13]
    DIRECTION OUTPUT ;
    USE SIGNAL ;
    PORT
      LAYER M4 ;
        RECT  144.916 71.712 145 71.736 ;
    END
  END dbg_pc_o[13]
  PIN dbg_pc_o[14]
    DIRECTION OUTPUT ;
    USE SIGNAL ;
    PORT
      LAYER M4 ;
        RECT  144.916 64.8 145 64.824 ;
    END
  END dbg_pc_o[14]
  PIN dbg_pc_o[15]
    DIRECTION OUTPUT ;
    USE SIGNAL ;
    PORT
      LAYER M4 ;
        RECT  144.916 70.464 145 70.488 ;
    END
  END dbg_pc_o[15]
  PIN dbg_pc_o[16]
    DIRECTION OUTPUT ;
    USE SIGNAL ;
    PORT
      LAYER M4 ;
        RECT  144.916 66.048 145 66.072 ;
    END
  END dbg_pc_o[16]
  PIN dbg_pc_o[17]
    DIRECTION OUTPUT ;
    USE SIGNAL ;
    PORT
      LAYER M4 ;
        RECT  144.916 69.408 145 69.432 ;
    END
  END dbg_pc_o[17]
  PIN dbg_pc_o[18]
    DIRECTION OUTPUT ;
    USE SIGNAL ;
    PORT
      LAYER M4 ;
        RECT  144.916 68.352 145 68.376 ;
    END
  END dbg_pc_o[18]
  PIN dbg_pc_o[19]
    DIRECTION OUTPUT ;
    USE SIGNAL ;
    PORT
      LAYER M5 ;
        RECT  87.36 0 87.384 0.084 ;
    END
  END dbg_pc_o[19]
  PIN dbg_pc_o[1]
    DIRECTION OUTPUT ;
    USE SIGNAL ;
    PORT
      LAYER M5 ;
        RECT  85.248 0 85.272 0.084 ;
    END
  END dbg_pc_o[1]
  PIN dbg_pc_o[20]
    DIRECTION OUTPUT ;
    USE SIGNAL ;
    PORT
      LAYER M4 ;
        RECT  144.916 65.472 145 65.496 ;
    END
  END dbg_pc_o[20]
  PIN dbg_pc_o[21]
    DIRECTION OUTPUT ;
    USE SIGNAL ;
    PORT
      LAYER M4 ;
        RECT  144.916 70.656 145 70.68 ;
    END
  END dbg_pc_o[21]
  PIN dbg_pc_o[22]
    DIRECTION OUTPUT ;
    USE SIGNAL ;
    PORT
      LAYER M4 ;
        RECT  144.916 66.336 145 66.36 ;
    END
  END dbg_pc_o[22]
  PIN dbg_pc_o[23]
    DIRECTION OUTPUT ;
    USE SIGNAL ;
    PORT
      LAYER M4 ;
        RECT  144.916 62.496 145 62.52 ;
    END
  END dbg_pc_o[23]
  PIN dbg_pc_o[24]
    DIRECTION OUTPUT ;
    USE SIGNAL ;
    PORT
      LAYER M5 ;
        RECT  89.472 0 89.496 0.084 ;
    END
  END dbg_pc_o[24]
  PIN dbg_pc_o[25]
    DIRECTION OUTPUT ;
    USE SIGNAL ;
    PORT
      LAYER M4 ;
        RECT  144.916 74.112 145 74.136 ;
    END
  END dbg_pc_o[25]
  PIN dbg_pc_o[26]
    DIRECTION OUTPUT ;
    USE SIGNAL ;
    PORT
      LAYER M4 ;
        RECT  144.916 63.264 145 63.288 ;
    END
  END dbg_pc_o[26]
  PIN dbg_pc_o[27]
    DIRECTION OUTPUT ;
    USE SIGNAL ;
    PORT
      LAYER M4 ;
        RECT  144.916 74.784 145 74.808 ;
    END
  END dbg_pc_o[27]
  PIN dbg_pc_o[28]
    DIRECTION OUTPUT ;
    USE SIGNAL ;
    PORT
      LAYER M4 ;
        RECT  144.916 66.912 145 66.936 ;
    END
  END dbg_pc_o[28]
  PIN dbg_pc_o[29]
    DIRECTION OUTPUT ;
    USE SIGNAL ;
    PORT
      LAYER M4 ;
        RECT  144.916 72.48 145 72.504 ;
    END
  END dbg_pc_o[29]
  PIN dbg_pc_o[2]
    DIRECTION OUTPUT ;
    USE SIGNAL ;
    PORT
      LAYER M5 ;
        RECT  87.264 0 87.288 0.084 ;
    END
  END dbg_pc_o[2]
  PIN dbg_pc_o[30]
    DIRECTION OUTPUT ;
    USE SIGNAL ;
    PORT
      LAYER M4 ;
        RECT  144.916 64.128 145 64.152 ;
    END
  END dbg_pc_o[30]
  PIN dbg_pc_o[31]
    DIRECTION OUTPUT ;
    USE SIGNAL ;
    PORT
      LAYER M4 ;
        RECT  144.916 63.744 145 63.768 ;
    END
  END dbg_pc_o[31]
  PIN dbg_pc_o[3]
    DIRECTION OUTPUT ;
    USE SIGNAL ;
    PORT
      LAYER M4 ;
        RECT  144.916 64.896 145 64.92 ;
    END
  END dbg_pc_o[3]
  PIN dbg_pc_o[4]
    DIRECTION OUTPUT ;
    USE SIGNAL ;
    PORT
      LAYER M4 ;
        RECT  144.916 66.24 145 66.264 ;
    END
  END dbg_pc_o[4]
  PIN dbg_pc_o[5]
    DIRECTION OUTPUT ;
    USE SIGNAL ;
    PORT
      LAYER M4 ;
        RECT  144.916 67.488 145 67.512 ;
    END
  END dbg_pc_o[5]
  PIN dbg_pc_o[6]
    DIRECTION OUTPUT ;
    USE SIGNAL ;
    PORT
      LAYER M4 ;
        RECT  144.916 72.288 145 72.312 ;
    END
  END dbg_pc_o[6]
  PIN dbg_pc_o[7]
    DIRECTION OUTPUT ;
    USE SIGNAL ;
    PORT
      LAYER M5 ;
        RECT  87.456 0 87.48 0.084 ;
    END
  END dbg_pc_o[7]
  PIN dbg_pc_o[8]
    DIRECTION OUTPUT ;
    USE SIGNAL ;
    PORT
      LAYER M4 ;
        RECT  144.916 67.296 145 67.32 ;
    END
  END dbg_pc_o[8]
  PIN dbg_pc_o[9]
    DIRECTION OUTPUT ;
    USE SIGNAL ;
    PORT
      LAYER M4 ;
        RECT  144.916 63.36 145 63.384 ;
    END
  END dbg_pc_o[9]
  PIN dbg_pc_we_i
    DIRECTION INPUT ;
    USE SIGNAL ;
    PORT
      LAYER M5 ;
        RECT  82.944 0 82.968 0.084 ;
    END
  END dbg_pc_we_i
  PIN dbg_rf_addr_i[0]
    DIRECTION INPUT ;
    USE SIGNAL ;
    PORT
      LAYER M5 ;
        RECT  76.32 144.916 76.344 145 ;
    END
  END dbg_rf_addr_i[0]
  PIN dbg_rf_addr_i[1]
    DIRECTION INPUT ;
    USE SIGNAL ;
    PORT
      LAYER M5 ;
        RECT  77.28 144.916 77.304 145 ;
    END
  END dbg_rf_addr_i[1]
  PIN dbg_rf_addr_i[2]
    DIRECTION INPUT ;
    USE SIGNAL ;
    PORT
      LAYER M5 ;
        RECT  74.976 144.916 75 145 ;
    END
  END dbg_rf_addr_i[2]
  PIN dbg_rf_addr_i[3]
    DIRECTION INPUT ;
    USE SIGNAL ;
    PORT
      LAYER M4 ;
        RECT  144.916 71.904 145 71.928 ;
    END
  END dbg_rf_addr_i[3]
  PIN dbg_rf_addr_i[4]
    DIRECTION INPUT ;
    USE SIGNAL ;
    PORT
      LAYER M5 ;
        RECT  75.072 144.916 75.096 145 ;
    END
  END dbg_rf_addr_i[4]
  PIN dbg_rf_rdata_o[0]
    DIRECTION OUTPUT ;
    USE SIGNAL ;
    PORT
      LAYER M4 ;
        RECT  0 75.552 0.084 75.576 ;
    END
  END dbg_rf_rdata_o[0]
  PIN dbg_rf_rdata_o[10]
    DIRECTION OUTPUT ;
    USE SIGNAL ;
    PORT
      LAYER M4 ;
        RECT  0 73.632 0.084 73.656 ;
    END
  END dbg_rf_rdata_o[10]
  PIN dbg_rf_rdata_o[11]
    DIRECTION OUTPUT ;
    USE SIGNAL ;
    PORT
      LAYER M4 ;
        RECT  0 75.072 0.084 75.096 ;
    END
  END dbg_rf_rdata_o[11]
  PIN dbg_rf_rdata_o[12]
    DIRECTION OUTPUT ;
    USE SIGNAL ;
    PORT
      LAYER M4 ;
        RECT  0 74.688 0.084 74.712 ;
    END
  END dbg_rf_rdata_o[12]
  PIN dbg_rf_rdata_o[13]
    DIRECTION OUTPUT ;
    USE SIGNAL ;
    PORT
      LAYER M4 ;
        RECT  0 74.976 0.084 75 ;
    END
  END dbg_rf_rdata_o[13]
  PIN dbg_rf_rdata_o[14]
    DIRECTION OUTPUT ;
    USE SIGNAL ;
    PORT
      LAYER M4 ;
        RECT  0 75.264 0.084 75.288 ;
    END
  END dbg_rf_rdata_o[14]
  PIN dbg_rf_rdata_o[15]
    DIRECTION OUTPUT ;
    USE SIGNAL ;
    PORT
      LAYER M4 ;
        RECT  0 73.056 0.084 73.08 ;
    END
  END dbg_rf_rdata_o[15]
  PIN dbg_rf_rdata_o[16]
    DIRECTION OUTPUT ;
    USE SIGNAL ;
    PORT
      LAYER M4 ;
        RECT  0 72.768 0.084 72.792 ;
    END
  END dbg_rf_rdata_o[16]
  PIN dbg_rf_rdata_o[17]
    DIRECTION OUTPUT ;
    USE SIGNAL ;
    PORT
      LAYER M4 ;
        RECT  0 73.152 0.084 73.176 ;
    END
  END dbg_rf_rdata_o[17]
  PIN dbg_rf_rdata_o[18]
    DIRECTION OUTPUT ;
    USE SIGNAL ;
    PORT
      LAYER M4 ;
        RECT  0 73.92 0.084 73.944 ;
    END
  END dbg_rf_rdata_o[18]
  PIN dbg_rf_rdata_o[19]
    DIRECTION OUTPUT ;
    USE SIGNAL ;
    PORT
      LAYER M4 ;
        RECT  0 73.824 0.084 73.848 ;
    END
  END dbg_rf_rdata_o[19]
  PIN dbg_rf_rdata_o[1]
    DIRECTION OUTPUT ;
    USE SIGNAL ;
    PORT
      LAYER M4 ;
        RECT  0 74.496 0.084 74.52 ;
    END
  END dbg_rf_rdata_o[1]
  PIN dbg_rf_rdata_o[20]
    DIRECTION OUTPUT ;
    USE SIGNAL ;
    PORT
      LAYER M4 ;
        RECT  0 74.4 0.084 74.424 ;
    END
  END dbg_rf_rdata_o[20]
  PIN dbg_rf_rdata_o[21]
    DIRECTION OUTPUT ;
    USE SIGNAL ;
    PORT
      LAYER M4 ;
        RECT  0 72.672 0.084 72.696 ;
    END
  END dbg_rf_rdata_o[21]
  PIN dbg_rf_rdata_o[22]
    DIRECTION OUTPUT ;
    USE SIGNAL ;
    PORT
      LAYER M4 ;
        RECT  0 74.304 0.084 74.328 ;
    END
  END dbg_rf_rdata_o[22]
  PIN dbg_rf_rdata_o[23]
    DIRECTION OUTPUT ;
    USE SIGNAL ;
    PORT
      LAYER M4 ;
        RECT  0 75.36 0.084 75.384 ;
    END
  END dbg_rf_rdata_o[23]
  PIN dbg_rf_rdata_o[24]
    DIRECTION OUTPUT ;
    USE SIGNAL ;
    PORT
      LAYER M4 ;
        RECT  0 72.576 0.084 72.6 ;
    END
  END dbg_rf_rdata_o[24]
  PIN dbg_rf_rdata_o[25]
    DIRECTION OUTPUT ;
    USE SIGNAL ;
    PORT
      LAYER M4 ;
        RECT  0 73.536 0.084 73.56 ;
    END
  END dbg_rf_rdata_o[25]
  PIN dbg_rf_rdata_o[26]
    DIRECTION OUTPUT ;
    USE SIGNAL ;
    PORT
      LAYER M4 ;
        RECT  0 72.864 0.084 72.888 ;
    END
  END dbg_rf_rdata_o[26]
  PIN dbg_rf_rdata_o[27]
    DIRECTION OUTPUT ;
    USE SIGNAL ;
    PORT
      LAYER M4 ;
        RECT  0 74.88 0.084 74.904 ;
    END
  END dbg_rf_rdata_o[27]
  PIN dbg_rf_rdata_o[28]
    DIRECTION OUTPUT ;
    USE SIGNAL ;
    PORT
      LAYER M4 ;
        RECT  0 74.112 0.084 74.136 ;
    END
  END dbg_rf_rdata_o[28]
  PIN dbg_rf_rdata_o[29]
    DIRECTION OUTPUT ;
    USE SIGNAL ;
    PORT
      LAYER M4 ;
        RECT  0 74.016 0.084 74.04 ;
    END
  END dbg_rf_rdata_o[29]
  PIN dbg_rf_rdata_o[2]
    DIRECTION OUTPUT ;
    USE SIGNAL ;
    PORT
      LAYER M4 ;
        RECT  0 73.344 0.084 73.368 ;
    END
  END dbg_rf_rdata_o[2]
  PIN dbg_rf_rdata_o[30]
    DIRECTION OUTPUT ;
    USE SIGNAL ;
    PORT
      LAYER M4 ;
        RECT  0 74.784 0.084 74.808 ;
    END
  END dbg_rf_rdata_o[30]
  PIN dbg_rf_rdata_o[31]
    DIRECTION OUTPUT ;
    USE SIGNAL ;
    PORT
      LAYER M4 ;
        RECT  0 73.44 0.084 73.464 ;
    END
  END dbg_rf_rdata_o[31]
  PIN dbg_rf_rdata_o[3]
    DIRECTION OUTPUT ;
    USE SIGNAL ;
    PORT
      LAYER M4 ;
        RECT  0 73.248 0.084 73.272 ;
    END
  END dbg_rf_rdata_o[3]
  PIN dbg_rf_rdata_o[4]
    DIRECTION OUTPUT ;
    USE SIGNAL ;
    PORT
      LAYER M4 ;
        RECT  0 70.752 0.084 70.776 ;
    END
  END dbg_rf_rdata_o[4]
  PIN dbg_rf_rdata_o[5]
    DIRECTION OUTPUT ;
    USE SIGNAL ;
    PORT
      LAYER M4 ;
        RECT  0 75.456 0.084 75.48 ;
    END
  END dbg_rf_rdata_o[5]
  PIN dbg_rf_rdata_o[6]
    DIRECTION OUTPUT ;
    USE SIGNAL ;
    PORT
      LAYER M4 ;
        RECT  0 75.648 0.084 75.672 ;
    END
  END dbg_rf_rdata_o[6]
  PIN dbg_rf_rdata_o[7]
    DIRECTION OUTPUT ;
    USE SIGNAL ;
    PORT
      LAYER M4 ;
        RECT  0 74.592 0.084 74.616 ;
    END
  END dbg_rf_rdata_o[7]
  PIN dbg_rf_rdata_o[8]
    DIRECTION OUTPUT ;
    USE SIGNAL ;
    PORT
      LAYER M4 ;
        RECT  0 75.168 0.084 75.192 ;
    END
  END dbg_rf_rdata_o[8]
  PIN dbg_rf_rdata_o[9]
    DIRECTION OUTPUT ;
    USE SIGNAL ;
    PORT
      LAYER M4 ;
        RECT  0 73.728 0.084 73.752 ;
    END
  END dbg_rf_rdata_o[9]
  PIN dbg_rf_we_i
    DIRECTION INPUT ;
    USE SIGNAL ;
    PORT
      LAYER M5 ;
        RECT  75.456 0 75.48 0.084 ;
    END
  END dbg_rf_we_i
  PIN dbg_wdata_i[0]
    DIRECTION INPUT ;
    USE SIGNAL ;
    PORT
      LAYER M5 ;
        RECT  68.256 0 68.28 0.084 ;
    END
  END dbg_wdata_i[0]
  PIN dbg_wdata_i[10]
    DIRECTION INPUT ;
    USE SIGNAL ;
    PORT
      LAYER M5 ;
        RECT  69.984 0 70.008 0.084 ;
    END
  END dbg_wdata_i[10]
  PIN dbg_wdata_i[11]
    DIRECTION INPUT ;
    USE SIGNAL ;
    PORT
      LAYER M4 ;
        RECT  144.916 65.856 145 65.88 ;
    END
  END dbg_wdata_i[11]
  PIN dbg_wdata_i[12]
    DIRECTION INPUT ;
    USE SIGNAL ;
    PORT
      LAYER M4 ;
        RECT  144.916 71.136 145 71.16 ;
    END
  END dbg_wdata_i[12]
  PIN dbg_wdata_i[13]
    DIRECTION INPUT ;
    USE SIGNAL ;
    PORT
      LAYER M4 ;
        RECT  144.916 70.752 145 70.776 ;
    END
  END dbg_wdata_i[13]
  PIN dbg_wdata_i[14]
    DIRECTION INPUT ;
    USE SIGNAL ;
    PORT
      LAYER M4 ;
        RECT  144.916 63.072 145 63.096 ;
    END
  END dbg_wdata_i[14]
  PIN dbg_wdata_i[15]
    DIRECTION INPUT ;
    USE SIGNAL ;
    PORT
      LAYER M4 ;
        RECT  144.916 71.808 145 71.832 ;
    END
  END dbg_wdata_i[15]
  PIN dbg_wdata_i[16]
    DIRECTION INPUT ;
    USE SIGNAL ;
    PORT
      LAYER M4 ;
        RECT  144.916 69.792 145 69.816 ;
    END
  END dbg_wdata_i[16]
  PIN dbg_wdata_i[17]
    DIRECTION INPUT ;
    USE SIGNAL ;
    PORT
      LAYER M5 ;
        RECT  69.696 0 69.72 0.084 ;
    END
  END dbg_wdata_i[17]
  PIN dbg_wdata_i[18]
    DIRECTION INPUT ;
    USE SIGNAL ;
    PORT
      LAYER M4 ;
        RECT  144.916 67.392 145 67.416 ;
    END
  END dbg_wdata_i[18]
  PIN dbg_wdata_i[19]
    DIRECTION INPUT ;
    USE SIGNAL ;
    PORT
      LAYER M5 ;
        RECT  69.792 0 69.816 0.084 ;
    END
  END dbg_wdata_i[19]
  PIN dbg_wdata_i[1]
    DIRECTION INPUT ;
    USE SIGNAL ;
    PORT
      LAYER M5 ;
        RECT  83.04 0 83.064 0.084 ;
    END
  END dbg_wdata_i[1]
  PIN dbg_wdata_i[20]
    DIRECTION INPUT ;
    USE SIGNAL ;
    PORT
      LAYER M4 ;
        RECT  144.916 62.112 145 62.136 ;
    END
  END dbg_wdata_i[20]
  PIN dbg_wdata_i[21]
    DIRECTION INPUT ;
    USE SIGNAL ;
    PORT
      LAYER M4 ;
        RECT  144.916 67.104 145 67.128 ;
    END
  END dbg_wdata_i[21]
  PIN dbg_wdata_i[22]
    DIRECTION INPUT ;
    USE SIGNAL ;
    PORT
      LAYER M4 ;
        RECT  144.916 69.504 145 69.528 ;
    END
  END dbg_wdata_i[22]
  PIN dbg_wdata_i[23]
    DIRECTION INPUT ;
    USE SIGNAL ;
    PORT
      LAYER M5 ;
        RECT  77.568 0 77.592 0.084 ;
    END
  END dbg_wdata_i[23]
  PIN dbg_wdata_i[24]
    DIRECTION INPUT ;
    USE SIGNAL ;
    PORT
      LAYER M5 ;
        RECT  77.664 0 77.688 0.084 ;
    END
  END dbg_wdata_i[24]
  PIN dbg_wdata_i[25]
    DIRECTION INPUT ;
    USE SIGNAL ;
    PORT
      LAYER M4 ;
        RECT  144.916 73.056 145 73.08 ;
    END
  END dbg_wdata_i[25]
  PIN dbg_wdata_i[26]
    DIRECTION INPUT ;
    USE SIGNAL ;
    PORT
      LAYER M4 ;
        RECT  144.916 74.208 145 74.232 ;
    END
  END dbg_wdata_i[26]
  PIN dbg_wdata_i[27]
    DIRECTION INPUT ;
    USE SIGNAL ;
    PORT
      LAYER M4 ;
        RECT  144.916 62.88 145 62.904 ;
    END
  END dbg_wdata_i[27]
  PIN dbg_wdata_i[28]
    DIRECTION INPUT ;
    USE SIGNAL ;
    PORT
      LAYER M4 ;
        RECT  144.916 70.272 145 70.296 ;
    END
  END dbg_wdata_i[28]
  PIN dbg_wdata_i[29]
    DIRECTION INPUT ;
    USE SIGNAL ;
    PORT
      LAYER M4 ;
        RECT  144.916 70.848 145 70.872 ;
    END
  END dbg_wdata_i[29]
  PIN dbg_wdata_i[2]
    DIRECTION INPUT ;
    USE SIGNAL ;
    PORT
      LAYER M5 ;
        RECT  69.888 0 69.912 0.084 ;
    END
  END dbg_wdata_i[2]
  PIN dbg_wdata_i[30]
    DIRECTION INPUT ;
    USE SIGNAL ;
    PORT
      LAYER M4 ;
        RECT  144.916 63.168 145 63.192 ;
    END
  END dbg_wdata_i[30]
  PIN dbg_wdata_i[31]
    DIRECTION INPUT ;
    USE SIGNAL ;
    PORT
      LAYER M5 ;
        RECT  70.08 0 70.104 0.084 ;
    END
  END dbg_wdata_i[31]
  PIN dbg_wdata_i[3]
    DIRECTION INPUT ;
    USE SIGNAL ;
    PORT
      LAYER M4 ;
        RECT  144.916 66.624 145 66.648 ;
    END
  END dbg_wdata_i[3]
  PIN dbg_wdata_i[4]
    DIRECTION INPUT ;
    USE SIGNAL ;
    PORT
      LAYER M4 ;
        RECT  144.916 68.832 145 68.856 ;
    END
  END dbg_wdata_i[4]
  PIN dbg_wdata_i[5]
    DIRECTION INPUT ;
    USE SIGNAL ;
    PORT
      LAYER M4 ;
        RECT  144.916 71.424 145 71.448 ;
    END
  END dbg_wdata_i[5]
  PIN dbg_wdata_i[6]
    DIRECTION INPUT ;
    USE SIGNAL ;
    PORT
      LAYER M4 ;
        RECT  144.916 69.984 145 70.008 ;
    END
  END dbg_wdata_i[6]
  PIN dbg_wdata_i[7]
    DIRECTION INPUT ;
    USE SIGNAL ;
    PORT
      LAYER M5 ;
        RECT  82.656 0 82.68 0.084 ;
    END
  END dbg_wdata_i[7]
  PIN dbg_wdata_i[8]
    DIRECTION INPUT ;
    USE SIGNAL ;
    PORT
      LAYER M4 ;
        RECT  144.916 66.432 145 66.456 ;
    END
  END dbg_wdata_i[8]
  PIN dbg_wdata_i[9]
    DIRECTION INPUT ;
    USE SIGNAL ;
    PORT
      LAYER M5 ;
        RECT  71.136 0 71.16 0.084 ;
    END
  END dbg_wdata_i[9]
  PIN events_o[0]
    DIRECTION OUTPUT ;
    USE SIGNAL ;
    PORT
      LAYER M5 ;
        RECT  58.272 0 58.296 0.084 ;
    END
  END events_o[0]
  PIN events_o[10]
    DIRECTION OUTPUT ;
    USE SIGNAL ;
    PORT
      LAYER M5 ;
        RECT  127.2 144.916 127.224 145 ;
    END
  END events_o[10]
  PIN events_o[11]
    DIRECTION OUTPUT ;
    USE SIGNAL ;
    PORT
      LAYER M4 ;
        RECT  144.916 136.512 145 136.536 ;
    END
  END events_o[11]
  PIN events_o[12]
    DIRECTION OUTPUT ;
    USE SIGNAL ;
    PORT
      LAYER M4 ;
        RECT  144.916 68.064 145 68.088 ;
    END
  END events_o[12]
  PIN events_o[13]
    DIRECTION OUTPUT ;
    USE SIGNAL ;
    PORT
      LAYER M5 ;
        RECT  93.888 144.916 93.912 145 ;
    END
  END events_o[13]
  PIN events_o[14]
    DIRECTION OUTPUT ;
    USE SIGNAL ;
    PORT
      LAYER M5 ;
        RECT  93.696 144.916 93.72 145 ;
    END
  END events_o[14]
  PIN events_o[15]
    DIRECTION OUTPUT ;
    USE SIGNAL ;
    PORT
      LAYER M4 ;
        RECT  144.916 75.264 145 75.288 ;
    END
  END events_o[15]
  PIN events_o[1]
    DIRECTION OUTPUT ;
    USE SIGNAL ;
    PORT
      LAYER M4 ;
        RECT  0 57.984 0.084 58.008 ;
    END
  END events_o[1]
  PIN events_o[2]
    DIRECTION OUTPUT ;
    USE SIGNAL ;
    PORT
      LAYER M5 ;
        RECT  130.176 144.916 130.2 145 ;
    END
  END events_o[2]
  PIN events_o[3]
    DIRECTION OUTPUT ;
    USE SIGNAL ;
    PORT
      LAYER M4 ;
        RECT  0 57.888 0.084 57.912 ;
    END
  END events_o[3]
  PIN events_o[4]
    DIRECTION OUTPUT ;
    USE SIGNAL ;
    PORT
      LAYER M4 ;
        RECT  0 86.592 0.084 86.616 ;
    END
  END events_o[4]
  PIN events_o[5]
    DIRECTION OUTPUT ;
    USE SIGNAL ;
    PORT
      LAYER M5 ;
        RECT  53.184 144.916 53.208 145 ;
    END
  END events_o[5]
  PIN events_o[6]
    DIRECTION OUTPUT ;
    USE SIGNAL ;
    PORT
      LAYER M5 ;
        RECT  53.568 144.916 53.592 145 ;
    END
  END events_o[6]
  PIN events_o[7]
    DIRECTION OUTPUT ;
    USE SIGNAL ;
    PORT
      LAYER M4 ;
        RECT  0 64.8 0.084 64.824 ;
    END
  END events_o[7]
  PIN events_o[8]
    DIRECTION OUTPUT ;
    USE SIGNAL ;
    PORT
      LAYER M4 ;
        RECT  144.916 60.096 145 60.12 ;
    END
  END events_o[8]
  PIN events_o[9]
    DIRECTION OUTPUT ;
    USE SIGNAL ;
    PORT
      LAYER M4 ;
        RECT  144.916 88.128 145 88.152 ;
    END
  END events_o[9]
  PIN flush_done_o
    DIRECTION OUTPUT ;
    USE SIGNAL ;
    PORT
      LAYER M4 ;
        RECT  144.916 91.392 145 91.416 ;
    END
  END flush_done_o
  PIN flush_i
    DIRECTION INPUT ;
    USE SIGNAL ;
    PORT
      LAYER M4 ;
        RECT  0 86.4 0.084 86.424 ;
    END
  END flush_i
  PIN halt_req_i
    DIRECTION INPUT ;
    USE SIGNAL ;
    PORT
      LAYER M5 ;
        RECT  88.32 0 88.344 0.084 ;
    END
  END halt_req_i
  PIN halted_o
    DIRECTION OUTPUT ;
    USE SIGNAL ;
    PORT
      LAYER M5 ;
        RECT  67.296 0 67.32 0.084 ;
    END
  END halted_o
  PIN hart_id_i[0]
    DIRECTION INPUT ;
    USE SIGNAL ;
    PORT
      LAYER M5 ;
        RECT  74.208 0 74.232 0.084 ;
    END
  END hart_id_i[0]
  PIN hart_id_i[10]
    DIRECTION INPUT ;
    USE SIGNAL ;
    PORT
      LAYER M5 ;
        RECT  80.832 0 80.856 0.084 ;
    END
  END hart_id_i[10]
  PIN hart_id_i[11]
    DIRECTION INPUT ;
    USE SIGNAL ;
    PORT
      LAYER M5 ;
        RECT  79.392 0 79.416 0.084 ;
    END
  END hart_id_i[11]
  PIN hart_id_i[12]
    DIRECTION INPUT ;
    USE SIGNAL ;
    PORT
      LAYER M5 ;
        RECT  81.024 0 81.048 0.084 ;
    END
  END hart_id_i[12]
  PIN hart_id_i[13]
    DIRECTION INPUT ;
    USE SIGNAL ;
    PORT
      LAYER M5 ;
        RECT  78.144 0 78.168 0.084 ;
    END
  END hart_id_i[13]
  PIN hart_id_i[14]
    DIRECTION INPUT ;
    USE SIGNAL ;
    PORT
      LAYER M5 ;
        RECT  80.16 0 80.184 0.084 ;
    END
  END hart_id_i[14]
  PIN hart_id_i[15]
    DIRECTION INPUT ;
    USE SIGNAL ;
    PORT
      LAYER M5 ;
        RECT  81.408 0 81.432 0.084 ;
    END
  END hart_id_i[15]
  PIN hart_id_i[16]
    DIRECTION INPUT ;
    USE SIGNAL ;
    PORT
      LAYER M5 ;
        RECT  80.352 0 80.376 0.084 ;
    END
  END hart_id_i[16]
  PIN hart_id_i[17]
    DIRECTION INPUT ;
    USE SIGNAL ;
    PORT
      LAYER M5 ;
        RECT  79.104 0 79.128 0.084 ;
    END
  END hart_id_i[17]
  PIN hart_id_i[18]
    DIRECTION INPUT ;
    USE SIGNAL ;
    PORT
      LAYER M5 ;
        RECT  81.984 0 82.008 0.084 ;
    END
  END hart_id_i[18]
  PIN hart_id_i[19]
    DIRECTION INPUT ;
    USE SIGNAL ;
    PORT
      LAYER M5 ;
        RECT  79.776 0 79.8 0.084 ;
    END
  END hart_id_i[19]
  PIN hart_id_i[1]
    DIRECTION INPUT ;
    USE SIGNAL ;
    PORT
      LAYER M5 ;
        RECT  81.312 0 81.336 0.084 ;
    END
  END hart_id_i[1]
  PIN hart_id_i[20]
    DIRECTION INPUT ;
    USE SIGNAL ;
    PORT
      LAYER M5 ;
        RECT  79.008 0 79.032 0.084 ;
    END
  END hart_id_i[20]
  PIN hart_id_i[21]
    DIRECTION INPUT ;
    USE SIGNAL ;
    PORT
      LAYER M5 ;
        RECT  81.216 0 81.24 0.084 ;
    END
  END hart_id_i[21]
  PIN hart_id_i[22]
    DIRECTION INPUT ;
    USE SIGNAL ;
    PORT
      LAYER M5 ;
        RECT  77.28 0 77.304 0.084 ;
    END
  END hart_id_i[22]
  PIN hart_id_i[23]
    DIRECTION INPUT ;
    USE SIGNAL ;
    PORT
      LAYER M5 ;
        RECT  77.184 0 77.208 0.084 ;
    END
  END hart_id_i[23]
  PIN hart_id_i[24]
    DIRECTION INPUT ;
    USE SIGNAL ;
    PORT
      LAYER M5 ;
        RECT  77.088 0 77.112 0.084 ;
    END
  END hart_id_i[24]
  PIN hart_id_i[25]
    DIRECTION INPUT ;
    USE SIGNAL ;
    PORT
      LAYER M5 ;
        RECT  78.624 0 78.648 0.084 ;
    END
  END hart_id_i[25]
  PIN hart_id_i[26]
    DIRECTION INPUT ;
    USE SIGNAL ;
    PORT
      LAYER M5 ;
        RECT  76.896 0 76.92 0.084 ;
    END
  END hart_id_i[26]
  PIN hart_id_i[27]
    DIRECTION INPUT ;
    USE SIGNAL ;
    PORT
      LAYER M5 ;
        RECT  76.992 0 77.016 0.084 ;
    END
  END hart_id_i[27]
  PIN hart_id_i[28]
    DIRECTION INPUT ;
    USE SIGNAL ;
    PORT
      LAYER M5 ;
        RECT  79.872 0 79.896 0.084 ;
    END
  END hart_id_i[28]
  PIN hart_id_i[29]
    DIRECTION INPUT ;
    USE SIGNAL ;
    PORT
      LAYER M5 ;
        RECT  80.064 0 80.088 0.084 ;
    END
  END hart_id_i[29]
  PIN hart_id_i[2]
    DIRECTION INPUT ;
    USE SIGNAL ;
    PORT
      LAYER M5 ;
        RECT  78.912 0 78.936 0.084 ;
    END
  END hart_id_i[2]
  PIN hart_id_i[30]
    DIRECTION INPUT ;
    USE SIGNAL ;
    PORT
      LAYER M5 ;
        RECT  76.8 0 76.824 0.084 ;
    END
  END hart_id_i[30]
  PIN hart_id_i[31]
    DIRECTION INPUT ;
    USE SIGNAL ;
    PORT
      LAYER M5 ;
        RECT  78.816 0 78.84 0.084 ;
    END
  END hart_id_i[31]
  PIN hart_id_i[3]
    DIRECTION INPUT ;
    USE SIGNAL ;
    PORT
      LAYER M5 ;
        RECT  78.432 0 78.456 0.084 ;
    END
  END hart_id_i[3]
  PIN hart_id_i[4]
    DIRECTION INPUT ;
    USE SIGNAL ;
    PORT
      LAYER M5 ;
        RECT  82.368 0 82.392 0.084 ;
    END
  END hart_id_i[4]
  PIN hart_id_i[5]
    DIRECTION INPUT ;
    USE SIGNAL ;
    PORT
      LAYER M5 ;
        RECT  81.12 0 81.144 0.084 ;
    END
  END hart_id_i[5]
  PIN hart_id_i[6]
    DIRECTION INPUT ;
    USE SIGNAL ;
    PORT
      LAYER M5 ;
        RECT  82.272 0 82.296 0.084 ;
    END
  END hart_id_i[6]
  PIN hart_id_i[7]
    DIRECTION INPUT ;
    USE SIGNAL ;
    PORT
      LAYER M5 ;
        RECT  78.72 0 78.744 0.084 ;
    END
  END hart_id_i[7]
  PIN hart_id_i[8]
    DIRECTION INPUT ;
    USE SIGNAL ;
    PORT
      LAYER M5 ;
        RECT  73.44 0 73.464 0.084 ;
    END
  END hart_id_i[8]
  PIN hart_id_i[9]
    DIRECTION INPUT ;
    USE SIGNAL ;
    PORT
      LAYER M5 ;
        RECT  80.928 0 80.952 0.084 ;
    END
  END hart_id_i[9]
  PIN irq_external_i
    DIRECTION INPUT ;
    USE SIGNAL ;
    PORT
      LAYER M5 ;
        RECT  79.2 0 79.224 0.084 ;
    END
  END irq_external_i
  PIN irq_software_i
    DIRECTION INPUT ;
    USE SIGNAL ;
    PORT
      LAYER M5 ;
        RECT  78.528 0 78.552 0.084 ;
    END
  END irq_software_i
  PIN irq_timer_i
    DIRECTION INPUT ;
    USE SIGNAL ;
    PORT
      LAYER M5 ;
        RECT  79.296 0 79.32 0.084 ;
    END
  END irq_timer_i
  PIN l1_clk_en_i
    DIRECTION INPUT ;
    USE SIGNAL ;
    PORT
      LAYER M4 ;
        RECT  0 60.288 0.084 60.312 ;
    END
  END l1_clk_en_i
  PIN retire_o
    DIRECTION OUTPUT ;
    USE SIGNAL ;
    PORT
      LAYER M5 ;
        RECT  78.336 0 78.36 0.084 ;
    END
  END retire_o
  PIN rst_ni
    DIRECTION INPUT ;
    USE SIGNAL ;
    PORT
      LAYER M5 ;
        RECT  105.792 144.916 105.816 145 ;
    END
  END rst_ni
  PIN snoop_addr_i[0]
    DIRECTION INPUT ;
    USE SIGNAL ;
    PORT
      LAYER M5 ;
        RECT  0.768 0 0.792 0.084 ;
    END
  END snoop_addr_i[0]
  PIN snoop_addr_i[10]
    DIRECTION INPUT ;
    USE SIGNAL ;
    PORT
      LAYER M5 ;
        RECT  86.592 144.916 86.616 145 ;
    END
  END snoop_addr_i[10]
  PIN snoop_addr_i[11]
    DIRECTION INPUT ;
    USE SIGNAL ;
    PORT
      LAYER M5 ;
        RECT  86.496 144.916 86.52 145 ;
    END
  END snoop_addr_i[11]
  PIN snoop_addr_i[12]
    DIRECTION INPUT ;
    USE SIGNAL ;
    PORT
      LAYER M5 ;
        RECT  86.4 144.916 86.424 145 ;
    END
  END snoop_addr_i[12]
  PIN snoop_addr_i[13]
    DIRECTION INPUT ;
    USE SIGNAL ;
    PORT
      LAYER M4 ;
        RECT  0 93.216 0.084 93.24 ;
    END
  END snoop_addr_i[13]
  PIN snoop_addr_i[14]
    DIRECTION INPUT ;
    USE SIGNAL ;
    PORT
      LAYER M4 ;
        RECT  0 93.504 0.084 93.528 ;
    END
  END snoop_addr_i[14]
  PIN snoop_addr_i[15]
    DIRECTION INPUT ;
    USE SIGNAL ;
    PORT
      LAYER M4 ;
        RECT  0 92.64 0.084 92.664 ;
    END
  END snoop_addr_i[15]
  PIN snoop_addr_i[16]
    DIRECTION INPUT ;
    USE SIGNAL ;
    PORT
      LAYER M4 ;
        RECT  0 94.464 0.084 94.488 ;
    END
  END snoop_addr_i[16]
  PIN snoop_addr_i[17]
    DIRECTION INPUT ;
    USE SIGNAL ;
    PORT
      LAYER M4 ;
        RECT  0 92.064 0.084 92.088 ;
    END
  END snoop_addr_i[17]
  PIN snoop_addr_i[18]
    DIRECTION INPUT ;
    USE SIGNAL ;
    PORT
      LAYER M4 ;
        RECT  0 93.792 0.084 93.816 ;
    END
  END snoop_addr_i[18]
  PIN snoop_addr_i[19]
    DIRECTION INPUT ;
    USE SIGNAL ;
    PORT
      LAYER M4 ;
        RECT  0 94.752 0.084 94.776 ;
    END
  END snoop_addr_i[19]
  PIN snoop_addr_i[1]
    DIRECTION INPUT ;
    USE SIGNAL ;
    PORT
      LAYER M5 ;
        RECT  0.864 0 0.888 0.084 ;
    END
  END snoop_addr_i[1]
  PIN snoop_addr_i[20]
    DIRECTION INPUT ;
    USE SIGNAL ;
    PORT
      LAYER M4 ;
        RECT  0 97.92 0.084 97.944 ;
    END
  END snoop_addr_i[20]
  PIN snoop_addr_i[21]
    DIRECTION INPUT ;
    USE SIGNAL ;
    PORT
      LAYER M4 ;
        RECT  0 95.712 0.084 95.736 ;
    END
  END snoop_addr_i[21]
  PIN snoop_addr_i[22]
    DIRECTION INPUT ;
    USE SIGNAL ;
    PORT
      LAYER M4 ;
        RECT  0 96.384 0.084 96.408 ;
    END
  END snoop_addr_i[22]
  PIN snoop_addr_i[23]
    DIRECTION INPUT ;
    USE SIGNAL ;
    PORT
      LAYER M4 ;
        RECT  0 94.944 0.084 94.968 ;
    END
  END snoop_addr_i[23]
  PIN snoop_addr_i[24]
    DIRECTION INPUT ;
    USE SIGNAL ;
    PORT
      LAYER M4 ;
        RECT  0 96.576 0.084 96.6 ;
    END
  END snoop_addr_i[24]
  PIN snoop_addr_i[25]
    DIRECTION INPUT ;
    USE SIGNAL ;
    PORT
      LAYER M4 ;
        RECT  0 95.808 0.084 95.832 ;
    END
  END snoop_addr_i[25]
  PIN snoop_addr_i[26]
    DIRECTION INPUT ;
    USE SIGNAL ;
    PORT
      LAYER M4 ;
        RECT  0 97.632 0.084 97.656 ;
    END
  END snoop_addr_i[26]
  PIN snoop_addr_i[27]
    DIRECTION INPUT ;
    USE SIGNAL ;
    PORT
      LAYER M4 ;
        RECT  0 96.96 0.084 96.984 ;
    END
  END snoop_addr_i[27]
  PIN snoop_addr_i[28]
    DIRECTION INPUT ;
    USE SIGNAL ;
    PORT
      LAYER M4 ;
        RECT  0 95.52 0.084 95.544 ;
    END
  END snoop_addr_i[28]
  PIN snoop_addr_i[29]
    DIRECTION INPUT ;
    USE SIGNAL ;
    PORT
      LAYER M4 ;
        RECT  0 98.688 0.084 98.712 ;
    END
  END snoop_addr_i[29]
  PIN snoop_addr_i[2]
    DIRECTION INPUT ;
    USE SIGNAL ;
    PORT
      LAYER M5 ;
        RECT  0.96 0 0.984 0.084 ;
    END
  END snoop_addr_i[2]
  PIN snoop_addr_i[30]
    DIRECTION INPUT ;
    USE SIGNAL ;
    PORT
      LAYER M4 ;
        RECT  0 98.88 0.084 98.904 ;
    END
  END snoop_addr_i[30]
  PIN snoop_addr_i[31]
    DIRECTION INPUT ;
    USE SIGNAL ;
    PORT
      LAYER M4 ;
        RECT  0 100.224 0.084 100.248 ;
    END
  END snoop_addr_i[31]
  PIN snoop_addr_i[3]
    DIRECTION INPUT ;
    USE SIGNAL ;
    PORT
      LAYER M5 ;
        RECT  1.056 0 1.08 0.084 ;
    END
  END snoop_addr_i[3]
  PIN snoop_addr_i[4]
    DIRECTION INPUT ;
    USE SIGNAL ;
    PORT
      LAYER M5 ;
        RECT  1.152 0 1.176 0.084 ;
    END
  END snoop_addr_i[4]
  PIN snoop_addr_i[5]
    DIRECTION INPUT ;
    USE SIGNAL ;
    PORT
      LAYER M5 ;
        RECT  86.304 144.916 86.328 145 ;
    END
  END snoop_addr_i[5]
  PIN snoop_addr_i[6]
    DIRECTION INPUT ;
    USE SIGNAL ;
    PORT
      LAYER M5 ;
        RECT  86.208 144.916 86.232 145 ;
    END
  END snoop_addr_i[6]
  PIN snoop_addr_i[7]
    DIRECTION INPUT ;
    USE SIGNAL ;
    PORT
      LAYER M5 ;
        RECT  86.112 144.916 86.136 145 ;
    END
  END snoop_addr_i[7]
  PIN snoop_addr_i[8]
    DIRECTION INPUT ;
    USE SIGNAL ;
    PORT
      LAYER M5 ;
        RECT  86.016 144.916 86.04 145 ;
    END
  END snoop_addr_i[8]
  PIN snoop_addr_i[9]
    DIRECTION INPUT ;
    USE SIGNAL ;
    PORT
      LAYER M5 ;
        RECT  85.92 144.916 85.944 145 ;
    END
  END snoop_addr_i[9]
  PIN snoop_data_o[0]
    DIRECTION OUTPUT ;
    USE SIGNAL ;
    PORT
      LAYER M5 ;
        RECT  40.992 0 41.016 0.084 ;
    END
  END snoop_data_o[0]
  PIN snoop_data_o[100]
    DIRECTION OUTPUT ;
    USE SIGNAL ;
    PORT
      LAYER M5 ;
        RECT  40.128 0 40.152 0.084 ;
    END
  END snoop_data_o[100]
  PIN snoop_data_o[101]
    DIRECTION OUTPUT ;
    USE SIGNAL ;
    PORT
      LAYER M5 ;
        RECT  39.264 0 39.288 0.084 ;
    END
  END snoop_data_o[101]
  PIN snoop_data_o[102]
    DIRECTION OUTPUT ;
    USE SIGNAL ;
    PORT
      LAYER M5 ;
        RECT  40.224 0 40.248 0.084 ;
    END
  END snoop_data_o[102]
  PIN snoop_data_o[103]
    DIRECTION OUTPUT ;
    USE SIGNAL ;
    PORT
      LAYER M5 ;
        RECT  39.456 0 39.48 0.084 ;
    END
  END snoop_data_o[103]
  PIN snoop_data_o[104]
    DIRECTION OUTPUT ;
    USE SIGNAL ;
    PORT
      LAYER M5 ;
        RECT  39.552 0 39.576 0.084 ;
    END
  END snoop_data_o[104]
  PIN snoop_data_o[105]
    DIRECTION OUTPUT ;
    USE SIGNAL ;
    PORT
      LAYER M5 ;
        RECT  41.088 0 41.112 0.084 ;
    END
  END snoop_data_o[105]
  PIN snoop_data_o[106]
    DIRECTION OUTPUT ;
    USE SIGNAL ;
    PORT
      LAYER M5 ;
        RECT  39.84 0 39.864 0.084 ;
    END
  END snoop_data_o[106]
  PIN snoop_data_o[107]
    DIRECTION OUTPUT ;
    USE SIGNAL ;
    PORT
      LAYER M5 ;
        RECT  40.704 0 40.728 0.084 ;
    END
  END snoop_data_o[107]
  PIN snoop_data_o[108]
    DIRECTION OUTPUT ;
    USE SIGNAL ;
    PORT
      LAYER M5 ;
        RECT  39.936 0 39.96 0.084 ;
    END
  END snoop_data_o[108]
  PIN snoop_data_o[109]
    DIRECTION OUTPUT ;
    USE SIGNAL ;
    PORT
      LAYER M5 ;
        RECT  40.608 0 40.632 0.084 ;
    END
  END snoop_data_o[109]
  PIN snoop_data_o[10]
    DIRECTION OUTPUT ;
    USE SIGNAL ;
    PORT
      LAYER M5 ;
        RECT  40.512 0 40.536 0.084 ;
    END
  END snoop_data_o[10]
  PIN snoop_data_o[110]
    DIRECTION OUTPUT ;
    USE SIGNAL ;
    PORT
      LAYER M5 ;
        RECT  40.896 0 40.92 0.084 ;
    END
  END snoop_data_o[110]
  PIN snoop_data_o[111]
    DIRECTION OUTPUT ;
    USE SIGNAL ;
    PORT
      LAYER M5 ;
        RECT  39.648 0 39.672 0.084 ;
    END
  END snoop_data_o[111]
  PIN snoop_data_o[112]
    DIRECTION OUTPUT ;
    USE SIGNAL ;
    PORT
      LAYER M5 ;
        RECT  41.184 0 41.208 0.084 ;
    END
  END snoop_data_o[112]
  PIN snoop_data_o[113]
    DIRECTION OUTPUT ;
    USE SIGNAL ;
    PORT
      LAYER M5 ;
        RECT  41.376 0 41.4 0.084 ;
    END
  END snoop_data_o[113]
  PIN snoop_data_o[114]
    DIRECTION OUTPUT ;
    USE SIGNAL ;
    PORT
      LAYER M5 ;
        RECT  20.16 0 20.184 0.084 ;
    END
  END snoop_data_o[114]
  PIN snoop_data_o[115]
    DIRECTION OUTPUT ;
    USE SIGNAL ;
    PORT
      LAYER M5 ;
        RECT  35.424 0 35.448 0.084 ;
    END
  END snoop_data_o[115]
  PIN snoop_data_o[116]
    DIRECTION OUTPUT ;
    USE SIGNAL ;
    PORT
      LAYER M5 ;
        RECT  35.52 0 35.544 0.084 ;
    END
  END snoop_data_o[116]
  PIN snoop_data_o[117]
    DIRECTION OUTPUT ;
    USE SIGNAL ;
    PORT
      LAYER M5 ;
        RECT  35.616 0 35.64 0.084 ;
    END
  END snoop_data_o[117]
  PIN snoop_data_o[118]
    DIRECTION OUTPUT ;
    USE SIGNAL ;
    PORT
      LAYER M5 ;
        RECT  35.712 0 35.736 0.084 ;
    END
  END snoop_data_o[118]
  PIN snoop_data_o[119]
    DIRECTION OUTPUT ;
    USE SIGNAL ;
    PORT
      LAYER M5 ;
        RECT  35.808 0 35.832 0.084 ;
    END
  END snoop_data_o[119]
  PIN snoop_data_o[11]
    DIRECTION OUTPUT ;
    USE SIGNAL ;
    PORT
      LAYER M5 ;
        RECT  41.28 0 41.304 0.084 ;
    END
  END snoop_data_o[11]
  PIN snoop_data_o[120]
    DIRECTION OUTPUT ;
    USE SIGNAL ;
    PORT
      LAYER M5 ;
        RECT  40.32 0 40.344 0.084 ;
    END
  END snoop_data_o[120]
  PIN snoop_data_o[121]
    DIRECTION OUTPUT ;
    USE SIGNAL ;
    PORT
      LAYER M5 ;
        RECT  35.904 0 35.928 0.084 ;
    END
  END snoop_data_o[121]
  PIN snoop_data_o[122]
    DIRECTION OUTPUT ;
    USE SIGNAL ;
    PORT
      LAYER M5 ;
        RECT  36 0 36.024 0.084 ;
    END
  END snoop_data_o[122]
  PIN snoop_data_o[123]
    DIRECTION OUTPUT ;
    USE SIGNAL ;
    PORT
      LAYER M5 ;
        RECT  36.096 0 36.12 0.084 ;
    END
  END snoop_data_o[123]
  PIN snoop_data_o[124]
    DIRECTION OUTPUT ;
    USE SIGNAL ;
    PORT
      LAYER M5 ;
        RECT  36.192 0 36.216 0.084 ;
    END
  END snoop_data_o[124]
  PIN snoop_data_o[125]
    DIRECTION OUTPUT ;
    USE SIGNAL ;
    PORT
      LAYER M5 ;
        RECT  36.288 0 36.312 0.084 ;
    END
  END snoop_data_o[125]
  PIN snoop_data_o[126]
    DIRECTION OUTPUT ;
    USE SIGNAL ;
    PORT
      LAYER M5 ;
        RECT  36.384 0 36.408 0.084 ;
    END
  END snoop_data_o[126]
  PIN snoop_data_o[127]
    DIRECTION OUTPUT ;
    USE SIGNAL ;
    PORT
      LAYER M5 ;
        RECT  40.416 0 40.44 0.084 ;
    END
  END snoop_data_o[127]
  PIN snoop_data_o[128]
    DIRECTION OUTPUT ;
    USE SIGNAL ;
    PORT
      LAYER M5 ;
        RECT  39.36 0 39.384 0.084 ;
    END
  END snoop_data_o[128]
  PIN snoop_data_o[129]
    DIRECTION OUTPUT ;
    USE SIGNAL ;
    PORT
      LAYER M5 ;
        RECT  40.8 0 40.824 0.084 ;
    END
  END snoop_data_o[129]
  PIN snoop_data_o[12]
    DIRECTION OUTPUT ;
    USE SIGNAL ;
    PORT
      LAYER M5 ;
        RECT  39.744 0 39.768 0.084 ;
    END
  END snoop_data_o[12]
  PIN snoop_data_o[130]
    DIRECTION OUTPUT ;
    USE SIGNAL ;
    PORT
      LAYER M5 ;
        RECT  40.032 0 40.056 0.084 ;
    END
  END snoop_data_o[130]
  PIN snoop_data_o[131]
    DIRECTION OUTPUT ;
    USE SIGNAL ;
    PORT
      LAYER M5 ;
        RECT  39.168 0 39.192 0.084 ;
    END
  END snoop_data_o[131]
  PIN snoop_data_o[132]
    DIRECTION OUTPUT ;
    USE SIGNAL ;
    PORT
      LAYER M5 ;
        RECT  36.48 0 36.504 0.084 ;
    END
  END snoop_data_o[132]
  PIN snoop_data_o[133]
    DIRECTION OUTPUT ;
    USE SIGNAL ;
    PORT
      LAYER M5 ;
        RECT  36.576 0 36.6 0.084 ;
    END
  END snoop_data_o[133]
  PIN snoop_data_o[134]
    DIRECTION OUTPUT ;
    USE SIGNAL ;
    PORT
      LAYER M5 ;
        RECT  36.672 0 36.696 0.084 ;
    END
  END snoop_data_o[134]
  PIN snoop_data_o[135]
    DIRECTION OUTPUT ;
    USE SIGNAL ;
    PORT
      LAYER M5 ;
        RECT  36.768 0 36.792 0.084 ;
    END
  END snoop_data_o[135]
  PIN snoop_data_o[136]
    DIRECTION OUTPUT ;
    USE SIGNAL ;
    PORT
      LAYER M5 ;
        RECT  36.864 0 36.888 0.084 ;
    END
  END snoop_data_o[136]
  PIN snoop_data_o[137]
    DIRECTION OUTPUT ;
    USE SIGNAL ;
    PORT
      LAYER M5 ;
        RECT  36.96 0 36.984 0.084 ;
    END
  END snoop_data_o[137]
  PIN snoop_data_o[138]
    DIRECTION OUTPUT ;
    USE SIGNAL ;
    PORT
      LAYER M5 ;
        RECT  37.056 0 37.08 0.084 ;
    END
  END snoop_data_o[138]
  PIN snoop_data_o[139]
    DIRECTION OUTPUT ;
    USE SIGNAL ;
    PORT
      LAYER M5 ;
        RECT  37.152 0 37.176 0.084 ;
    END
  END snoop_data_o[139]
  PIN snoop_data_o[13]
    DIRECTION OUTPUT ;
    USE SIGNAL ;
    PORT
      LAYER M5 ;
        RECT  37.248 0 37.272 0.084 ;
    END
  END snoop_data_o[13]
  PIN snoop_data_o[140]
    DIRECTION OUTPUT ;
    USE SIGNAL ;
    PORT
      LAYER M5 ;
        RECT  37.344 0 37.368 0.084 ;
    END
  END snoop_data_o[140]
  PIN snoop_data_o[141]
    DIRECTION OUTPUT ;
    USE SIGNAL ;
    PORT
      LAYER M5 ;
        RECT  37.44 0 37.464 0.084 ;
    END
  END snoop_data_o[141]
  PIN snoop_data_o[142]
    DIRECTION OUTPUT ;
    USE SIGNAL ;
    PORT
      LAYER M5 ;
        RECT  37.536 0 37.56 0.084 ;
    END
  END snoop_data_o[142]
  PIN snoop_data_o[143]
    DIRECTION OUTPUT ;
    USE SIGNAL ;
    PORT
      LAYER M5 ;
        RECT  37.632 0 37.656 0.084 ;
    END
  END snoop_data_o[143]
  PIN snoop_data_o[144]
    DIRECTION OUTPUT ;
    USE SIGNAL ;
    PORT
      LAYER M5 ;
        RECT  37.728 0 37.752 0.084 ;
    END
  END snoop_data_o[144]
  PIN snoop_data_o[145]
    DIRECTION OUTPUT ;
    USE SIGNAL ;
    PORT
      LAYER M5 ;
        RECT  37.824 0 37.848 0.084 ;
    END
  END snoop_data_o[145]
  PIN snoop_data_o[146]
    DIRECTION OUTPUT ;
    USE SIGNAL ;
    PORT
      LAYER M5 ;
        RECT  37.92 0 37.944 0.084 ;
    END
  END snoop_data_o[146]
  PIN snoop_data_o[147]
    DIRECTION OUTPUT ;
    USE SIGNAL ;
    PORT
      LAYER M5 ;
        RECT  38.016 0 38.04 0.084 ;
    END
  END snoop_data_o[147]
  PIN snoop_data_o[148]
    DIRECTION OUTPUT ;
    USE SIGNAL ;
    PORT
      LAYER M5 ;
        RECT  38.112 0 38.136 0.084 ;
    END
  END snoop_data_o[148]
  PIN snoop_data_o[149]
    DIRECTION OUTPUT ;
    USE SIGNAL ;
    PORT
      LAYER M5 ;
        RECT  38.208 0 38.232 0.084 ;
    END
  END snoop_data_o[149]
  PIN snoop_data_o[14]
    DIRECTION OUTPUT ;
    USE SIGNAL ;
    PORT
      LAYER M5 ;
        RECT  38.304 0 38.328 0.084 ;
    END
  END snoop_data_o[14]
  PIN snoop_data_o[150]
    DIRECTION OUTPUT ;
    USE SIGNAL ;
    PORT
      LAYER M5 ;
        RECT  38.4 0 38.424 0.084 ;
    END
  END snoop_data_o[150]
  PIN snoop_data_o[151]
    DIRECTION OUTPUT ;
    USE SIGNAL ;
    PORT
      LAYER M5 ;
        RECT  38.496 0 38.52 0.084 ;
    END
  END snoop_data_o[151]
  PIN snoop_data_o[152]
    DIRECTION OUTPUT ;
    USE SIGNAL ;
    PORT
      LAYER M5 ;
        RECT  38.592 0 38.616 0.084 ;
    END
  END snoop_data_o[152]
  PIN snoop_data_o[153]
    DIRECTION OUTPUT ;
    USE SIGNAL ;
    PORT
      LAYER M5 ;
        RECT  38.688 0 38.712 0.084 ;
    END
  END snoop_data_o[153]
  PIN snoop_data_o[154]
    DIRECTION OUTPUT ;
    USE SIGNAL ;
    PORT
      LAYER M5 ;
        RECT  38.784 0 38.808 0.084 ;
    END
  END snoop_data_o[154]
  PIN snoop_data_o[155]
    DIRECTION OUTPUT ;
    USE SIGNAL ;
    PORT
      LAYER M5 ;
        RECT  38.88 0 38.904 0.084 ;
    END
  END snoop_data_o[155]
  PIN snoop_data_o[156]
    DIRECTION OUTPUT ;
    USE SIGNAL ;
    PORT
      LAYER M5 ;
        RECT  38.976 0 39 0.084 ;
    END
  END snoop_data_o[156]
  PIN snoop_data_o[157]
    DIRECTION OUTPUT ;
    USE SIGNAL ;
    PORT
      LAYER M5 ;
        RECT  39.072 0 39.096 0.084 ;
    END
  END snoop_data_o[157]
  PIN snoop_data_o[158]
    DIRECTION OUTPUT ;
    USE SIGNAL ;
    PORT
      LAYER M5 ;
        RECT  35.328 0 35.352 0.084 ;
    END
  END snoop_data_o[158]
  PIN snoop_data_o[159]
    DIRECTION OUTPUT ;
    USE SIGNAL ;
    PORT
      LAYER M5 ;
        RECT  35.232 0 35.256 0.084 ;
    END
  END snoop_data_o[159]
  PIN snoop_data_o[15]
    DIRECTION OUTPUT ;
    USE SIGNAL ;
    PORT
      LAYER M5 ;
        RECT  35.136 0 35.16 0.084 ;
    END
  END snoop_data_o[15]
  PIN snoop_data_o[160]
    DIRECTION OUTPUT ;
    USE SIGNAL ;
    PORT
      LAYER M5 ;
        RECT  35.04 0 35.064 0.084 ;
    END
  END snoop_data_o[160]
  PIN snoop_data_o[161]
    DIRECTION OUTPUT ;
    USE SIGNAL ;
    PORT
      LAYER M5 ;
        RECT  34.944 0 34.968 0.084 ;
    END
  END snoop_data_o[161]
  PIN snoop_data_o[162]
    DIRECTION OUTPUT ;
    USE SIGNAL ;
    PORT
      LAYER M5 ;
        RECT  34.848 0 34.872 0.084 ;
    END
  END snoop_data_o[162]
  PIN snoop_data_o[163]
    DIRECTION OUTPUT ;
    USE SIGNAL ;
    PORT
      LAYER M5 ;
        RECT  34.752 0 34.776 0.084 ;
    END
  END snoop_data_o[163]
  PIN snoop_data_o[164]
    DIRECTION OUTPUT ;
    USE SIGNAL ;
    PORT
      LAYER M5 ;
        RECT  34.656 0 34.68 0.084 ;
    END
  END snoop_data_o[164]
  PIN snoop_data_o[165]
    DIRECTION OUTPUT ;
    USE SIGNAL ;
    PORT
      LAYER M5 ;
        RECT  34.56 0 34.584 0.084 ;
    END
  END snoop_data_o[165]
  PIN snoop_data_o[166]
    DIRECTION OUTPUT ;
    USE SIGNAL ;
    PORT
      LAYER M5 ;
        RECT  34.464 0 34.488 0.084 ;
    END
  END snoop_data_o[166]
  PIN snoop_data_o[167]
    DIRECTION OUTPUT ;
    USE SIGNAL ;
    PORT
      LAYER M5 ;
        RECT  34.368 0 34.392 0.084 ;
    END
  END snoop_data_o[167]
  PIN snoop_data_o[168]
    DIRECTION OUTPUT ;
    USE SIGNAL ;
    PORT
      LAYER M5 ;
        RECT  34.272 0 34.296 0.084 ;
    END
  END snoop_data_o[168]
  PIN snoop_data_o[169]
    DIRECTION OUTPUT ;
    USE SIGNAL ;
    PORT
      LAYER M5 ;
        RECT  34.176 0 34.2 0.084 ;
    END
  END snoop_data_o[169]
  PIN snoop_data_o[16]
    DIRECTION OUTPUT ;
    USE SIGNAL ;
    PORT
      LAYER M5 ;
        RECT  34.08 0 34.104 0.084 ;
    END
  END snoop_data_o[16]
  PIN snoop_data_o[170]
    DIRECTION OUTPUT ;
    USE SIGNAL ;
    PORT
      LAYER M5 ;
        RECT  33.984 0 34.008 0.084 ;
    END
  END snoop_data_o[170]
  PIN snoop_data_o[171]
    DIRECTION OUTPUT ;
    USE SIGNAL ;
    PORT
      LAYER M5 ;
        RECT  33.888 0 33.912 0.084 ;
    END
  END snoop_data_o[171]
  PIN snoop_data_o[172]
    DIRECTION OUTPUT ;
    USE SIGNAL ;
    PORT
      LAYER M5 ;
        RECT  33.792 0 33.816 0.084 ;
    END
  END snoop_data_o[172]
  PIN snoop_data_o[173]
    DIRECTION OUTPUT ;
    USE SIGNAL ;
    PORT
      LAYER M5 ;
        RECT  33.696 0 33.72 0.084 ;
    END
  END snoop_data_o[173]
  PIN snoop_data_o[174]
    DIRECTION OUTPUT ;
    USE SIGNAL ;
    PORT
      LAYER M5 ;
        RECT  33.6 0 33.624 0.084 ;
    END
  END snoop_data_o[174]
  PIN snoop_data_o[175]
    DIRECTION OUTPUT ;
    USE SIGNAL ;
    PORT
      LAYER M5 ;
        RECT  33.504 0 33.528 0.084 ;
    END
  END snoop_data_o[175]
  PIN snoop_data_o[176]
    DIRECTION OUTPUT ;
    USE SIGNAL ;
    PORT
      LAYER M5 ;
        RECT  33.408 0 33.432 0.084 ;
    END
  END snoop_data_o[176]
  PIN snoop_data_o[177]
    DIRECTION OUTPUT ;
    USE SIGNAL ;
    PORT
      LAYER M5 ;
        RECT  33.312 0 33.336 0.084 ;
    END
  END snoop_data_o[177]
  PIN snoop_data_o[178]
    DIRECTION OUTPUT ;
    USE SIGNAL ;
    PORT
      LAYER M5 ;
        RECT  33.216 0 33.24 0.084 ;
    END
  END snoop_data_o[178]
  PIN snoop_data_o[179]
    DIRECTION OUTPUT ;
    USE SIGNAL ;
    PORT
      LAYER M5 ;
        RECT  33.12 0 33.144 0.084 ;
    END
  END snoop_data_o[179]
  PIN snoop_data_o[17]
    DIRECTION OUTPUT ;
    USE SIGNAL ;
    PORT
      LAYER M5 ;
        RECT  33.024 0 33.048 0.084 ;
    END
  END snoop_data_o[17]
  PIN snoop_data_o[180]
    DIRECTION OUTPUT ;
    USE SIGNAL ;
    PORT
      LAYER M5 ;
        RECT  32.928 0 32.952 0.084 ;
    END
  END snoop_data_o[180]
  PIN snoop_data_o[181]
    DIRECTION OUTPUT ;
    USE SIGNAL ;
    PORT
      LAYER M5 ;
        RECT  32.832 0 32.856 0.084 ;
    END
  END snoop_data_o[181]
  PIN snoop_data_o[182]
    DIRECTION OUTPUT ;
    USE SIGNAL ;
    PORT
      LAYER M5 ;
        RECT  32.736 0 32.76 0.084 ;
    END
  END snoop_data_o[182]
  PIN snoop_data_o[183]
    DIRECTION OUTPUT ;
    USE SIGNAL ;
    PORT
      LAYER M5 ;
        RECT  32.64 0 32.664 0.084 ;
    END
  END snoop_data_o[183]
  PIN snoop_data_o[184]
    DIRECTION OUTPUT ;
    USE SIGNAL ;
    PORT
      LAYER M5 ;
        RECT  32.544 0 32.568 0.084 ;
    END
  END snoop_data_o[184]
  PIN snoop_data_o[185]
    DIRECTION OUTPUT ;
    USE SIGNAL ;
    PORT
      LAYER M5 ;
        RECT  32.448 0 32.472 0.084 ;
    END
  END snoop_data_o[185]
  PIN snoop_data_o[186]
    DIRECTION OUTPUT ;
    USE SIGNAL ;
    PORT
      LAYER M5 ;
        RECT  32.352 0 32.376 0.084 ;
    END
  END snoop_data_o[186]
  PIN snoop_data_o[187]
    DIRECTION OUTPUT ;
    USE SIGNAL ;
    PORT
      LAYER M5 ;
        RECT  32.256 0 32.28 0.084 ;
    END
  END snoop_data_o[187]
  PIN snoop_data_o[188]
    DIRECTION OUTPUT ;
    USE SIGNAL ;
    PORT
      LAYER M5 ;
        RECT  32.16 0 32.184 0.084 ;
    END
  END snoop_data_o[188]
  PIN snoop_data_o[189]
    DIRECTION OUTPUT ;
    USE SIGNAL ;
    PORT
      LAYER M5 ;
        RECT  32.064 0 32.088 0.084 ;
    END
  END snoop_data_o[189]
  PIN snoop_data_o[18]
    DIRECTION OUTPUT ;
    USE SIGNAL ;
    PORT
      LAYER M5 ;
        RECT  31.968 0 31.992 0.084 ;
    END
  END snoop_data_o[18]
  PIN snoop_data_o[190]
    DIRECTION OUTPUT ;
    USE SIGNAL ;
    PORT
      LAYER M5 ;
        RECT  31.872 0 31.896 0.084 ;
    END
  END snoop_data_o[190]
  PIN snoop_data_o[191]
    DIRECTION OUTPUT ;
    USE SIGNAL ;
    PORT
      LAYER M5 ;
        RECT  31.776 0 31.8 0.084 ;
    END
  END snoop_data_o[191]
  PIN snoop_data_o[192]
    DIRECTION OUTPUT ;
    USE SIGNAL ;
    PORT
      LAYER M5 ;
        RECT  31.68 0 31.704 0.084 ;
    END
  END snoop_data_o[192]
  PIN snoop_data_o[193]
    DIRECTION OUTPUT ;
    USE SIGNAL ;
    PORT
      LAYER M5 ;
        RECT  31.584 0 31.608 0.084 ;
    END
  END snoop_data_o[193]
  PIN snoop_data_o[194]
    DIRECTION OUTPUT ;
    USE SIGNAL ;
    PORT
      LAYER M5 ;
        RECT  31.488 0 31.512 0.084 ;
    END
  END snoop_data_o[194]
  PIN snoop_data_o[195]
    DIRECTION OUTPUT ;
    USE SIGNAL ;
    PORT
      LAYER M5 ;
        RECT  31.392 0 31.416 0.084 ;
    END
  END snoop_data_o[195]
  PIN snoop_data_o[196]
    DIRECTION OUTPUT ;
    USE SIGNAL ;
    PORT
      LAYER M5 ;
        RECT  31.296 0 31.32 0.084 ;
    END
  END snoop_data_o[196]
  PIN snoop_data_o[197]
    DIRECTION OUTPUT ;
    USE SIGNAL ;
    PORT
      LAYER M5 ;
        RECT  31.2 0 31.224 0.084 ;
    END
  END snoop_data_o[197]
  PIN snoop_data_o[198]
    DIRECTION OUTPUT ;
    USE SIGNAL ;
    PORT
      LAYER M5 ;
        RECT  31.104 0 31.128 0.084 ;
    END
  END snoop_data_o[198]
  PIN snoop_data_o[199]
    DIRECTION OUTPUT ;
    USE SIGNAL ;
    PORT
      LAYER M5 ;
        RECT  31.008 0 31.032 0.084 ;
    END
  END snoop_data_o[199]
  PIN snoop_data_o[19]
    DIRECTION OUTPUT ;
    USE SIGNAL ;
    PORT
      LAYER M5 ;
        RECT  30.912 0 30.936 0.084 ;
    END
  END snoop_data_o[19]
  PIN snoop_data_o[1]
    DIRECTION OUTPUT ;
    USE SIGNAL ;
    PORT
      LAYER M5 ;
        RECT  30.816 0 30.84 0.084 ;
    END
  END snoop_data_o[1]
  PIN snoop_data_o[200]
    DIRECTION OUTPUT ;
    USE SIGNAL ;
    PORT
      LAYER M5 ;
        RECT  30.72 0 30.744 0.084 ;
    END
  END snoop_data_o[200]
  PIN snoop_data_o[201]
    DIRECTION OUTPUT ;
    USE SIGNAL ;
    PORT
      LAYER M5 ;
        RECT  30.624 0 30.648 0.084 ;
    END
  END snoop_data_o[201]
  PIN snoop_data_o[202]
    DIRECTION OUTPUT ;
    USE SIGNAL ;
    PORT
      LAYER M5 ;
        RECT  30.528 0 30.552 0.084 ;
    END
  END snoop_data_o[202]
  PIN snoop_data_o[203]
    DIRECTION OUTPUT ;
    USE SIGNAL ;
    PORT
      LAYER M5 ;
        RECT  30.432 0 30.456 0.084 ;
    END
  END snoop_data_o[203]
  PIN snoop_data_o[204]
    DIRECTION OUTPUT ;
    USE SIGNAL ;
    PORT
      LAYER M5 ;
        RECT  30.336 0 30.36 0.084 ;
    END
  END snoop_data_o[204]
  PIN snoop_data_o[205]
    DIRECTION OUTPUT ;
    USE SIGNAL ;
    PORT
      LAYER M5 ;
        RECT  30.24 0 30.264 0.084 ;
    END
  END snoop_data_o[205]
  PIN snoop_data_o[206]
    DIRECTION OUTPUT ;
    USE SIGNAL ;
    PORT
      LAYER M5 ;
        RECT  30.144 0 30.168 0.084 ;
    END
  END snoop_data_o[206]
  PIN snoop_data_o[207]
    DIRECTION OUTPUT ;
    USE SIGNAL ;
    PORT
      LAYER M5 ;
        RECT  30.048 0 30.072 0.084 ;
    END
  END snoop_data_o[207]
  PIN snoop_data_o[208]
    DIRECTION OUTPUT ;
    USE SIGNAL ;
    PORT
      LAYER M5 ;
        RECT  29.952 0 29.976 0.084 ;
    END
  END snoop_data_o[208]
  PIN snoop_data_o[209]
    DIRECTION OUTPUT ;
    USE SIGNAL ;
    PORT
      LAYER M5 ;
        RECT  29.856 0 29.88 0.084 ;
    END
  END snoop_data_o[209]
  PIN snoop_data_o[20]
    DIRECTION OUTPUT ;
    USE SIGNAL ;
    PORT
      LAYER M5 ;
        RECT  29.76 0 29.784 0.084 ;
    END
  END snoop_data_o[20]
  PIN snoop_data_o[210]
    DIRECTION OUTPUT ;
    USE SIGNAL ;
    PORT
      LAYER M5 ;
        RECT  29.664 0 29.688 0.084 ;
    END
  END snoop_data_o[210]
  PIN snoop_data_o[211]
    DIRECTION OUTPUT ;
    USE SIGNAL ;
    PORT
      LAYER M5 ;
        RECT  29.568 0 29.592 0.084 ;
    END
  END snoop_data_o[211]
  PIN snoop_data_o[212]
    DIRECTION OUTPUT ;
    USE SIGNAL ;
    PORT
      LAYER M5 ;
        RECT  29.472 0 29.496 0.084 ;
    END
  END snoop_data_o[212]
  PIN snoop_data_o[213]
    DIRECTION OUTPUT ;
    USE SIGNAL ;
    PORT
      LAYER M5 ;
        RECT  29.376 0 29.4 0.084 ;
    END
  END snoop_data_o[213]
  PIN snoop_data_o[214]
    DIRECTION OUTPUT ;
    USE SIGNAL ;
    PORT
      LAYER M5 ;
        RECT  29.28 0 29.304 0.084 ;
    END
  END snoop_data_o[214]
  PIN snoop_data_o[215]
    DIRECTION OUTPUT ;
    USE SIGNAL ;
    PORT
      LAYER M5 ;
        RECT  29.184 0 29.208 0.084 ;
    END
  END snoop_data_o[215]
  PIN snoop_data_o[216]
    DIRECTION OUTPUT ;
    USE SIGNAL ;
    PORT
      LAYER M4 ;
        RECT  0 34.944 0.084 34.968 ;
    END
  END snoop_data_o[216]
  PIN snoop_data_o[217]
    DIRECTION OUTPUT ;
    USE SIGNAL ;
    PORT
      LAYER M4 ;
        RECT  0 35.328 0.084 35.352 ;
    END
  END snoop_data_o[217]
  PIN snoop_data_o[218]
    DIRECTION OUTPUT ;
    USE SIGNAL ;
    PORT
      LAYER M4 ;
        RECT  0 35.616 0.084 35.64 ;
    END
  END snoop_data_o[218]
  PIN snoop_data_o[219]
    DIRECTION OUTPUT ;
    USE SIGNAL ;
    PORT
      LAYER M4 ;
        RECT  0 34.656 0.084 34.68 ;
    END
  END snoop_data_o[219]
  PIN snoop_data_o[21]
    DIRECTION OUTPUT ;
    USE SIGNAL ;
    PORT
      LAYER M5 ;
        RECT  29.088 0 29.112 0.084 ;
    END
  END snoop_data_o[21]
  PIN snoop_data_o[220]
    DIRECTION OUTPUT ;
    USE SIGNAL ;
    PORT
      LAYER M4 ;
        RECT  0 35.232 0.084 35.256 ;
    END
  END snoop_data_o[220]
  PIN snoop_data_o[221]
    DIRECTION OUTPUT ;
    USE SIGNAL ;
    PORT
      LAYER M4 ;
        RECT  0 34.56 0.084 34.584 ;
    END
  END snoop_data_o[221]
  PIN snoop_data_o[222]
    DIRECTION OUTPUT ;
    USE SIGNAL ;
    PORT
      LAYER M4 ;
        RECT  0 34.368 0.084 34.392 ;
    END
  END snoop_data_o[222]
  PIN snoop_data_o[223]
    DIRECTION OUTPUT ;
    USE SIGNAL ;
    PORT
      LAYER M5 ;
        RECT  28.992 0 29.016 0.084 ;
    END
  END snoop_data_o[223]
  PIN snoop_data_o[224]
    DIRECTION OUTPUT ;
    USE SIGNAL ;
    PORT
      LAYER M5 ;
        RECT  28.896 0 28.92 0.084 ;
    END
  END snoop_data_o[224]
  PIN snoop_data_o[225]
    DIRECTION OUTPUT ;
    USE SIGNAL ;
    PORT
      LAYER M4 ;
        RECT  0 34.752 0.084 34.776 ;
    END
  END snoop_data_o[225]
  PIN snoop_data_o[226]
    DIRECTION OUTPUT ;
    USE SIGNAL ;
    PORT
      LAYER M4 ;
        RECT  0 34.464 0.084 34.488 ;
    END
  END snoop_data_o[226]
  PIN snoop_data_o[227]
    DIRECTION OUTPUT ;
    USE SIGNAL ;
    PORT
      LAYER M4 ;
        RECT  0 34.848 0.084 34.872 ;
    END
  END snoop_data_o[227]
  PIN snoop_data_o[228]
    DIRECTION OUTPUT ;
    USE SIGNAL ;
    PORT
      LAYER M4 ;
        RECT  0 35.04 0.084 35.064 ;
    END
  END snoop_data_o[228]
  PIN snoop_data_o[229]
    DIRECTION OUTPUT ;
    USE SIGNAL ;
    PORT
      LAYER M4 ;
        RECT  0 35.424 0.084 35.448 ;
    END
  END snoop_data_o[229]
  PIN snoop_data_o[22]
    DIRECTION OUTPUT ;
    USE SIGNAL ;
    PORT
      LAYER M5 ;
        RECT  28.8 0 28.824 0.084 ;
    END
  END snoop_data_o[22]
  PIN snoop_data_o[230]
    DIRECTION OUTPUT ;
    USE SIGNAL ;
    PORT
      LAYER M4 ;
        RECT  0 35.136 0.084 35.16 ;
    END
  END snoop_data_o[230]
  PIN snoop_data_o[231]
    DIRECTION OUTPUT ;
    USE SIGNAL ;
    PORT
      LAYER M5 ;
        RECT  28.704 0 28.728 0.084 ;
    END
  END snoop_data_o[231]
  PIN snoop_data_o[232]
    DIRECTION OUTPUT ;
    USE SIGNAL ;
    PORT
      LAYER M5 ;
        RECT  28.608 0 28.632 0.084 ;
    END
  END snoop_data_o[232]
  PIN snoop_data_o[233]
    DIRECTION OUTPUT ;
    USE SIGNAL ;
    PORT
      LAYER M4 ;
        RECT  0 35.904 0.084 35.928 ;
    END
  END snoop_data_o[233]
  PIN snoop_data_o[234]
    DIRECTION OUTPUT ;
    USE SIGNAL ;
    PORT
      LAYER M4 ;
        RECT  0 35.808 0.084 35.832 ;
    END
  END snoop_data_o[234]
  PIN snoop_data_o[235]
    DIRECTION OUTPUT ;
    USE SIGNAL ;
    PORT
      LAYER M4 ;
        RECT  0 36 0.084 36.024 ;
    END
  END snoop_data_o[235]
  PIN snoop_data_o[236]
    DIRECTION OUTPUT ;
    USE SIGNAL ;
    PORT
      LAYER M5 ;
        RECT  28.512 0 28.536 0.084 ;
    END
  END snoop_data_o[236]
  PIN snoop_data_o[237]
    DIRECTION OUTPUT ;
    USE SIGNAL ;
    PORT
      LAYER M4 ;
        RECT  0 36.288 0.084 36.312 ;
    END
  END snoop_data_o[237]
  PIN snoop_data_o[238]
    DIRECTION OUTPUT ;
    USE SIGNAL ;
    PORT
      LAYER M4 ;
        RECT  0 36.48 0.084 36.504 ;
    END
  END snoop_data_o[238]
  PIN snoop_data_o[239]
    DIRECTION OUTPUT ;
    USE SIGNAL ;
    PORT
      LAYER M5 ;
        RECT  28.416 0 28.44 0.084 ;
    END
  END snoop_data_o[239]
  PIN snoop_data_o[23]
    DIRECTION OUTPUT ;
    USE SIGNAL ;
    PORT
      LAYER M5 ;
        RECT  28.32 0 28.344 0.084 ;
    END
  END snoop_data_o[23]
  PIN snoop_data_o[240]
    DIRECTION OUTPUT ;
    USE SIGNAL ;
    PORT
      LAYER M4 ;
        RECT  0 36.768 0.084 36.792 ;
    END
  END snoop_data_o[240]
  PIN snoop_data_o[241]
    DIRECTION OUTPUT ;
    USE SIGNAL ;
    PORT
      LAYER M4 ;
        RECT  0 36.864 0.084 36.888 ;
    END
  END snoop_data_o[241]
  PIN snoop_data_o[242]
    DIRECTION OUTPUT ;
    USE SIGNAL ;
    PORT
      LAYER M4 ;
        RECT  0 37.056 0.084 37.08 ;
    END
  END snoop_data_o[242]
  PIN snoop_data_o[243]
    DIRECTION OUTPUT ;
    USE SIGNAL ;
    PORT
      LAYER M4 ;
        RECT  0 37.152 0.084 37.176 ;
    END
  END snoop_data_o[243]
  PIN snoop_data_o[244]
    DIRECTION OUTPUT ;
    USE SIGNAL ;
    PORT
      LAYER M4 ;
        RECT  0 37.536 0.084 37.56 ;
    END
  END snoop_data_o[244]
  PIN snoop_data_o[245]
    DIRECTION OUTPUT ;
    USE SIGNAL ;
    PORT
      LAYER M4 ;
        RECT  0 37.344 0.084 37.368 ;
    END
  END snoop_data_o[245]
  PIN snoop_data_o[246]
    DIRECTION OUTPUT ;
    USE SIGNAL ;
    PORT
      LAYER M4 ;
        RECT  0 37.44 0.084 37.464 ;
    END
  END snoop_data_o[246]
  PIN snoop_data_o[247]
    DIRECTION OUTPUT ;
    USE SIGNAL ;
    PORT
      LAYER M4 ;
        RECT  0 37.248 0.084 37.272 ;
    END
  END snoop_data_o[247]
  PIN snoop_data_o[248]
    DIRECTION OUTPUT ;
    USE SIGNAL ;
    PORT
      LAYER M4 ;
        RECT  0 37.728 0.084 37.752 ;
    END
  END snoop_data_o[248]
  PIN snoop_data_o[249]
    DIRECTION OUTPUT ;
    USE SIGNAL ;
    PORT
      LAYER M4 ;
        RECT  0 37.824 0.084 37.848 ;
    END
  END snoop_data_o[249]
  PIN snoop_data_o[24]
    DIRECTION OUTPUT ;
    USE SIGNAL ;
    PORT
      LAYER M5 ;
        RECT  28.224 0 28.248 0.084 ;
    END
  END snoop_data_o[24]
  PIN snoop_data_o[250]
    DIRECTION OUTPUT ;
    USE SIGNAL ;
    PORT
      LAYER M4 ;
        RECT  0 37.92 0.084 37.944 ;
    END
  END snoop_data_o[250]
  PIN snoop_data_o[251]
    DIRECTION OUTPUT ;
    USE SIGNAL ;
    PORT
      LAYER M4 ;
        RECT  0 48.192 0.084 48.216 ;
    END
  END snoop_data_o[251]
  PIN snoop_data_o[252]
    DIRECTION OUTPUT ;
    USE SIGNAL ;
    PORT
      LAYER M4 ;
        RECT  0 48.096 0.084 48.12 ;
    END
  END snoop_data_o[252]
  PIN snoop_data_o[253]
    DIRECTION OUTPUT ;
    USE SIGNAL ;
    PORT
      LAYER M4 ;
        RECT  0 48 0.084 48.024 ;
    END
  END snoop_data_o[253]
  PIN snoop_data_o[254]
    DIRECTION OUTPUT ;
    USE SIGNAL ;
    PORT
      LAYER M4 ;
        RECT  0 47.904 0.084 47.928 ;
    END
  END snoop_data_o[254]
  PIN snoop_data_o[255]
    DIRECTION OUTPUT ;
    USE SIGNAL ;
    PORT
      LAYER M4 ;
        RECT  0 47.808 0.084 47.832 ;
    END
  END snoop_data_o[255]
  PIN snoop_data_o[256]
    DIRECTION OUTPUT ;
    USE SIGNAL ;
    PORT
      LAYER M5 ;
        RECT  109.536 0 109.56 0.084 ;
    END
  END snoop_data_o[256]
  PIN snoop_data_o[257]
    DIRECTION OUTPUT ;
    USE SIGNAL ;
    PORT
      LAYER M5 ;
        RECT  109.92 0 109.944 0.084 ;
    END
  END snoop_data_o[257]
  PIN snoop_data_o[258]
    DIRECTION OUTPUT ;
    USE SIGNAL ;
    PORT
      LAYER M5 ;
        RECT  109.728 0 109.752 0.084 ;
    END
  END snoop_data_o[258]
  PIN snoop_data_o[259]
    DIRECTION OUTPUT ;
    USE SIGNAL ;
    PORT
      LAYER M5 ;
        RECT  109.632 0 109.656 0.084 ;
    END
  END snoop_data_o[259]
  PIN snoop_data_o[25]
    DIRECTION OUTPUT ;
    USE SIGNAL ;
    PORT
      LAYER M5 ;
        RECT  28.128 0 28.152 0.084 ;
    END
  END snoop_data_o[25]
  PIN snoop_data_o[260]
    DIRECTION OUTPUT ;
    USE SIGNAL ;
    PORT
      LAYER M5 ;
        RECT  109.824 0 109.848 0.084 ;
    END
  END snoop_data_o[260]
  PIN snoop_data_o[261]
    DIRECTION OUTPUT ;
    USE SIGNAL ;
    PORT
      LAYER M5 ;
        RECT  110.208 0 110.232 0.084 ;
    END
  END snoop_data_o[261]
  PIN snoop_data_o[262]
    DIRECTION OUTPUT ;
    USE SIGNAL ;
    PORT
      LAYER M5 ;
        RECT  113.76 0 113.784 0.084 ;
    END
  END snoop_data_o[262]
  PIN snoop_data_o[263]
    DIRECTION OUTPUT ;
    USE SIGNAL ;
    PORT
      LAYER M5 ;
        RECT  115.104 0 115.128 0.084 ;
    END
  END snoop_data_o[263]
  PIN snoop_data_o[264]
    DIRECTION OUTPUT ;
    USE SIGNAL ;
    PORT
      LAYER M5 ;
        RECT  110.592 0 110.616 0.084 ;
    END
  END snoop_data_o[264]
  PIN snoop_data_o[265]
    DIRECTION OUTPUT ;
    USE SIGNAL ;
    PORT
      LAYER M5 ;
        RECT  114.528 0 114.552 0.084 ;
    END
  END snoop_data_o[265]
  PIN snoop_data_o[266]
    DIRECTION OUTPUT ;
    USE SIGNAL ;
    PORT
      LAYER M5 ;
        RECT  111.936 0 111.96 0.084 ;
    END
  END snoop_data_o[266]
  PIN snoop_data_o[267]
    DIRECTION OUTPUT ;
    USE SIGNAL ;
    PORT
      LAYER M5 ;
        RECT  115.296 0 115.32 0.084 ;
    END
  END snoop_data_o[267]
  PIN snoop_data_o[268]
    DIRECTION OUTPUT ;
    USE SIGNAL ;
    PORT
      LAYER M5 ;
        RECT  113.184 0 113.208 0.084 ;
    END
  END snoop_data_o[268]
  PIN snoop_data_o[269]
    DIRECTION OUTPUT ;
    USE SIGNAL ;
    PORT
      LAYER M5 ;
        RECT  114.336 0 114.36 0.084 ;
    END
  END snoop_data_o[269]
  PIN snoop_data_o[26]
    DIRECTION OUTPUT ;
    USE SIGNAL ;
    PORT
      LAYER M5 ;
        RECT  28.032 0 28.056 0.084 ;
    END
  END snoop_data_o[26]
  PIN snoop_data_o[270]
    DIRECTION OUTPUT ;
    USE SIGNAL ;
    PORT
      LAYER M5 ;
        RECT  110.496 0 110.52 0.084 ;
    END
  END snoop_data_o[270]
  PIN snoop_data_o[271]
    DIRECTION OUTPUT ;
    USE SIGNAL ;
    PORT
      LAYER M5 ;
        RECT  111.072 0 111.096 0.084 ;
    END
  END snoop_data_o[271]
  PIN snoop_data_o[272]
    DIRECTION OUTPUT ;
    USE SIGNAL ;
    PORT
      LAYER M5 ;
        RECT  113.088 0 113.112 0.084 ;
    END
  END snoop_data_o[272]
  PIN snoop_data_o[273]
    DIRECTION OUTPUT ;
    USE SIGNAL ;
    PORT
      LAYER M5 ;
        RECT  115.2 0 115.224 0.084 ;
    END
  END snoop_data_o[273]
  PIN snoop_data_o[274]
    DIRECTION OUTPUT ;
    USE SIGNAL ;
    PORT
      LAYER M5 ;
        RECT  115.392 0 115.416 0.084 ;
    END
  END snoop_data_o[274]
  PIN snoop_data_o[275]
    DIRECTION OUTPUT ;
    USE SIGNAL ;
    PORT
      LAYER M5 ;
        RECT  113.568 0 113.592 0.084 ;
    END
  END snoop_data_o[275]
  PIN snoop_data_o[276]
    DIRECTION OUTPUT ;
    USE SIGNAL ;
    PORT
      LAYER M5 ;
        RECT  111.84 0 111.864 0.084 ;
    END
  END snoop_data_o[276]
  PIN snoop_data_o[277]
    DIRECTION OUTPUT ;
    USE SIGNAL ;
    PORT
      LAYER M5 ;
        RECT  115.488 0 115.512 0.084 ;
    END
  END snoop_data_o[277]
  PIN snoop_data_o[278]
    DIRECTION OUTPUT ;
    USE SIGNAL ;
    PORT
      LAYER M5 ;
        RECT  111.744 0 111.768 0.084 ;
    END
  END snoop_data_o[278]
  PIN snoop_data_o[279]
    DIRECTION OUTPUT ;
    USE SIGNAL ;
    PORT
      LAYER M5 ;
        RECT  112.224 0 112.248 0.084 ;
    END
  END snoop_data_o[279]
  PIN snoop_data_o[27]
    DIRECTION OUTPUT ;
    USE SIGNAL ;
    PORT
      LAYER M5 ;
        RECT  27.936 0 27.96 0.084 ;
    END
  END snoop_data_o[27]
  PIN snoop_data_o[280]
    DIRECTION OUTPUT ;
    USE SIGNAL ;
    PORT
      LAYER M5 ;
        RECT  110.304 0 110.328 0.084 ;
    END
  END snoop_data_o[280]
  PIN snoop_data_o[281]
    DIRECTION OUTPUT ;
    USE SIGNAL ;
    PORT
      LAYER M5 ;
        RECT  111.552 0 111.576 0.084 ;
    END
  END snoop_data_o[281]
  PIN snoop_data_o[282]
    DIRECTION OUTPUT ;
    USE SIGNAL ;
    PORT
      LAYER M5 ;
        RECT  115.008 0 115.032 0.084 ;
    END
  END snoop_data_o[282]
  PIN snoop_data_o[283]
    DIRECTION OUTPUT ;
    USE SIGNAL ;
    PORT
      LAYER M5 ;
        RECT  111.168 0 111.192 0.084 ;
    END
  END snoop_data_o[283]
  PIN snoop_data_o[284]
    DIRECTION OUTPUT ;
    USE SIGNAL ;
    PORT
      LAYER M5 ;
        RECT  110.4 0 110.424 0.084 ;
    END
  END snoop_data_o[284]
  PIN snoop_data_o[285]
    DIRECTION OUTPUT ;
    USE SIGNAL ;
    PORT
      LAYER M5 ;
        RECT  110.112 0 110.136 0.084 ;
    END
  END snoop_data_o[285]
  PIN snoop_data_o[286]
    DIRECTION OUTPUT ;
    USE SIGNAL ;
    PORT
      LAYER M5 ;
        RECT  110.688 0 110.712 0.084 ;
    END
  END snoop_data_o[286]
  PIN snoop_data_o[287]
    DIRECTION OUTPUT ;
    USE SIGNAL ;
    PORT
      LAYER M5 ;
        RECT  112.128 0 112.152 0.084 ;
    END
  END snoop_data_o[287]
  PIN snoop_data_o[288]
    DIRECTION OUTPUT ;
    USE SIGNAL ;
    PORT
      LAYER M5 ;
        RECT  113.28 0 113.304 0.084 ;
    END
  END snoop_data_o[288]
  PIN snoop_data_o[289]
    DIRECTION OUTPUT ;
    USE SIGNAL ;
    PORT
      LAYER M5 ;
        RECT  110.88 0 110.904 0.084 ;
    END
  END snoop_data_o[289]
  PIN snoop_data_o[28]
    DIRECTION OUTPUT ;
    USE SIGNAL ;
    PORT
      LAYER M5 ;
        RECT  27.84 0 27.864 0.084 ;
    END
  END snoop_data_o[28]
  PIN snoop_data_o[290]
    DIRECTION OUTPUT ;
    USE SIGNAL ;
    PORT
      LAYER M5 ;
        RECT  112.512 0 112.536 0.084 ;
    END
  END snoop_data_o[290]
  PIN snoop_data_o[291]
    DIRECTION OUTPUT ;
    USE SIGNAL ;
    PORT
      LAYER M5 ;
        RECT  112.416 0 112.44 0.084 ;
    END
  END snoop_data_o[291]
  PIN snoop_data_o[292]
    DIRECTION OUTPUT ;
    USE SIGNAL ;
    PORT
      LAYER M5 ;
        RECT  111.456 0 111.48 0.084 ;
    END
  END snoop_data_o[292]
  PIN snoop_data_o[293]
    DIRECTION OUTPUT ;
    USE SIGNAL ;
    PORT
      LAYER M5 ;
        RECT  114.144 0 114.168 0.084 ;
    END
  END snoop_data_o[293]
  PIN snoop_data_o[294]
    DIRECTION OUTPUT ;
    USE SIGNAL ;
    PORT
      LAYER M5 ;
        RECT  112.032 0 112.056 0.084 ;
    END
  END snoop_data_o[294]
  PIN snoop_data_o[295]
    DIRECTION OUTPUT ;
    USE SIGNAL ;
    PORT
      LAYER M5 ;
        RECT  111.36 0 111.384 0.084 ;
    END
  END snoop_data_o[295]
  PIN snoop_data_o[296]
    DIRECTION OUTPUT ;
    USE SIGNAL ;
    PORT
      LAYER M5 ;
        RECT  112.704 0 112.728 0.084 ;
    END
  END snoop_data_o[296]
  PIN snoop_data_o[297]
    DIRECTION OUTPUT ;
    USE SIGNAL ;
    PORT
      LAYER M5 ;
        RECT  112.8 0 112.824 0.084 ;
    END
  END snoop_data_o[297]
  PIN snoop_data_o[298]
    DIRECTION OUTPUT ;
    USE SIGNAL ;
    PORT
      LAYER M5 ;
        RECT  111.264 0 111.288 0.084 ;
    END
  END snoop_data_o[298]
  PIN snoop_data_o[299]
    DIRECTION OUTPUT ;
    USE SIGNAL ;
    PORT
      LAYER M5 ;
        RECT  113.376 0 113.4 0.084 ;
    END
  END snoop_data_o[299]
  PIN snoop_data_o[29]
    DIRECTION OUTPUT ;
    USE SIGNAL ;
    PORT
      LAYER M5 ;
        RECT  27.744 0 27.768 0.084 ;
    END
  END snoop_data_o[29]
  PIN snoop_data_o[2]
    DIRECTION OUTPUT ;
    USE SIGNAL ;
    PORT
      LAYER M5 ;
        RECT  27.648 0 27.672 0.084 ;
    END
  END snoop_data_o[2]
  PIN snoop_data_o[300]
    DIRECTION OUTPUT ;
    USE SIGNAL ;
    PORT
      LAYER M5 ;
        RECT  110.976 0 111 0.084 ;
    END
  END snoop_data_o[300]
  PIN snoop_data_o[301]
    DIRECTION OUTPUT ;
    USE SIGNAL ;
    PORT
      LAYER M5 ;
        RECT  112.992 0 113.016 0.084 ;
    END
  END snoop_data_o[301]
  PIN snoop_data_o[302]
    DIRECTION OUTPUT ;
    USE SIGNAL ;
    PORT
      LAYER M5 ;
        RECT  113.664 0 113.688 0.084 ;
    END
  END snoop_data_o[302]
  PIN snoop_data_o[303]
    DIRECTION OUTPUT ;
    USE SIGNAL ;
    PORT
      LAYER M5 ;
        RECT  112.608 0 112.632 0.084 ;
    END
  END snoop_data_o[303]
  PIN snoop_data_o[304]
    DIRECTION OUTPUT ;
    USE SIGNAL ;
    PORT
      LAYER M5 ;
        RECT  115.584 0 115.608 0.084 ;
    END
  END snoop_data_o[304]
  PIN snoop_data_o[305]
    DIRECTION OUTPUT ;
    USE SIGNAL ;
    PORT
      LAYER M5 ;
        RECT  114.432 0 114.456 0.084 ;
    END
  END snoop_data_o[305]
  PIN snoop_data_o[306]
    DIRECTION OUTPUT ;
    USE SIGNAL ;
    PORT
      LAYER M5 ;
        RECT  113.472 0 113.496 0.084 ;
    END
  END snoop_data_o[306]
  PIN snoop_data_o[307]
    DIRECTION OUTPUT ;
    USE SIGNAL ;
    PORT
      LAYER M5 ;
        RECT  113.856 0 113.88 0.084 ;
    END
  END snoop_data_o[307]
  PIN snoop_data_o[308]
    DIRECTION OUTPUT ;
    USE SIGNAL ;
    PORT
      LAYER M5 ;
        RECT  114.72 0 114.744 0.084 ;
    END
  END snoop_data_o[308]
  PIN snoop_data_o[309]
    DIRECTION OUTPUT ;
    USE SIGNAL ;
    PORT
      LAYER M5 ;
        RECT  112.32 0 112.344 0.084 ;
    END
  END snoop_data_o[309]
  PIN snoop_data_o[30]
    DIRECTION OUTPUT ;
    USE SIGNAL ;
    PORT
      LAYER M5 ;
        RECT  27.552 0 27.576 0.084 ;
    END
  END snoop_data_o[30]
  PIN snoop_data_o[310]
    DIRECTION OUTPUT ;
    USE SIGNAL ;
    PORT
      LAYER M5 ;
        RECT  111.648 0 111.672 0.084 ;
    END
  END snoop_data_o[310]
  PIN snoop_data_o[311]
    DIRECTION OUTPUT ;
    USE SIGNAL ;
    PORT
      LAYER M5 ;
        RECT  114.048 0 114.072 0.084 ;
    END
  END snoop_data_o[311]
  PIN snoop_data_o[312]
    DIRECTION OUTPUT ;
    USE SIGNAL ;
    PORT
      LAYER M5 ;
        RECT  110.784 0 110.808 0.084 ;
    END
  END snoop_data_o[312]
  PIN snoop_data_o[313]
    DIRECTION OUTPUT ;
    USE SIGNAL ;
    PORT
      LAYER M5 ;
        RECT  113.952 0 113.976 0.084 ;
    END
  END snoop_data_o[313]
  PIN snoop_data_o[314]
    DIRECTION OUTPUT ;
    USE SIGNAL ;
    PORT
      LAYER M5 ;
        RECT  114.624 0 114.648 0.084 ;
    END
  END snoop_data_o[314]
  PIN snoop_data_o[315]
    DIRECTION OUTPUT ;
    USE SIGNAL ;
    PORT
      LAYER M5 ;
        RECT  115.68 0 115.704 0.084 ;
    END
  END snoop_data_o[315]
  PIN snoop_data_o[316]
    DIRECTION OUTPUT ;
    USE SIGNAL ;
    PORT
      LAYER M5 ;
        RECT  115.776 0 115.8 0.084 ;
    END
  END snoop_data_o[316]
  PIN snoop_data_o[317]
    DIRECTION OUTPUT ;
    USE SIGNAL ;
    PORT
      LAYER M5 ;
        RECT  114.24 0 114.264 0.084 ;
    END
  END snoop_data_o[317]
  PIN snoop_data_o[318]
    DIRECTION OUTPUT ;
    USE SIGNAL ;
    PORT
      LAYER M5 ;
        RECT  115.872 0 115.896 0.084 ;
    END
  END snoop_data_o[318]
  PIN snoop_data_o[319]
    DIRECTION OUTPUT ;
    USE SIGNAL ;
    PORT
      LAYER M5 ;
        RECT  114.816 0 114.84 0.084 ;
    END
  END snoop_data_o[319]
  PIN snoop_data_o[31]
    DIRECTION OUTPUT ;
    USE SIGNAL ;
    PORT
      LAYER M5 ;
        RECT  27.456 0 27.48 0.084 ;
    END
  END snoop_data_o[31]
  PIN snoop_data_o[320]
    DIRECTION OUTPUT ;
    USE SIGNAL ;
    PORT
      LAYER M5 ;
        RECT  110.016 0 110.04 0.084 ;
    END
  END snoop_data_o[320]
  PIN snoop_data_o[321]
    DIRECTION OUTPUT ;
    USE SIGNAL ;
    PORT
      LAYER M5 ;
        RECT  114.912 0 114.936 0.084 ;
    END
  END snoop_data_o[321]
  PIN snoop_data_o[322]
    DIRECTION OUTPUT ;
    USE SIGNAL ;
    PORT
      LAYER M5 ;
        RECT  112.896 0 112.92 0.084 ;
    END
  END snoop_data_o[322]
  PIN snoop_data_o[323]
    DIRECTION OUTPUT ;
    USE SIGNAL ;
    PORT
      LAYER M5 ;
        RECT  93.984 0 94.008 0.084 ;
    END
  END snoop_data_o[323]
  PIN snoop_data_o[324]
    DIRECTION OUTPUT ;
    USE SIGNAL ;
    PORT
      LAYER M5 ;
        RECT  96.672 0 96.696 0.084 ;
    END
  END snoop_data_o[324]
  PIN snoop_data_o[325]
    DIRECTION OUTPUT ;
    USE SIGNAL ;
    PORT
      LAYER M5 ;
        RECT  96.576 0 96.6 0.084 ;
    END
  END snoop_data_o[325]
  PIN snoop_data_o[326]
    DIRECTION OUTPUT ;
    USE SIGNAL ;
    PORT
      LAYER M5 ;
        RECT  96.48 0 96.504 0.084 ;
    END
  END snoop_data_o[326]
  PIN snoop_data_o[327]
    DIRECTION OUTPUT ;
    USE SIGNAL ;
    PORT
      LAYER M5 ;
        RECT  96.384 0 96.408 0.084 ;
    END
  END snoop_data_o[327]
  PIN snoop_data_o[328]
    DIRECTION OUTPUT ;
    USE SIGNAL ;
    PORT
      LAYER M5 ;
        RECT  96.288 0 96.312 0.084 ;
    END
  END snoop_data_o[328]
  PIN snoop_data_o[329]
    DIRECTION OUTPUT ;
    USE SIGNAL ;
    PORT
      LAYER M5 ;
        RECT  96.192 0 96.216 0.084 ;
    END
  END snoop_data_o[329]
  PIN snoop_data_o[32]
    DIRECTION OUTPUT ;
    USE SIGNAL ;
    PORT
      LAYER M5 ;
        RECT  27.36 0 27.384 0.084 ;
    END
  END snoop_data_o[32]
  PIN snoop_data_o[330]
    DIRECTION OUTPUT ;
    USE SIGNAL ;
    PORT
      LAYER M5 ;
        RECT  96.096 0 96.12 0.084 ;
    END
  END snoop_data_o[330]
  PIN snoop_data_o[331]
    DIRECTION OUTPUT ;
    USE SIGNAL ;
    PORT
      LAYER M5 ;
        RECT  96 0 96.024 0.084 ;
    END
  END snoop_data_o[331]
  PIN snoop_data_o[332]
    DIRECTION OUTPUT ;
    USE SIGNAL ;
    PORT
      LAYER M5 ;
        RECT  119.136 0 119.16 0.084 ;
    END
  END snoop_data_o[332]
  PIN snoop_data_o[333]
    DIRECTION OUTPUT ;
    USE SIGNAL ;
    PORT
      LAYER M5 ;
        RECT  119.04 0 119.064 0.084 ;
    END
  END snoop_data_o[333]
  PIN snoop_data_o[334]
    DIRECTION OUTPUT ;
    USE SIGNAL ;
    PORT
      LAYER M5 ;
        RECT  118.56 0 118.584 0.084 ;
    END
  END snoop_data_o[334]
  PIN snoop_data_o[335]
    DIRECTION OUTPUT ;
    USE SIGNAL ;
    PORT
      LAYER M5 ;
        RECT  116.736 0 116.76 0.084 ;
    END
  END snoop_data_o[335]
  PIN snoop_data_o[336]
    DIRECTION OUTPUT ;
    USE SIGNAL ;
    PORT
      LAYER M5 ;
        RECT  117.024 0 117.048 0.084 ;
    END
  END snoop_data_o[336]
  PIN snoop_data_o[337]
    DIRECTION OUTPUT ;
    USE SIGNAL ;
    PORT
      LAYER M5 ;
        RECT  117.696 0 117.72 0.084 ;
    END
  END snoop_data_o[337]
  PIN snoop_data_o[338]
    DIRECTION OUTPUT ;
    USE SIGNAL ;
    PORT
      LAYER M5 ;
        RECT  118.656 0 118.68 0.084 ;
    END
  END snoop_data_o[338]
  PIN snoop_data_o[339]
    DIRECTION OUTPUT ;
    USE SIGNAL ;
    PORT
      LAYER M5 ;
        RECT  116.352 0 116.376 0.084 ;
    END
  END snoop_data_o[339]
  PIN snoop_data_o[33]
    DIRECTION OUTPUT ;
    USE SIGNAL ;
    PORT
      LAYER M5 ;
        RECT  27.264 0 27.288 0.084 ;
    END
  END snoop_data_o[33]
  PIN snoop_data_o[340]
    DIRECTION OUTPUT ;
    USE SIGNAL ;
    PORT
      LAYER M5 ;
        RECT  118.752 0 118.776 0.084 ;
    END
  END snoop_data_o[340]
  PIN snoop_data_o[341]
    DIRECTION OUTPUT ;
    USE SIGNAL ;
    PORT
      LAYER M5 ;
        RECT  116.64 0 116.664 0.084 ;
    END
  END snoop_data_o[341]
  PIN snoop_data_o[342]
    DIRECTION OUTPUT ;
    USE SIGNAL ;
    PORT
      LAYER M5 ;
        RECT  118.944 0 118.968 0.084 ;
    END
  END snoop_data_o[342]
  PIN snoop_data_o[343]
    DIRECTION OUTPUT ;
    USE SIGNAL ;
    PORT
      LAYER M5 ;
        RECT  117.888 0 117.912 0.084 ;
    END
  END snoop_data_o[343]
  PIN snoop_data_o[344]
    DIRECTION OUTPUT ;
    USE SIGNAL ;
    PORT
      LAYER M5 ;
        RECT  116.064 0 116.088 0.084 ;
    END
  END snoop_data_o[344]
  PIN snoop_data_o[345]
    DIRECTION OUTPUT ;
    USE SIGNAL ;
    PORT
      LAYER M5 ;
        RECT  116.544 0 116.568 0.084 ;
    END
  END snoop_data_o[345]
  PIN snoop_data_o[346]
    DIRECTION OUTPUT ;
    USE SIGNAL ;
    PORT
      LAYER M5 ;
        RECT  117.984 0 118.008 0.084 ;
    END
  END snoop_data_o[346]
  PIN snoop_data_o[347]
    DIRECTION OUTPUT ;
    USE SIGNAL ;
    PORT
      LAYER M5 ;
        RECT  116.928 0 116.952 0.084 ;
    END
  END snoop_data_o[347]
  PIN snoop_data_o[348]
    DIRECTION OUTPUT ;
    USE SIGNAL ;
    PORT
      LAYER M5 ;
        RECT  117.408 0 117.432 0.084 ;
    END
  END snoop_data_o[348]
  PIN snoop_data_o[349]
    DIRECTION OUTPUT ;
    USE SIGNAL ;
    PORT
      LAYER M5 ;
        RECT  118.08 0 118.104 0.084 ;
    END
  END snoop_data_o[349]
  PIN snoop_data_o[34]
    DIRECTION OUTPUT ;
    USE SIGNAL ;
    PORT
      LAYER M5 ;
        RECT  27.168 0 27.192 0.084 ;
    END
  END snoop_data_o[34]
  PIN snoop_data_o[350]
    DIRECTION OUTPUT ;
    USE SIGNAL ;
    PORT
      LAYER M5 ;
        RECT  95.904 0 95.928 0.084 ;
    END
  END snoop_data_o[350]
  PIN snoop_data_o[351]
    DIRECTION OUTPUT ;
    USE SIGNAL ;
    PORT
      LAYER M5 ;
        RECT  116.448 0 116.472 0.084 ;
    END
  END snoop_data_o[351]
  PIN snoop_data_o[352]
    DIRECTION OUTPUT ;
    USE SIGNAL ;
    PORT
      LAYER M5 ;
        RECT  116.832 0 116.856 0.084 ;
    END
  END snoop_data_o[352]
  PIN snoop_data_o[353]
    DIRECTION OUTPUT ;
    USE SIGNAL ;
    PORT
      LAYER M5 ;
        RECT  118.176 0 118.2 0.084 ;
    END
  END snoop_data_o[353]
  PIN snoop_data_o[354]
    DIRECTION OUTPUT ;
    USE SIGNAL ;
    PORT
      LAYER M5 ;
        RECT  117.216 0 117.24 0.084 ;
    END
  END snoop_data_o[354]
  PIN snoop_data_o[355]
    DIRECTION OUTPUT ;
    USE SIGNAL ;
    PORT
      LAYER M5 ;
        RECT  95.808 0 95.832 0.084 ;
    END
  END snoop_data_o[355]
  PIN snoop_data_o[356]
    DIRECTION OUTPUT ;
    USE SIGNAL ;
    PORT
      LAYER M5 ;
        RECT  95.712 0 95.736 0.084 ;
    END
  END snoop_data_o[356]
  PIN snoop_data_o[357]
    DIRECTION OUTPUT ;
    USE SIGNAL ;
    PORT
      LAYER M5 ;
        RECT  95.616 0 95.64 0.084 ;
    END
  END snoop_data_o[357]
  PIN snoop_data_o[358]
    DIRECTION OUTPUT ;
    USE SIGNAL ;
    PORT
      LAYER M5 ;
        RECT  117.6 0 117.624 0.084 ;
    END
  END snoop_data_o[358]
  PIN snoop_data_o[359]
    DIRECTION OUTPUT ;
    USE SIGNAL ;
    PORT
      LAYER M5 ;
        RECT  118.272 0 118.296 0.084 ;
    END
  END snoop_data_o[359]
  PIN snoop_data_o[35]
    DIRECTION OUTPUT ;
    USE SIGNAL ;
    PORT
      LAYER M5 ;
        RECT  27.072 0 27.096 0.084 ;
    END
  END snoop_data_o[35]
  PIN snoop_data_o[360]
    DIRECTION OUTPUT ;
    USE SIGNAL ;
    PORT
      LAYER M5 ;
        RECT  95.52 0 95.544 0.084 ;
    END
  END snoop_data_o[360]
  PIN snoop_data_o[361]
    DIRECTION OUTPUT ;
    USE SIGNAL ;
    PORT
      LAYER M5 ;
        RECT  95.424 0 95.448 0.084 ;
    END
  END snoop_data_o[361]
  PIN snoop_data_o[362]
    DIRECTION OUTPUT ;
    USE SIGNAL ;
    PORT
      LAYER M5 ;
        RECT  116.16 0 116.184 0.084 ;
    END
  END snoop_data_o[362]
  PIN snoop_data_o[363]
    DIRECTION OUTPUT ;
    USE SIGNAL ;
    PORT
      LAYER M5 ;
        RECT  117.12 0 117.144 0.084 ;
    END
  END snoop_data_o[363]
  PIN snoop_data_o[364]
    DIRECTION OUTPUT ;
    USE SIGNAL ;
    PORT
      LAYER M5 ;
        RECT  117.792 0 117.816 0.084 ;
    END
  END snoop_data_o[364]
  PIN snoop_data_o[365]
    DIRECTION OUTPUT ;
    USE SIGNAL ;
    PORT
      LAYER M5 ;
        RECT  118.368 0 118.392 0.084 ;
    END
  END snoop_data_o[365]
  PIN snoop_data_o[366]
    DIRECTION OUTPUT ;
    USE SIGNAL ;
    PORT
      LAYER M5 ;
        RECT  118.848 0 118.872 0.084 ;
    END
  END snoop_data_o[366]
  PIN snoop_data_o[367]
    DIRECTION OUTPUT ;
    USE SIGNAL ;
    PORT
      LAYER M5 ;
        RECT  117.312 0 117.336 0.084 ;
    END
  END snoop_data_o[367]
  PIN snoop_data_o[368]
    DIRECTION OUTPUT ;
    USE SIGNAL ;
    PORT
      LAYER M5 ;
        RECT  115.968 0 115.992 0.084 ;
    END
  END snoop_data_o[368]
  PIN snoop_data_o[369]
    DIRECTION OUTPUT ;
    USE SIGNAL ;
    PORT
      LAYER M5 ;
        RECT  118.464 0 118.488 0.084 ;
    END
  END snoop_data_o[369]
  PIN snoop_data_o[36]
    DIRECTION OUTPUT ;
    USE SIGNAL ;
    PORT
      LAYER M5 ;
        RECT  26.976 0 27 0.084 ;
    END
  END snoop_data_o[36]
  PIN snoop_data_o[370]
    DIRECTION OUTPUT ;
    USE SIGNAL ;
    PORT
      LAYER M5 ;
        RECT  116.256 0 116.28 0.084 ;
    END
  END snoop_data_o[370]
  PIN snoop_data_o[371]
    DIRECTION OUTPUT ;
    USE SIGNAL ;
    PORT
      LAYER M5 ;
        RECT  117.504 0 117.528 0.084 ;
    END
  END snoop_data_o[371]
  PIN snoop_data_o[372]
    DIRECTION OUTPUT ;
    USE SIGNAL ;
    PORT
      LAYER M5 ;
        RECT  95.328 0 95.352 0.084 ;
    END
  END snoop_data_o[372]
  PIN snoop_data_o[373]
    DIRECTION OUTPUT ;
    USE SIGNAL ;
    PORT
      LAYER M5 ;
        RECT  95.232 0 95.256 0.084 ;
    END
  END snoop_data_o[373]
  PIN snoop_data_o[374]
    DIRECTION OUTPUT ;
    USE SIGNAL ;
    PORT
      LAYER M5 ;
        RECT  95.136 0 95.16 0.084 ;
    END
  END snoop_data_o[374]
  PIN snoop_data_o[375]
    DIRECTION OUTPUT ;
    USE SIGNAL ;
    PORT
      LAYER M5 ;
        RECT  95.04 0 95.064 0.084 ;
    END
  END snoop_data_o[375]
  PIN snoop_data_o[376]
    DIRECTION OUTPUT ;
    USE SIGNAL ;
    PORT
      LAYER M5 ;
        RECT  94.944 0 94.968 0.084 ;
    END
  END snoop_data_o[376]
  PIN snoop_data_o[377]
    DIRECTION OUTPUT ;
    USE SIGNAL ;
    PORT
      LAYER M5 ;
        RECT  94.848 0 94.872 0.084 ;
    END
  END snoop_data_o[377]
  PIN snoop_data_o[378]
    DIRECTION OUTPUT ;
    USE SIGNAL ;
    PORT
      LAYER M5 ;
        RECT  94.752 0 94.776 0.084 ;
    END
  END snoop_data_o[378]
  PIN snoop_data_o[379]
    DIRECTION OUTPUT ;
    USE SIGNAL ;
    PORT
      LAYER M5 ;
        RECT  94.656 0 94.68 0.084 ;
    END
  END snoop_data_o[379]
  PIN snoop_data_o[37]
    DIRECTION OUTPUT ;
    USE SIGNAL ;
    PORT
      LAYER M5 ;
        RECT  26.88 0 26.904 0.084 ;
    END
  END snoop_data_o[37]
  PIN snoop_data_o[380]
    DIRECTION OUTPUT ;
    USE SIGNAL ;
    PORT
      LAYER M5 ;
        RECT  94.56 0 94.584 0.084 ;
    END
  END snoop_data_o[380]
  PIN snoop_data_o[381]
    DIRECTION OUTPUT ;
    USE SIGNAL ;
    PORT
      LAYER M5 ;
        RECT  94.464 0 94.488 0.084 ;
    END
  END snoop_data_o[381]
  PIN snoop_data_o[382]
    DIRECTION OUTPUT ;
    USE SIGNAL ;
    PORT
      LAYER M5 ;
        RECT  94.368 0 94.392 0.084 ;
    END
  END snoop_data_o[382]
  PIN snoop_data_o[383]
    DIRECTION OUTPUT ;
    USE SIGNAL ;
    PORT
      LAYER M5 ;
        RECT  94.272 0 94.296 0.084 ;
    END
  END snoop_data_o[383]
  PIN snoop_data_o[384]
    DIRECTION OUTPUT ;
    USE SIGNAL ;
    PORT
      LAYER M5 ;
        RECT  94.176 0 94.2 0.084 ;
    END
  END snoop_data_o[384]
  PIN snoop_data_o[385]
    DIRECTION OUTPUT ;
    USE SIGNAL ;
    PORT
      LAYER M5 ;
        RECT  94.08 0 94.104 0.084 ;
    END
  END snoop_data_o[385]
  PIN snoop_data_o[386]
    DIRECTION OUTPUT ;
    USE SIGNAL ;
    PORT
      LAYER M4 ;
        RECT  144.916 20.928 145 20.952 ;
    END
  END snoop_data_o[386]
  PIN snoop_data_o[387]
    DIRECTION OUTPUT ;
    USE SIGNAL ;
    PORT
      LAYER M4 ;
        RECT  144.916 21.12 145 21.144 ;
    END
  END snoop_data_o[387]
  PIN snoop_data_o[388]
    DIRECTION OUTPUT ;
    USE SIGNAL ;
    PORT
      LAYER M4 ;
        RECT  144.916 21.216 145 21.24 ;
    END
  END snoop_data_o[388]
  PIN snoop_data_o[389]
    DIRECTION OUTPUT ;
    USE SIGNAL ;
    PORT
      LAYER M4 ;
        RECT  144.916 21.408 145 21.432 ;
    END
  END snoop_data_o[389]
  PIN snoop_data_o[38]
    DIRECTION OUTPUT ;
    USE SIGNAL ;
    PORT
      LAYER M5 ;
        RECT  26.784 0 26.808 0.084 ;
    END
  END snoop_data_o[38]
  PIN snoop_data_o[390]
    DIRECTION OUTPUT ;
    USE SIGNAL ;
    PORT
      LAYER M4 ;
        RECT  144.916 21.504 145 21.528 ;
    END
  END snoop_data_o[390]
  PIN snoop_data_o[391]
    DIRECTION OUTPUT ;
    USE SIGNAL ;
    PORT
      LAYER M4 ;
        RECT  144.916 21.696 145 21.72 ;
    END
  END snoop_data_o[391]
  PIN snoop_data_o[392]
    DIRECTION OUTPUT ;
    USE SIGNAL ;
    PORT
      LAYER M4 ;
        RECT  144.916 21.792 145 21.816 ;
    END
  END snoop_data_o[392]
  PIN snoop_data_o[393]
    DIRECTION OUTPUT ;
    USE SIGNAL ;
    PORT
      LAYER M4 ;
        RECT  144.916 21.984 145 22.008 ;
    END
  END snoop_data_o[393]
  PIN snoop_data_o[394]
    DIRECTION OUTPUT ;
    USE SIGNAL ;
    PORT
      LAYER M4 ;
        RECT  144.916 22.08 145 22.104 ;
    END
  END snoop_data_o[394]
  PIN snoop_data_o[395]
    DIRECTION OUTPUT ;
    USE SIGNAL ;
    PORT
      LAYER M4 ;
        RECT  144.916 22.272 145 22.296 ;
    END
  END snoop_data_o[395]
  PIN snoop_data_o[396]
    DIRECTION OUTPUT ;
    USE SIGNAL ;
    PORT
      LAYER M4 ;
        RECT  144.916 22.368 145 22.392 ;
    END
  END snoop_data_o[396]
  PIN snoop_data_o[397]
    DIRECTION OUTPUT ;
    USE SIGNAL ;
    PORT
      LAYER M4 ;
        RECT  144.916 22.56 145 22.584 ;
    END
  END snoop_data_o[397]
  PIN snoop_data_o[398]
    DIRECTION OUTPUT ;
    USE SIGNAL ;
    PORT
      LAYER M4 ;
        RECT  144.916 22.656 145 22.68 ;
    END
  END snoop_data_o[398]
  PIN snoop_data_o[399]
    DIRECTION OUTPUT ;
    USE SIGNAL ;
    PORT
      LAYER M4 ;
        RECT  144.916 22.848 145 22.872 ;
    END
  END snoop_data_o[399]
  PIN snoop_data_o[39]
    DIRECTION OUTPUT ;
    USE SIGNAL ;
    PORT
      LAYER M5 ;
        RECT  26.688 0 26.712 0.084 ;
    END
  END snoop_data_o[39]
  PIN snoop_data_o[3]
    DIRECTION OUTPUT ;
    USE SIGNAL ;
    PORT
      LAYER M5 ;
        RECT  26.592 0 26.616 0.084 ;
    END
  END snoop_data_o[3]
  PIN snoop_data_o[400]
    DIRECTION OUTPUT ;
    USE SIGNAL ;
    PORT
      LAYER M4 ;
        RECT  144.916 22.944 145 22.968 ;
    END
  END snoop_data_o[400]
  PIN snoop_data_o[401]
    DIRECTION OUTPUT ;
    USE SIGNAL ;
    PORT
      LAYER M4 ;
        RECT  144.916 23.136 145 23.16 ;
    END
  END snoop_data_o[401]
  PIN snoop_data_o[402]
    DIRECTION OUTPUT ;
    USE SIGNAL ;
    PORT
      LAYER M4 ;
        RECT  144.916 23.232 145 23.256 ;
    END
  END snoop_data_o[402]
  PIN snoop_data_o[403]
    DIRECTION OUTPUT ;
    USE SIGNAL ;
    PORT
      LAYER M4 ;
        RECT  144.916 23.424 145 23.448 ;
    END
  END snoop_data_o[403]
  PIN snoop_data_o[404]
    DIRECTION OUTPUT ;
    USE SIGNAL ;
    PORT
      LAYER M4 ;
        RECT  144.916 23.52 145 23.544 ;
    END
  END snoop_data_o[404]
  PIN snoop_data_o[405]
    DIRECTION OUTPUT ;
    USE SIGNAL ;
    PORT
      LAYER M4 ;
        RECT  144.916 23.712 145 23.736 ;
    END
  END snoop_data_o[405]
  PIN snoop_data_o[406]
    DIRECTION OUTPUT ;
    USE SIGNAL ;
    PORT
      LAYER M4 ;
        RECT  144.916 23.808 145 23.832 ;
    END
  END snoop_data_o[406]
  PIN snoop_data_o[407]
    DIRECTION OUTPUT ;
    USE SIGNAL ;
    PORT
      LAYER M4 ;
        RECT  144.916 24 145 24.024 ;
    END
  END snoop_data_o[407]
  PIN snoop_data_o[408]
    DIRECTION OUTPUT ;
    USE SIGNAL ;
    PORT
      LAYER M4 ;
        RECT  144.916 24.096 145 24.12 ;
    END
  END snoop_data_o[408]
  PIN snoop_data_o[409]
    DIRECTION OUTPUT ;
    USE SIGNAL ;
    PORT
      LAYER M4 ;
        RECT  144.916 24.288 145 24.312 ;
    END
  END snoop_data_o[409]
  PIN snoop_data_o[40]
    DIRECTION OUTPUT ;
    USE SIGNAL ;
    PORT
      LAYER M5 ;
        RECT  26.496 0 26.52 0.084 ;
    END
  END snoop_data_o[40]
  PIN snoop_data_o[410]
    DIRECTION OUTPUT ;
    USE SIGNAL ;
    PORT
      LAYER M4 ;
        RECT  144.916 24.384 145 24.408 ;
    END
  END snoop_data_o[410]
  PIN snoop_data_o[411]
    DIRECTION OUTPUT ;
    USE SIGNAL ;
    PORT
      LAYER M4 ;
        RECT  144.916 24.576 145 24.6 ;
    END
  END snoop_data_o[411]
  PIN snoop_data_o[412]
    DIRECTION OUTPUT ;
    USE SIGNAL ;
    PORT
      LAYER M4 ;
        RECT  144.916 24.672 145 24.696 ;
    END
  END snoop_data_o[412]
  PIN snoop_data_o[413]
    DIRECTION OUTPUT ;
    USE SIGNAL ;
    PORT
      LAYER M4 ;
        RECT  144.916 24.864 145 24.888 ;
    END
  END snoop_data_o[413]
  PIN snoop_data_o[414]
    DIRECTION OUTPUT ;
    USE SIGNAL ;
    PORT
      LAYER M4 ;
        RECT  144.916 24.96 145 24.984 ;
    END
  END snoop_data_o[414]
  PIN snoop_data_o[415]
    DIRECTION OUTPUT ;
    USE SIGNAL ;
    PORT
      LAYER M4 ;
        RECT  144.916 25.152 145 25.176 ;
    END
  END snoop_data_o[415]
  PIN snoop_data_o[416]
    DIRECTION OUTPUT ;
    USE SIGNAL ;
    PORT
      LAYER M4 ;
        RECT  144.916 25.248 145 25.272 ;
    END
  END snoop_data_o[416]
  PIN snoop_data_o[417]
    DIRECTION OUTPUT ;
    USE SIGNAL ;
    PORT
      LAYER M4 ;
        RECT  144.916 25.44 145 25.464 ;
    END
  END snoop_data_o[417]
  PIN snoop_data_o[418]
    DIRECTION OUTPUT ;
    USE SIGNAL ;
    PORT
      LAYER M4 ;
        RECT  144.916 25.536 145 25.56 ;
    END
  END snoop_data_o[418]
  PIN snoop_data_o[419]
    DIRECTION OUTPUT ;
    USE SIGNAL ;
    PORT
      LAYER M4 ;
        RECT  144.916 25.728 145 25.752 ;
    END
  END snoop_data_o[419]
  PIN snoop_data_o[41]
    DIRECTION OUTPUT ;
    USE SIGNAL ;
    PORT
      LAYER M5 ;
        RECT  26.4 0 26.424 0.084 ;
    END
  END snoop_data_o[41]
  PIN snoop_data_o[420]
    DIRECTION OUTPUT ;
    USE SIGNAL ;
    PORT
      LAYER M4 ;
        RECT  144.916 25.824 145 25.848 ;
    END
  END snoop_data_o[420]
  PIN snoop_data_o[421]
    DIRECTION OUTPUT ;
    USE SIGNAL ;
    PORT
      LAYER M4 ;
        RECT  144.916 26.016 145 26.04 ;
    END
  END snoop_data_o[421]
  PIN snoop_data_o[422]
    DIRECTION OUTPUT ;
    USE SIGNAL ;
    PORT
      LAYER M4 ;
        RECT  144.916 26.112 145 26.136 ;
    END
  END snoop_data_o[422]
  PIN snoop_data_o[423]
    DIRECTION OUTPUT ;
    USE SIGNAL ;
    PORT
      LAYER M4 ;
        RECT  144.916 26.304 145 26.328 ;
    END
  END snoop_data_o[423]
  PIN snoop_data_o[424]
    DIRECTION OUTPUT ;
    USE SIGNAL ;
    PORT
      LAYER M4 ;
        RECT  144.916 26.4 145 26.424 ;
    END
  END snoop_data_o[424]
  PIN snoop_data_o[425]
    DIRECTION OUTPUT ;
    USE SIGNAL ;
    PORT
      LAYER M4 ;
        RECT  144.916 26.592 145 26.616 ;
    END
  END snoop_data_o[425]
  PIN snoop_data_o[426]
    DIRECTION OUTPUT ;
    USE SIGNAL ;
    PORT
      LAYER M4 ;
        RECT  144.916 26.688 145 26.712 ;
    END
  END snoop_data_o[426]
  PIN snoop_data_o[427]
    DIRECTION OUTPUT ;
    USE SIGNAL ;
    PORT
      LAYER M4 ;
        RECT  144.916 26.88 145 26.904 ;
    END
  END snoop_data_o[427]
  PIN snoop_data_o[428]
    DIRECTION OUTPUT ;
    USE SIGNAL ;
    PORT
      LAYER M4 ;
        RECT  144.916 26.976 145 27 ;
    END
  END snoop_data_o[428]
  PIN snoop_data_o[429]
    DIRECTION OUTPUT ;
    USE SIGNAL ;
    PORT
      LAYER M4 ;
        RECT  144.916 27.168 145 27.192 ;
    END
  END snoop_data_o[429]
  PIN snoop_data_o[42]
    DIRECTION OUTPUT ;
    USE SIGNAL ;
    PORT
      LAYER M5 ;
        RECT  26.304 0 26.328 0.084 ;
    END
  END snoop_data_o[42]
  PIN snoop_data_o[430]
    DIRECTION OUTPUT ;
    USE SIGNAL ;
    PORT
      LAYER M4 ;
        RECT  144.916 27.264 145 27.288 ;
    END
  END snoop_data_o[430]
  PIN snoop_data_o[431]
    DIRECTION OUTPUT ;
    USE SIGNAL ;
    PORT
      LAYER M4 ;
        RECT  144.916 27.456 145 27.48 ;
    END
  END snoop_data_o[431]
  PIN snoop_data_o[432]
    DIRECTION OUTPUT ;
    USE SIGNAL ;
    PORT
      LAYER M4 ;
        RECT  144.916 27.552 145 27.576 ;
    END
  END snoop_data_o[432]
  PIN snoop_data_o[433]
    DIRECTION OUTPUT ;
    USE SIGNAL ;
    PORT
      LAYER M4 ;
        RECT  144.916 27.744 145 27.768 ;
    END
  END snoop_data_o[433]
  PIN snoop_data_o[434]
    DIRECTION OUTPUT ;
    USE SIGNAL ;
    PORT
      LAYER M4 ;
        RECT  144.916 27.84 145 27.864 ;
    END
  END snoop_data_o[434]
  PIN snoop_data_o[435]
    DIRECTION OUTPUT ;
    USE SIGNAL ;
    PORT
      LAYER M4 ;
        RECT  144.916 28.032 145 28.056 ;
    END
  END snoop_data_o[435]
  PIN snoop_data_o[436]
    DIRECTION OUTPUT ;
    USE SIGNAL ;
    PORT
      LAYER M4 ;
        RECT  144.916 28.128 145 28.152 ;
    END
  END snoop_data_o[436]
  PIN snoop_data_o[437]
    DIRECTION OUTPUT ;
    USE SIGNAL ;
    PORT
      LAYER M4 ;
        RECT  144.916 28.32 145 28.344 ;
    END
  END snoop_data_o[437]
  PIN snoop_data_o[438]
    DIRECTION OUTPUT ;
    USE SIGNAL ;
    PORT
      LAYER M4 ;
        RECT  144.916 28.416 145 28.44 ;
    END
  END snoop_data_o[438]
  PIN snoop_data_o[439]
    DIRECTION OUTPUT ;
    USE SIGNAL ;
    PORT
      LAYER M4 ;
        RECT  144.916 28.608 145 28.632 ;
    END
  END snoop_data_o[439]
  PIN snoop_data_o[43]
    DIRECTION OUTPUT ;
    USE SIGNAL ;
    PORT
      LAYER M5 ;
        RECT  26.208 0 26.232 0.084 ;
    END
  END snoop_data_o[43]
  PIN snoop_data_o[440]
    DIRECTION OUTPUT ;
    USE SIGNAL ;
    PORT
      LAYER M4 ;
        RECT  144.916 28.704 145 28.728 ;
    END
  END snoop_data_o[440]
  PIN snoop_data_o[441]
    DIRECTION OUTPUT ;
    USE SIGNAL ;
    PORT
      LAYER M4 ;
        RECT  144.916 28.896 145 28.92 ;
    END
  END snoop_data_o[441]
  PIN snoop_data_o[442]
    DIRECTION OUTPUT ;
    USE SIGNAL ;
    PORT
      LAYER M4 ;
        RECT  144.916 28.992 145 29.016 ;
    END
  END snoop_data_o[442]
  PIN snoop_data_o[443]
    DIRECTION OUTPUT ;
    USE SIGNAL ;
    PORT
      LAYER M4 ;
        RECT  144.916 29.184 145 29.208 ;
    END
  END snoop_data_o[443]
  PIN snoop_data_o[444]
    DIRECTION OUTPUT ;
    USE SIGNAL ;
    PORT
      LAYER M4 ;
        RECT  144.916 29.28 145 29.304 ;
    END
  END snoop_data_o[444]
  PIN snoop_data_o[445]
    DIRECTION OUTPUT ;
    USE SIGNAL ;
    PORT
      LAYER M4 ;
        RECT  144.916 29.472 145 29.496 ;
    END
  END snoop_data_o[445]
  PIN snoop_data_o[446]
    DIRECTION OUTPUT ;
    USE SIGNAL ;
    PORT
      LAYER M4 ;
        RECT  144.916 29.568 145 29.592 ;
    END
  END snoop_data_o[446]
  PIN snoop_data_o[447]
    DIRECTION OUTPUT ;
    USE SIGNAL ;
    PORT
      LAYER M4 ;
        RECT  144.916 29.76 145 29.784 ;
    END
  END snoop_data_o[447]
  PIN snoop_data_o[448]
    DIRECTION OUTPUT ;
    USE SIGNAL ;
    PORT
      LAYER M4 ;
        RECT  144.916 29.856 145 29.88 ;
    END
  END snoop_data_o[448]
  PIN snoop_data_o[449]
    DIRECTION OUTPUT ;
    USE SIGNAL ;
    PORT
      LAYER M4 ;
        RECT  144.916 30.048 145 30.072 ;
    END
  END snoop_data_o[449]
  PIN snoop_data_o[44]
    DIRECTION OUTPUT ;
    USE SIGNAL ;
    PORT
      LAYER M5 ;
        RECT  26.112 0 26.136 0.084 ;
    END
  END snoop_data_o[44]
  PIN snoop_data_o[450]
    DIRECTION OUTPUT ;
    USE SIGNAL ;
    PORT
      LAYER M4 ;
        RECT  144.916 30.144 145 30.168 ;
    END
  END snoop_data_o[450]
  PIN snoop_data_o[451]
    DIRECTION OUTPUT ;
    USE SIGNAL ;
    PORT
      LAYER M4 ;
        RECT  144.916 30.336 145 30.36 ;
    END
  END snoop_data_o[451]
  PIN snoop_data_o[452]
    DIRECTION OUTPUT ;
    USE SIGNAL ;
    PORT
      LAYER M4 ;
        RECT  144.916 30.432 145 30.456 ;
    END
  END snoop_data_o[452]
  PIN snoop_data_o[453]
    DIRECTION OUTPUT ;
    USE SIGNAL ;
    PORT
      LAYER M4 ;
        RECT  144.916 30.624 145 30.648 ;
    END
  END snoop_data_o[453]
  PIN snoop_data_o[454]
    DIRECTION OUTPUT ;
    USE SIGNAL ;
    PORT
      LAYER M4 ;
        RECT  144.916 30.72 145 30.744 ;
    END
  END snoop_data_o[454]
  PIN snoop_data_o[455]
    DIRECTION OUTPUT ;
    USE SIGNAL ;
    PORT
      LAYER M4 ;
        RECT  144.916 30.912 145 30.936 ;
    END
  END snoop_data_o[455]
  PIN snoop_data_o[456]
    DIRECTION OUTPUT ;
    USE SIGNAL ;
    PORT
      LAYER M4 ;
        RECT  144.916 31.008 145 31.032 ;
    END
  END snoop_data_o[456]
  PIN snoop_data_o[457]
    DIRECTION OUTPUT ;
    USE SIGNAL ;
    PORT
      LAYER M4 ;
        RECT  144.916 31.2 145 31.224 ;
    END
  END snoop_data_o[457]
  PIN snoop_data_o[458]
    DIRECTION OUTPUT ;
    USE SIGNAL ;
    PORT
      LAYER M4 ;
        RECT  144.916 31.296 145 31.32 ;
    END
  END snoop_data_o[458]
  PIN snoop_data_o[459]
    DIRECTION OUTPUT ;
    USE SIGNAL ;
    PORT
      LAYER M4 ;
        RECT  144.916 31.488 145 31.512 ;
    END
  END snoop_data_o[459]
  PIN snoop_data_o[45]
    DIRECTION OUTPUT ;
    USE SIGNAL ;
    PORT
      LAYER M5 ;
        RECT  26.016 0 26.04 0.084 ;
    END
  END snoop_data_o[45]
  PIN snoop_data_o[460]
    DIRECTION OUTPUT ;
    USE SIGNAL ;
    PORT
      LAYER M4 ;
        RECT  144.916 31.584 145 31.608 ;
    END
  END snoop_data_o[460]
  PIN snoop_data_o[461]
    DIRECTION OUTPUT ;
    USE SIGNAL ;
    PORT
      LAYER M4 ;
        RECT  144.916 31.776 145 31.8 ;
    END
  END snoop_data_o[461]
  PIN snoop_data_o[462]
    DIRECTION OUTPUT ;
    USE SIGNAL ;
    PORT
      LAYER M4 ;
        RECT  144.916 31.872 145 31.896 ;
    END
  END snoop_data_o[462]
  PIN snoop_data_o[463]
    DIRECTION OUTPUT ;
    USE SIGNAL ;
    PORT
      LAYER M4 ;
        RECT  144.916 32.064 145 32.088 ;
    END
  END snoop_data_o[463]
  PIN snoop_data_o[464]
    DIRECTION OUTPUT ;
    USE SIGNAL ;
    PORT
      LAYER M4 ;
        RECT  144.916 32.16 145 32.184 ;
    END
  END snoop_data_o[464]
  PIN snoop_data_o[465]
    DIRECTION OUTPUT ;
    USE SIGNAL ;
    PORT
      LAYER M4 ;
        RECT  144.916 32.352 145 32.376 ;
    END
  END snoop_data_o[465]
  PIN snoop_data_o[466]
    DIRECTION OUTPUT ;
    USE SIGNAL ;
    PORT
      LAYER M4 ;
        RECT  144.916 32.448 145 32.472 ;
    END
  END snoop_data_o[466]
  PIN snoop_data_o[467]
    DIRECTION OUTPUT ;
    USE SIGNAL ;
    PORT
      LAYER M4 ;
        RECT  144.916 32.64 145 32.664 ;
    END
  END snoop_data_o[467]
  PIN snoop_data_o[468]
    DIRECTION OUTPUT ;
    USE SIGNAL ;
    PORT
      LAYER M4 ;
        RECT  144.916 32.736 145 32.76 ;
    END
  END snoop_data_o[468]
  PIN snoop_data_o[469]
    DIRECTION OUTPUT ;
    USE SIGNAL ;
    PORT
      LAYER M4 ;
        RECT  144.916 32.928 145 32.952 ;
    END
  END snoop_data_o[469]
  PIN snoop_data_o[46]
    DIRECTION OUTPUT ;
    USE SIGNAL ;
    PORT
      LAYER M5 ;
        RECT  25.92 0 25.944 0.084 ;
    END
  END snoop_data_o[46]
  PIN snoop_data_o[470]
    DIRECTION OUTPUT ;
    USE SIGNAL ;
    PORT
      LAYER M4 ;
        RECT  144.916 33.024 145 33.048 ;
    END
  END snoop_data_o[470]
  PIN snoop_data_o[471]
    DIRECTION OUTPUT ;
    USE SIGNAL ;
    PORT
      LAYER M4 ;
        RECT  144.916 33.216 145 33.24 ;
    END
  END snoop_data_o[471]
  PIN snoop_data_o[472]
    DIRECTION OUTPUT ;
    USE SIGNAL ;
    PORT
      LAYER M4 ;
        RECT  144.916 33.312 145 33.336 ;
    END
  END snoop_data_o[472]
  PIN snoop_data_o[473]
    DIRECTION OUTPUT ;
    USE SIGNAL ;
    PORT
      LAYER M4 ;
        RECT  144.916 33.504 145 33.528 ;
    END
  END snoop_data_o[473]
  PIN snoop_data_o[474]
    DIRECTION OUTPUT ;
    USE SIGNAL ;
    PORT
      LAYER M4 ;
        RECT  144.916 33.6 145 33.624 ;
    END
  END snoop_data_o[474]
  PIN snoop_data_o[475]
    DIRECTION OUTPUT ;
    USE SIGNAL ;
    PORT
      LAYER M4 ;
        RECT  144.916 33.792 145 33.816 ;
    END
  END snoop_data_o[475]
  PIN snoop_data_o[476]
    DIRECTION OUTPUT ;
    USE SIGNAL ;
    PORT
      LAYER M4 ;
        RECT  144.916 33.888 145 33.912 ;
    END
  END snoop_data_o[476]
  PIN snoop_data_o[477]
    DIRECTION OUTPUT ;
    USE SIGNAL ;
    PORT
      LAYER M4 ;
        RECT  144.916 34.08 145 34.104 ;
    END
  END snoop_data_o[477]
  PIN snoop_data_o[478]
    DIRECTION OUTPUT ;
    USE SIGNAL ;
    PORT
      LAYER M4 ;
        RECT  144.916 34.176 145 34.2 ;
    END
  END snoop_data_o[478]
  PIN snoop_data_o[479]
    DIRECTION OUTPUT ;
    USE SIGNAL ;
    PORT
      LAYER M4 ;
        RECT  144.916 34.368 145 34.392 ;
    END
  END snoop_data_o[479]
  PIN snoop_data_o[47]
    DIRECTION OUTPUT ;
    USE SIGNAL ;
    PORT
      LAYER M5 ;
        RECT  25.824 0 25.848 0.084 ;
    END
  END snoop_data_o[47]
  PIN snoop_data_o[480]
    DIRECTION OUTPUT ;
    USE SIGNAL ;
    PORT
      LAYER M4 ;
        RECT  144.916 34.464 145 34.488 ;
    END
  END snoop_data_o[480]
  PIN snoop_data_o[481]
    DIRECTION OUTPUT ;
    USE SIGNAL ;
    PORT
      LAYER M4 ;
        RECT  144.916 34.656 145 34.68 ;
    END
  END snoop_data_o[481]
  PIN snoop_data_o[482]
    DIRECTION OUTPUT ;
    USE SIGNAL ;
    PORT
      LAYER M4 ;
        RECT  144.916 34.752 145 34.776 ;
    END
  END snoop_data_o[482]
  PIN snoop_data_o[483]
    DIRECTION OUTPUT ;
    USE SIGNAL ;
    PORT
      LAYER M4 ;
        RECT  144.916 34.944 145 34.968 ;
    END
  END snoop_data_o[483]
  PIN snoop_data_o[484]
    DIRECTION OUTPUT ;
    USE SIGNAL ;
    PORT
      LAYER M4 ;
        RECT  144.916 35.04 145 35.064 ;
    END
  END snoop_data_o[484]
  PIN snoop_data_o[485]
    DIRECTION OUTPUT ;
    USE SIGNAL ;
    PORT
      LAYER M4 ;
        RECT  144.916 74.304 145 74.328 ;
    END
  END snoop_data_o[485]
  PIN snoop_data_o[486]
    DIRECTION OUTPUT ;
    USE SIGNAL ;
    PORT
      LAYER M4 ;
        RECT  144.916 35.328 145 35.352 ;
    END
  END snoop_data_o[486]
  PIN snoop_data_o[487]
    DIRECTION OUTPUT ;
    USE SIGNAL ;
    PORT
      LAYER M4 ;
        RECT  144.916 35.52 145 35.544 ;
    END
  END snoop_data_o[487]
  PIN snoop_data_o[488]
    DIRECTION OUTPUT ;
    USE SIGNAL ;
    PORT
      LAYER M4 ;
        RECT  144.916 35.616 145 35.64 ;
    END
  END snoop_data_o[488]
  PIN snoop_data_o[489]
    DIRECTION OUTPUT ;
    USE SIGNAL ;
    PORT
      LAYER M4 ;
        RECT  144.916 35.808 145 35.832 ;
    END
  END snoop_data_o[489]
  PIN snoop_data_o[48]
    DIRECTION OUTPUT ;
    USE SIGNAL ;
    PORT
      LAYER M5 ;
        RECT  25.728 0 25.752 0.084 ;
    END
  END snoop_data_o[48]
  PIN snoop_data_o[490]
    DIRECTION OUTPUT ;
    USE SIGNAL ;
    PORT
      LAYER M4 ;
        RECT  144.916 62.208 145 62.232 ;
    END
  END snoop_data_o[490]
  PIN snoop_data_o[491]
    DIRECTION OUTPUT ;
    USE SIGNAL ;
    PORT
      LAYER M4 ;
        RECT  144.916 72.864 145 72.888 ;
    END
  END snoop_data_o[491]
  PIN snoop_data_o[492]
    DIRECTION OUTPUT ;
    USE SIGNAL ;
    PORT
      LAYER M4 ;
        RECT  144.916 69.12 145 69.144 ;
    END
  END snoop_data_o[492]
  PIN snoop_data_o[493]
    DIRECTION OUTPUT ;
    USE SIGNAL ;
    PORT
      LAYER M4 ;
        RECT  144.916 64.32 145 64.344 ;
    END
  END snoop_data_o[493]
  PIN snoop_data_o[494]
    DIRECTION OUTPUT ;
    USE SIGNAL ;
    PORT
      LAYER M4 ;
        RECT  144.916 69.888 145 69.912 ;
    END
  END snoop_data_o[494]
  PIN snoop_data_o[495]
    DIRECTION OUTPUT ;
    USE SIGNAL ;
    PORT
      LAYER M4 ;
        RECT  144.916 72.672 145 72.696 ;
    END
  END snoop_data_o[495]
  PIN snoop_data_o[496]
    DIRECTION OUTPUT ;
    USE SIGNAL ;
    PORT
      LAYER M4 ;
        RECT  144.916 62.784 145 62.808 ;
    END
  END snoop_data_o[496]
  PIN snoop_data_o[497]
    DIRECTION OUTPUT ;
    USE SIGNAL ;
    PORT
      LAYER M4 ;
        RECT  144.916 73.152 145 73.176 ;
    END
  END snoop_data_o[497]
  PIN snoop_data_o[498]
    DIRECTION OUTPUT ;
    USE SIGNAL ;
    PORT
      LAYER M4 ;
        RECT  144.916 66.816 145 66.84 ;
    END
  END snoop_data_o[498]
  PIN snoop_data_o[499]
    DIRECTION OUTPUT ;
    USE SIGNAL ;
    PORT
      LAYER M4 ;
        RECT  144.916 66.72 145 66.744 ;
    END
  END snoop_data_o[499]
  PIN snoop_data_o[49]
    DIRECTION OUTPUT ;
    USE SIGNAL ;
    PORT
      LAYER M5 ;
        RECT  25.632 0 25.656 0.084 ;
    END
  END snoop_data_o[49]
  PIN snoop_data_o[4]
    DIRECTION OUTPUT ;
    USE SIGNAL ;
    PORT
      LAYER M5 ;
        RECT  25.536 0 25.56 0.084 ;
    END
  END snoop_data_o[4]
  PIN snoop_data_o[500]
    DIRECTION OUTPUT ;
    USE SIGNAL ;
    PORT
      LAYER M4 ;
        RECT  144.916 66.144 145 66.168 ;
    END
  END snoop_data_o[500]
  PIN snoop_data_o[501]
    DIRECTION OUTPUT ;
    USE SIGNAL ;
    PORT
      LAYER M4 ;
        RECT  144.916 73.248 145 73.272 ;
    END
  END snoop_data_o[501]
  PIN snoop_data_o[502]
    DIRECTION OUTPUT ;
    USE SIGNAL ;
    PORT
      LAYER M4 ;
        RECT  144.916 69.024 145 69.048 ;
    END
  END snoop_data_o[502]
  PIN snoop_data_o[503]
    DIRECTION OUTPUT ;
    USE SIGNAL ;
    PORT
      LAYER M4 ;
        RECT  144.916 71.52 145 71.544 ;
    END
  END snoop_data_o[503]
  PIN snoop_data_o[504]
    DIRECTION OUTPUT ;
    USE SIGNAL ;
    PORT
      LAYER M4 ;
        RECT  144.916 74.88 145 74.904 ;
    END
  END snoop_data_o[504]
  PIN snoop_data_o[505]
    DIRECTION OUTPUT ;
    USE SIGNAL ;
    PORT
      LAYER M4 ;
        RECT  144.916 72.096 145 72.12 ;
    END
  END snoop_data_o[505]
  PIN snoop_data_o[506]
    DIRECTION OUTPUT ;
    USE SIGNAL ;
    PORT
      LAYER M4 ;
        RECT  144.916 65.088 145 65.112 ;
    END
  END snoop_data_o[506]
  PIN snoop_data_o[507]
    DIRECTION OUTPUT ;
    USE SIGNAL ;
    PORT
      LAYER M4 ;
        RECT  144.916 69.6 145 69.624 ;
    END
  END snoop_data_o[507]
  PIN snoop_data_o[508]
    DIRECTION OUTPUT ;
    USE SIGNAL ;
    PORT
      LAYER M4 ;
        RECT  144.916 67.008 145 67.032 ;
    END
  END snoop_data_o[508]
  PIN snoop_data_o[509]
    DIRECTION OUTPUT ;
    USE SIGNAL ;
    PORT
      LAYER M4 ;
        RECT  144.916 64.704 145 64.728 ;
    END
  END snoop_data_o[509]
  PIN snoop_data_o[50]
    DIRECTION OUTPUT ;
    USE SIGNAL ;
    PORT
      LAYER M5 ;
        RECT  25.44 0 25.464 0.084 ;
    END
  END snoop_data_o[50]
  PIN snoop_data_o[510]
    DIRECTION OUTPUT ;
    USE SIGNAL ;
    PORT
      LAYER M4 ;
        RECT  144.916 72.576 145 72.6 ;
    END
  END snoop_data_o[510]
  PIN snoop_data_o[511]
    DIRECTION OUTPUT ;
    USE SIGNAL ;
    PORT
      LAYER M4 ;
        RECT  144.916 38.976 145 39 ;
    END
  END snoop_data_o[511]
  PIN snoop_data_o[51]
    DIRECTION OUTPUT ;
    USE SIGNAL ;
    PORT
      LAYER M5 ;
        RECT  25.344 0 25.368 0.084 ;
    END
  END snoop_data_o[51]
  PIN snoop_data_o[52]
    DIRECTION OUTPUT ;
    USE SIGNAL ;
    PORT
      LAYER M5 ;
        RECT  25.248 0 25.272 0.084 ;
    END
  END snoop_data_o[52]
  PIN snoop_data_o[53]
    DIRECTION OUTPUT ;
    USE SIGNAL ;
    PORT
      LAYER M5 ;
        RECT  25.152 0 25.176 0.084 ;
    END
  END snoop_data_o[53]
  PIN snoop_data_o[54]
    DIRECTION OUTPUT ;
    USE SIGNAL ;
    PORT
      LAYER M5 ;
        RECT  25.056 0 25.08 0.084 ;
    END
  END snoop_data_o[54]
  PIN snoop_data_o[55]
    DIRECTION OUTPUT ;
    USE SIGNAL ;
    PORT
      LAYER M5 ;
        RECT  24.96 0 24.984 0.084 ;
    END
  END snoop_data_o[55]
  PIN snoop_data_o[56]
    DIRECTION OUTPUT ;
    USE SIGNAL ;
    PORT
      LAYER M5 ;
        RECT  24.864 0 24.888 0.084 ;
    END
  END snoop_data_o[56]
  PIN snoop_data_o[57]
    DIRECTION OUTPUT ;
    USE SIGNAL ;
    PORT
      LAYER M5 ;
        RECT  24.768 0 24.792 0.084 ;
    END
  END snoop_data_o[57]
  PIN snoop_data_o[58]
    DIRECTION OUTPUT ;
    USE SIGNAL ;
    PORT
      LAYER M5 ;
        RECT  24.672 0 24.696 0.084 ;
    END
  END snoop_data_o[58]
  PIN snoop_data_o[59]
    DIRECTION OUTPUT ;
    USE SIGNAL ;
    PORT
      LAYER M5 ;
        RECT  24.576 0 24.6 0.084 ;
    END
  END snoop_data_o[59]
  PIN snoop_data_o[5]
    DIRECTION OUTPUT ;
    USE SIGNAL ;
    PORT
      LAYER M5 ;
        RECT  24.48 0 24.504 0.084 ;
    END
  END snoop_data_o[5]
  PIN snoop_data_o[60]
    DIRECTION OUTPUT ;
    USE SIGNAL ;
    PORT
      LAYER M5 ;
        RECT  24.384 0 24.408 0.084 ;
    END
  END snoop_data_o[60]
  PIN snoop_data_o[61]
    DIRECTION OUTPUT ;
    USE SIGNAL ;
    PORT
      LAYER M5 ;
        RECT  24.288 0 24.312 0.084 ;
    END
  END snoop_data_o[61]
  PIN snoop_data_o[62]
    DIRECTION OUTPUT ;
    USE SIGNAL ;
    PORT
      LAYER M5 ;
        RECT  24.192 0 24.216 0.084 ;
    END
  END snoop_data_o[62]
  PIN snoop_data_o[63]
    DIRECTION OUTPUT ;
    USE SIGNAL ;
    PORT
      LAYER M5 ;
        RECT  24.096 0 24.12 0.084 ;
    END
  END snoop_data_o[63]
  PIN snoop_data_o[64]
    DIRECTION OUTPUT ;
    USE SIGNAL ;
    PORT
      LAYER M5 ;
        RECT  24 0 24.024 0.084 ;
    END
  END snoop_data_o[64]
  PIN snoop_data_o[65]
    DIRECTION OUTPUT ;
    USE SIGNAL ;
    PORT
      LAYER M5 ;
        RECT  23.904 0 23.928 0.084 ;
    END
  END snoop_data_o[65]
  PIN snoop_data_o[66]
    DIRECTION OUTPUT ;
    USE SIGNAL ;
    PORT
      LAYER M5 ;
        RECT  23.808 0 23.832 0.084 ;
    END
  END snoop_data_o[66]
  PIN snoop_data_o[67]
    DIRECTION OUTPUT ;
    USE SIGNAL ;
    PORT
      LAYER M5 ;
        RECT  23.712 0 23.736 0.084 ;
    END
  END snoop_data_o[67]
  PIN snoop_data_o[68]
    DIRECTION OUTPUT ;
    USE SIGNAL ;
    PORT
      LAYER M5 ;
        RECT  23.616 0 23.64 0.084 ;
    END
  END snoop_data_o[68]
  PIN snoop_data_o[69]
    DIRECTION OUTPUT ;
    USE SIGNAL ;
    PORT
      LAYER M5 ;
        RECT  23.52 0 23.544 0.084 ;
    END
  END snoop_data_o[69]
  PIN snoop_data_o[6]
    DIRECTION OUTPUT ;
    USE SIGNAL ;
    PORT
      LAYER M5 ;
        RECT  23.424 0 23.448 0.084 ;
    END
  END snoop_data_o[6]
  PIN snoop_data_o[70]
    DIRECTION OUTPUT ;
    USE SIGNAL ;
    PORT
      LAYER M5 ;
        RECT  23.328 0 23.352 0.084 ;
    END
  END snoop_data_o[70]
  PIN snoop_data_o[71]
    DIRECTION OUTPUT ;
    USE SIGNAL ;
    PORT
      LAYER M5 ;
        RECT  23.232 0 23.256 0.084 ;
    END
  END snoop_data_o[71]
  PIN snoop_data_o[72]
    DIRECTION OUTPUT ;
    USE SIGNAL ;
    PORT
      LAYER M5 ;
        RECT  23.136 0 23.16 0.084 ;
    END
  END snoop_data_o[72]
  PIN snoop_data_o[73]
    DIRECTION OUTPUT ;
    USE SIGNAL ;
    PORT
      LAYER M5 ;
        RECT  23.04 0 23.064 0.084 ;
    END
  END snoop_data_o[73]
  PIN snoop_data_o[74]
    DIRECTION OUTPUT ;
    USE SIGNAL ;
    PORT
      LAYER M5 ;
        RECT  22.944 0 22.968 0.084 ;
    END
  END snoop_data_o[74]
  PIN snoop_data_o[75]
    DIRECTION OUTPUT ;
    USE SIGNAL ;
    PORT
      LAYER M5 ;
        RECT  22.848 0 22.872 0.084 ;
    END
  END snoop_data_o[75]
  PIN snoop_data_o[76]
    DIRECTION OUTPUT ;
    USE SIGNAL ;
    PORT
      LAYER M5 ;
        RECT  22.752 0 22.776 0.084 ;
    END
  END snoop_data_o[76]
  PIN snoop_data_o[77]
    DIRECTION OUTPUT ;
    USE SIGNAL ;
    PORT
      LAYER M5 ;
        RECT  22.656 0 22.68 0.084 ;
    END
  END snoop_data_o[77]
  PIN snoop_data_o[78]
    DIRECTION OUTPUT ;
    USE SIGNAL ;
    PORT
      LAYER M5 ;
        RECT  22.56 0 22.584 0.084 ;
    END
  END snoop_data_o[78]
  PIN snoop_data_o[79]
    DIRECTION OUTPUT ;
    USE SIGNAL ;
    PORT
      LAYER M5 ;
        RECT  22.464 0 22.488 0.084 ;
    END
  END snoop_data_o[79]
  PIN snoop_data_o[7]
    DIRECTION OUTPUT ;
    USE SIGNAL ;
    PORT
      LAYER M5 ;
        RECT  22.368 0 22.392 0.084 ;
    END
  END snoop_data_o[7]
  PIN snoop_data_o[80]
    DIRECTION OUTPUT ;
    USE SIGNAL ;
    PORT
      LAYER M5 ;
        RECT  22.272 0 22.296 0.084 ;
    END
  END snoop_data_o[80]
  PIN snoop_data_o[81]
    DIRECTION OUTPUT ;
    USE SIGNAL ;
    PORT
      LAYER M5 ;
        RECT  22.176 0 22.2 0.084 ;
    END
  END snoop_data_o[81]
  PIN snoop_data_o[82]
    DIRECTION OUTPUT ;
    USE SIGNAL ;
    PORT
      LAYER M5 ;
        RECT  22.08 0 22.104 0.084 ;
    END
  END snoop_data_o[82]
  PIN snoop_data_o[83]
    DIRECTION OUTPUT ;
    USE SIGNAL ;
    PORT
      LAYER M5 ;
        RECT  21.984 0 22.008 0.084 ;
    END
  END snoop_data_o[83]
  PIN snoop_data_o[84]
    DIRECTION OUTPUT ;
    USE SIGNAL ;
    PORT
      LAYER M5 ;
        RECT  21.888 0 21.912 0.084 ;
    END
  END snoop_data_o[84]
  PIN snoop_data_o[85]
    DIRECTION OUTPUT ;
    USE SIGNAL ;
    PORT
      LAYER M5 ;
        RECT  21.792 0 21.816 0.084 ;
    END
  END snoop_data_o[85]
  PIN snoop_data_o[86]
    DIRECTION OUTPUT ;
    USE SIGNAL ;
    PORT
      LAYER M5 ;
        RECT  21.696 0 21.72 0.084 ;
    END
  END snoop_data_o[86]
  PIN snoop_data_o[87]
    DIRECTION OUTPUT ;
    USE SIGNAL ;
    PORT
      LAYER M5 ;
        RECT  21.6 0 21.624 0.084 ;
    END
  END snoop_data_o[87]
  PIN snoop_data_o[88]
    DIRECTION OUTPUT ;
    USE SIGNAL ;
    PORT
      LAYER M5 ;
        RECT  21.504 0 21.528 0.084 ;
    END
  END snoop_data_o[88]
  PIN snoop_data_o[89]
    DIRECTION OUTPUT ;
    USE SIGNAL ;
    PORT
      LAYER M5 ;
        RECT  21.408 0 21.432 0.084 ;
    END
  END snoop_data_o[89]
  PIN snoop_data_o[8]
    DIRECTION OUTPUT ;
    USE SIGNAL ;
    PORT
      LAYER M5 ;
        RECT  21.312 0 21.336 0.084 ;
    END
  END snoop_data_o[8]
  PIN snoop_data_o[90]
    DIRECTION OUTPUT ;
    USE SIGNAL ;
    PORT
      LAYER M5 ;
        RECT  21.216 0 21.24 0.084 ;
    END
  END snoop_data_o[90]
  PIN snoop_data_o[91]
    DIRECTION OUTPUT ;
    USE SIGNAL ;
    PORT
      LAYER M5 ;
        RECT  21.12 0 21.144 0.084 ;
    END
  END snoop_data_o[91]
  PIN snoop_data_o[92]
    DIRECTION OUTPUT ;
    USE SIGNAL ;
    PORT
      LAYER M5 ;
        RECT  21.024 0 21.048 0.084 ;
    END
  END snoop_data_o[92]
  PIN snoop_data_o[93]
    DIRECTION OUTPUT ;
    USE SIGNAL ;
    PORT
      LAYER M5 ;
        RECT  20.928 0 20.952 0.084 ;
    END
  END snoop_data_o[93]
  PIN snoop_data_o[94]
    DIRECTION OUTPUT ;
    USE SIGNAL ;
    PORT
      LAYER M5 ;
        RECT  20.832 0 20.856 0.084 ;
    END
  END snoop_data_o[94]
  PIN snoop_data_o[95]
    DIRECTION OUTPUT ;
    USE SIGNAL ;
    PORT
      LAYER M5 ;
        RECT  20.736 0 20.76 0.084 ;
    END
  END snoop_data_o[95]
  PIN snoop_data_o[96]
    DIRECTION OUTPUT ;
    USE SIGNAL ;
    PORT
      LAYER M5 ;
        RECT  20.64 0 20.664 0.084 ;
    END
  END snoop_data_o[96]
  PIN snoop_data_o[97]
    DIRECTION OUTPUT ;
    USE SIGNAL ;
    PORT
      LAYER M5 ;
        RECT  20.544 0 20.568 0.084 ;
    END
  END snoop_data_o[97]
  PIN snoop_data_o[98]
    DIRECTION OUTPUT ;
    USE SIGNAL ;
    PORT
      LAYER M5 ;
        RECT  20.448 0 20.472 0.084 ;
    END
  END snoop_data_o[98]
  PIN snoop_data_o[99]
    DIRECTION OUTPUT ;
    USE SIGNAL ;
    PORT
      LAYER M5 ;
        RECT  20.352 0 20.376 0.084 ;
    END
  END snoop_data_o[99]
  PIN snoop_data_o[9]
    DIRECTION OUTPUT ;
    USE SIGNAL ;
    PORT
      LAYER M5 ;
        RECT  20.256 0 20.28 0.084 ;
    END
  END snoop_data_o[9]
  PIN snoop_dirty_o[0]
    DIRECTION OUTPUT ;
    USE SIGNAL ;
    PORT
      LAYER M5 ;
        RECT  53.472 144.916 53.496 145 ;
    END
  END snoop_dirty_o[0]
  PIN snoop_dirty_o[1]
    DIRECTION OUTPUT ;
    USE SIGNAL ;
    PORT
      LAYER M5 ;
        RECT  93.792 144.916 93.816 145 ;
    END
  END snoop_dirty_o[1]
  PIN snoop_hit_o[0]
    DIRECTION OUTPUT ;
    USE SIGNAL ;
    PORT
      LAYER M5 ;
        RECT  53.664 144.916 53.688 145 ;
    END
  END snoop_hit_o[0]
  PIN snoop_hit_o[1]
    DIRECTION OUTPUT ;
    USE SIGNAL ;
    PORT
      LAYER M5 ;
        RECT  93.984 144.916 94.008 145 ;
    END
  END snoop_hit_o[1]
  PIN snoop_type_i
    DIRECTION INPUT ;
    USE SIGNAL ;
    PORT
      LAYER M5 ;
        RECT  85.824 144.916 85.848 145 ;
    END
  END snoop_type_i
  PIN snoop_valid_i[0]
    DIRECTION INPUT ;
    USE SIGNAL ;
    PORT
      LAYER M5 ;
        RECT  51.168 144.916 51.192 145 ;
    END
  END snoop_valid_i[0]
  PIN snoop_valid_i[1]
    DIRECTION INPUT ;
    USE SIGNAL ;
    PORT
      LAYER M4 ;
        RECT  144.916 90.336 145 90.36 ;
    END
  END snoop_valid_i[1]
  PIN VDD
    DIRECTION INOUT ;
    USE POWER ;
    PORT
      LAYER M6 ;
        RECT  1.026 142.233 143.964 142.521 ;
        RECT  1.026 136.833 143.964 137.121 ;
        RECT  1.026 131.433 143.964 131.721 ;
        RECT  1.026 126.033 143.964 126.321 ;
        RECT  1.026 120.633 143.964 120.921 ;
        RECT  1.026 115.233 143.964 115.521 ;
        RECT  1.026 109.833 143.964 110.121 ;
        RECT  1.026 104.433 143.964 104.721 ;
        RECT  1.026 99.033 143.964 99.321 ;
        RECT  1.026 93.633 143.964 93.921 ;
        RECT  1.026 88.233 143.964 88.521 ;
        RECT  1.026 82.833 143.964 83.121 ;
        RECT  1.026 77.433 143.964 77.721 ;
        RECT  1.026 72.033 143.964 72.321 ;
        RECT  1.026 66.633 143.964 66.921 ;
        RECT  1.026 61.233 143.964 61.521 ;
        RECT  1.026 55.833 143.964 56.121 ;
        RECT  1.026 50.433 143.964 50.721 ;
        RECT  1.026 45.033 143.964 45.321 ;
        RECT  1.026 39.633 143.964 39.921 ;
        RECT  1.026 34.233 143.964 34.521 ;
        RECT  1.026 28.833 143.964 29.121 ;
        RECT  1.026 23.433 143.964 23.721 ;
        RECT  1.026 18.033 143.964 18.321 ;
        RECT  1.026 12.633 143.964 12.921 ;
        RECT  1.026 7.233 143.964 7.521 ;
        RECT  1.026 1.833 143.964 2.121 ;
    END
  END VDD
  PIN VSS
    DIRECTION INOUT ;
    USE GROUND ;
    PORT
      LAYER M6 ;
        RECT  1.026 141.849 143.964 142.137 ;
        RECT  1.026 136.449 143.964 136.737 ;
        RECT  1.026 131.049 143.964 131.337 ;
        RECT  1.026 125.649 143.964 125.937 ;
        RECT  1.026 120.249 143.964 120.537 ;
        RECT  1.026 114.849 143.964 115.137 ;
        RECT  1.026 109.449 143.964 109.737 ;
        RECT  1.026 104.049 143.964 104.337 ;
        RECT  1.026 98.649 143.964 98.937 ;
        RECT  1.026 93.249 143.964 93.537 ;
        RECT  1.026 87.849 143.964 88.137 ;
        RECT  1.026 82.449 143.964 82.737 ;
        RECT  1.026 77.049 143.964 77.337 ;
        RECT  1.026 71.649 143.964 71.937 ;
        RECT  1.026 66.249 143.964 66.537 ;
        RECT  1.026 60.849 143.964 61.137 ;
        RECT  1.026 55.449 143.964 55.737 ;
        RECT  1.026 50.049 143.964 50.337 ;
        RECT  1.026 44.649 143.964 44.937 ;
        RECT  1.026 39.249 143.964 39.537 ;
        RECT  1.026 33.849 143.964 34.137 ;
        RECT  1.026 28.449 143.964 28.737 ;
        RECT  1.026 23.049 143.964 23.337 ;
        RECT  1.026 17.649 143.964 17.937 ;
        RECT  1.026 12.249 143.964 12.537 ;
        RECT  1.026 6.849 143.964 7.137 ;
        RECT  1.026 1.449 143.964 1.737 ;
    END
  END VSS
  OBS
    LAYER LVTN ;
     RECT  0 0 145 145 ;
    LAYER LVTP ;
     RECT  0 0 145 145 ;
    LAYER RVTN ;
     RECT  0 0 145 145 ;
    LAYER RVTP ;
     RECT  0 0 145 145 ;
    LAYER M1 ;
     RECT  0 0 145 145 ;
    LAYER M2 ;
     RECT  0 0 145 145 ;
    LAYER M3 ;
     RECT  0 0 145 145 ;
    LAYER M4 ;
     RECT  0 0 145 145 ;
    LAYER M5 ;
     RECT  0 0 145 145 ;
    LAYER M6 ;
     RECT  0 0 145 145 ;
    LAYER M7 ;
     RECT  0 0 145 145 ;
  END
END e_tile
END LIBRARY
